# Confidential Information of ARM, Inc.
# Use subject to ARM license.
# Copyright (c) 2026 ARM, Inc.

# ACI Version r0p0

# Reifier 4.0.0

VERSION 5.7 ;

BUSBITCHARS "[]" ;

#name: High Density Single Port SRAM HVT RVT Compiler | TSMC CLN65LP Process 0.525um^2 Bit Cell 256 Rows Per Bank
#version: r0p0
#comment: 
#configuration:  -activity_factor 50 -back_biasing off -bits 32 -bmux on -bus_notation on -check_instname on -diodes on -drive 6 -ema on -frequency 1.0 -instname sp_hse_8192_m16 -left_bus_delim "[" -mux 16 -mvt "" -name_case upper -power_type otc -prefix "" -pwr_gnd_rename vddpe:VDDPE,vddce:VDDCE,vsse:VSSE -rcols 2 -redundancy off -retention on -right_bus_delim "]" -rows_p_bl 256 -rrows 0 -ser none -site_def off -top_layer m5-m9 -words 8192 -wp_size 1 -write_mask on -write_thru off -corners ff_1p32v_1p32v_125c,ff_1p32v_1p32v_m40c,ss_1p08v_1p08v_125c,ss_1p08v_1p08v_m40c,tt_1p20v_1p20v_25c
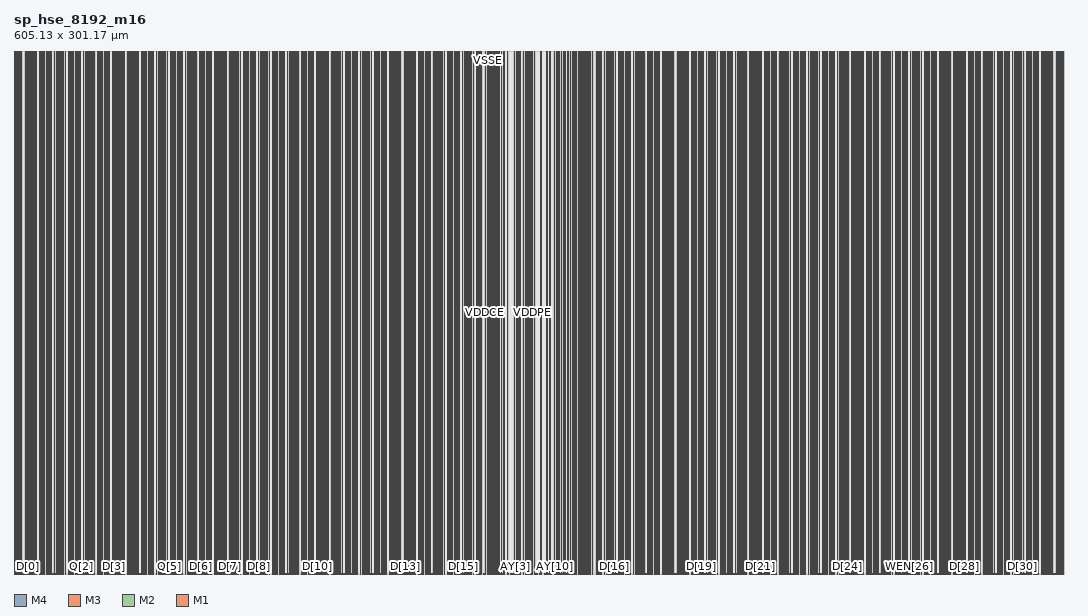
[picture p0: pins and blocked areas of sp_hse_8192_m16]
MACRO sp_hse_8192_m16
  FOREIGN sp_hse_8192_m16 0 0 ;
  SYMMETRY X Y R90 ;
  SIZE 605.13 BY 301.17 ;
  CLASS BLOCK ;
  PIN AY[0]
    DIRECTION OUTPUT ;
    USE SIGNAL ;
    SHAPE ABUTMENT ;
    PORT
      LAYER M4 ;
      RECT 305.835 0.0 306.055 0.32 ;
      LAYER M3 ;
      RECT 305.835 0.0 306.055 0.32 ;
      LAYER M2 ;
      RECT 305.835 0.0 306.055 0.32 ;
      LAYER M1 ;
      RECT 305.835 0.0 306.055 0.32 ;
      END
    ANTENNADIFFAREA 0.054 ;
    END AY[0]
  PIN TA[0]
    DIRECTION INPUT ;
    USE SIGNAL ;
    SHAPE ABUTMENT ;
    PORT
      LAYER M1 ;
      RECT 306.4 0.0 306.62 0.32 ;
      LAYER M2 ;
      RECT 306.4 0.0 306.62 0.32 ;
      LAYER M3 ;
      RECT 306.4 0.0 306.62 0.32 ;
      LAYER M4 ;
      RECT 306.4 0.0 306.62 0.32 ;
      END
    ANTENNAGATEAREA 0.0072 ;
    ANTENNADIFFAREA 0.054 ;
    END TA[0]
  PIN AY[1]
    DIRECTION OUTPUT ;
    USE SIGNAL ;
    SHAPE ABUTMENT ;
    PORT
      LAYER M4 ;
      RECT 302.61 0.0 302.83 0.32 ;
      LAYER M3 ;
      RECT 302.61 0.0 302.83 0.32 ;
      LAYER M2 ;
      RECT 302.61 0.0 302.83 0.32 ;
      LAYER M1 ;
      RECT 302.61 0.0 302.83 0.32 ;
      END
    ANTENNADIFFAREA 0.054 ;
    END AY[1]
  PIN A[0]
    DIRECTION INPUT ;
    USE SIGNAL ;
    SHAPE ABUTMENT ;
    PORT
      LAYER M1 ;
      RECT 306.85 0.0 307.07 0.32 ;
      LAYER M2 ;
      RECT 306.85 0.0 307.07 0.32 ;
      LAYER M3 ;
      RECT 306.85 0.0 307.07 0.32 ;
      END
    ANTENNAGATEAREA 0.0072 ;
    ANTENNADIFFAREA 0.054 ;
    END A[0]
  PIN A[1]
    DIRECTION INPUT ;
    USE SIGNAL ;
    SHAPE ABUTMENT ;
    PORT
      LAYER M4 ;
      RECT 301.225 0.0 301.445 0.32 ;
      LAYER M3 ;
      RECT 301.225 0.0 301.445 0.32 ;
      LAYER M2 ;
      RECT 301.225 0.0 301.445 0.32 ;
      LAYER M1 ;
      RECT 301.225 0.0 301.445 0.32 ;
      END
    ANTENNAGATEAREA 0.0072 ;
    ANTENNADIFFAREA 0.054 ;
    END A[1]
  PIN TA[11]
    DIRECTION INPUT ;
    USE SIGNAL ;
    SHAPE ABUTMENT ;
    PORT
      LAYER M1 ;
      RECT 307.295 0.0 307.515 0.32 ;
      LAYER M2 ;
      RECT 307.295 0.0 307.515 0.32 ;
      LAYER M3 ;
      RECT 307.295 0.0 307.515 0.32 ;
      END
    ANTENNAGATEAREA 0.0072 ;
    ANTENNADIFFAREA 0.054 ;
    END TA[11]
  PIN TA[1]
    DIRECTION INPUT ;
    USE SIGNAL ;
    SHAPE ABUTMENT ;
    PORT
      LAYER M4 ;
      RECT 300.785 0.0 300.995 0.32 ;
      LAYER M3 ;
      RECT 300.785 0.0 300.995 0.32 ;
      LAYER M2 ;
      RECT 300.785 0.0 300.995 0.32 ;
      LAYER M1 ;
      RECT 300.785 0.0 300.995 0.32 ;
      END
    ANTENNAGATEAREA 0.0072 ;
    ANTENNADIFFAREA 0.054 ;
    END TA[1]
  PIN A[11]
    DIRECTION INPUT ;
    USE SIGNAL ;
    SHAPE ABUTMENT ;
    PORT
      LAYER M1 ;
      RECT 307.745 0.0 307.965 0.32 ;
      LAYER M2 ;
      RECT 307.745 0.0 307.965 0.32 ;
      LAYER M3 ;
      RECT 307.745 0.0 307.965 0.32 ;
      END
    ANTENNAGATEAREA 0.0072 ;
    ANTENNADIFFAREA 0.054 ;
    END A[11]
  PIN TA[12]
    DIRECTION INPUT ;
    USE SIGNAL ;
    SHAPE ABUTMENT ;
    PORT
      LAYER M3 ;
      RECT 300.33 0.0 300.55 0.32 ;
      LAYER M2 ;
      RECT 300.33 0.0 300.55 0.32 ;
      LAYER M1 ;
      RECT 300.33 0.0 300.55 0.32 ;
      END
    ANTENNAGATEAREA 0.0072 ;
    ANTENNADIFFAREA 0.054 ;
    END TA[12]
  PIN EMA[1]
    DIRECTION INPUT ;
    USE SIGNAL ;
    SHAPE ABUTMENT ;
    PORT
      LAYER M1 ;
      RECT 308.215 0.0 308.435 0.32 ;
      LAYER M2 ;
      RECT 308.215 0.0 308.435 0.32 ;
      LAYER M3 ;
      RECT 308.215 0.0 308.435 0.32 ;
      END
    ANTENNAGATEAREA 0.0072 ;
    ANTENNADIFFAREA 0.054 ;
    END EMA[1]
  PIN A[12]
    DIRECTION INPUT ;
    USE SIGNAL ;
    SHAPE ABUTMENT ;
    PORT
      LAYER M3 ;
      RECT 299.855 0.0 300.075 0.32 ;
      LAYER M2 ;
      RECT 299.855 0.0 300.075 0.32 ;
      LAYER M1 ;
      RECT 299.855 0.0 300.075 0.32 ;
      END
    ANTENNAGATEAREA 0.0072 ;
    ANTENNADIFFAREA 0.054 ;
    END A[12]
  PIN AY[11]
    DIRECTION OUTPUT ;
    USE SIGNAL ;
    SHAPE ABUTMENT ;
    PORT
      LAYER M1 ;
      RECT 309.115 0.0 309.335 0.32 ;
      LAYER M2 ;
      RECT 309.115 0.0 309.335 0.32 ;
      END
    ANTENNADIFFAREA 0.054 ;
    END AY[11]
  PIN AY[12]
    DIRECTION OUTPUT ;
    USE SIGNAL ;
    SHAPE ABUTMENT ;
    PORT
      LAYER M3 ;
      RECT 298.46 0.0 298.68 0.32 ;
      LAYER M2 ;
      RECT 298.46 0.0 298.68 0.32 ;
      LAYER M1 ;
      RECT 298.46 0.0 298.68 0.32 ;
      END
    ANTENNADIFFAREA 0.054 ;
    END AY[12]
  PIN EMAW[0]
    DIRECTION INPUT ;
    USE SIGNAL ;
    SHAPE ABUTMENT ;
    PORT
      LAYER M1 ;
      RECT 309.57 0.0 309.79 0.32 ;
      LAYER M2 ;
      RECT 309.57 0.0 309.79 0.32 ;
      LAYER M3 ;
      RECT 309.57 0.0 309.79 0.32 ;
      LAYER M4 ;
      RECT 309.57 0.0 309.79 0.32 ;
      END
    ANTENNAGATEAREA 0.0072 ;
    ANTENNADIFFAREA 0.054 ;
    END EMAW[0]
  PIN RET1N
    DIRECTION INPUT ;
    USE SIGNAL ;
    SHAPE ABUTMENT ;
    PORT
      LAYER M4 ;
      RECT 290.225 0.0 290.445 0.32 ;
      LAYER M3 ;
      RECT 290.225 0.0 290.445 0.32 ;
      LAYER M2 ;
      RECT 290.225 0.0 290.445 0.32 ;
      LAYER M1 ;
      RECT 290.225 0.0 290.445 0.32 ;
      END
    ANTENNAGATEAREA 0.0072 ;
    ANTENNADIFFAREA 0.054 ;
    END RET1N
  PIN AY[10]
    DIRECTION OUTPUT ;
    USE SIGNAL ;
    SHAPE ABUTMENT ;
    PORT
      LAYER M1 ;
      RECT 311.945 0.0 312.155 0.32 ;
      LAYER M2 ;
      RECT 311.945 0.0 312.155 0.32 ;
      LAYER M3 ;
      RECT 311.945 0.0 312.155 0.32 ;
      LAYER M4 ;
      RECT 311.945 0.0 312.155 0.32 ;
      END
    ANTENNADIFFAREA 0.054 ;
    END AY[10]
  PIN AY[3]
    DIRECTION OUTPUT ;
    USE SIGNAL ;
    SHAPE ABUTMENT ;
    PORT
      LAYER M4 ;
      RECT 289.035 0.0 289.255 0.32 ;
      LAYER M3 ;
      RECT 289.035 0.0 289.255 0.32 ;
      LAYER M2 ;
      RECT 289.035 0.0 289.255 0.32 ;
      LAYER M1 ;
      RECT 289.035 0.0 289.255 0.32 ;
      END
    ANTENNADIFFAREA 0.054 ;
    END AY[3]
  PIN A[10]
    DIRECTION INPUT ;
    USE SIGNAL ;
    SHAPE ABUTMENT ;
    PORT
      LAYER M1 ;
      RECT 313.29 0.0 313.51 0.32 ;
      LAYER M2 ;
      RECT 313.29 0.0 313.51 0.32 ;
      LAYER M3 ;
      RECT 313.29 0.0 313.51 0.32 ;
      LAYER M4 ;
      RECT 313.29 0.0 313.51 0.32 ;
      END
    ANTENNAGATEAREA 0.0072 ;
    ANTENNADIFFAREA 0.054 ;
    END A[10]
  PIN TEN
    DIRECTION INPUT ;
    USE SIGNAL ;
    SHAPE ABUTMENT ;
    PORT
      LAYER M3 ;
      RECT 288.265 0.0 288.485 0.32 ;
      LAYER M2 ;
      RECT 288.265 0.0 288.485 0.32 ;
      LAYER M1 ;
      RECT 288.265 0.0 288.485 0.32 ;
      END
    ANTENNAGATEAREA 0.0072 ;
    ANTENNADIFFAREA 0.054 ;
    END TEN
  PIN TA[10]
    DIRECTION INPUT ;
    USE SIGNAL ;
    SHAPE ABUTMENT ;
    PORT
      LAYER M1 ;
      RECT 313.74 0.0 313.96 0.32 ;
      LAYER M2 ;
      RECT 313.74 0.0 313.96 0.32 ;
      LAYER M3 ;
      RECT 313.74 0.0 313.96 0.32 ;
      END
    ANTENNAGATEAREA 0.0072 ;
    ANTENNADIFFAREA 0.054 ;
    END TA[10]
  PIN A[3]
    DIRECTION INPUT ;
    USE SIGNAL ;
    SHAPE ABUTMENT ;
    PORT
      LAYER M2 ;
      RECT 287.815 0.0 288.035 0.32 ;
      LAYER M1 ;
      RECT 287.815 0.0 288.035 0.32 ;
      END
    ANTENNAGATEAREA 0.0072 ;
    ANTENNADIFFAREA 0.054 ;
    END A[3]
  PIN TA[9]
    DIRECTION INPUT ;
    USE SIGNAL ;
    SHAPE ABUTMENT ;
    PORT
      LAYER M1 ;
      RECT 314.19 0.0 314.41 0.32 ;
      LAYER M2 ;
      RECT 314.19 0.0 314.41 0.32 ;
      LAYER M3 ;
      RECT 314.19 0.0 314.41 0.32 ;
      END
    ANTENNAGATEAREA 0.0072 ;
    ANTENNADIFFAREA 0.054 ;
    END TA[9]
  PIN TA[3]
    DIRECTION INPUT ;
    USE SIGNAL ;
    SHAPE ABUTMENT ;
    PORT
      LAYER M2 ;
      RECT 287.365 0.0 287.585 0.32 ;
      LAYER M1 ;
      RECT 287.365 0.0 287.585 0.32 ;
      END
    ANTENNAGATEAREA 0.0072 ;
    ANTENNADIFFAREA 0.054 ;
    END TA[3]
  PIN A[9]
    DIRECTION INPUT ;
    USE SIGNAL ;
    SHAPE ABUTMENT ;
    PORT
      LAYER M1 ;
      RECT 314.63 0.0 314.85 0.32 ;
      LAYER M2 ;
      RECT 314.63 0.0 314.85 0.32 ;
      LAYER M3 ;
      RECT 314.63 0.0 314.85 0.32 ;
      LAYER M4 ;
      RECT 314.63 0.0 314.85 0.32 ;
      END
    ANTENNAGATEAREA 0.0072 ;
    ANTENNADIFFAREA 0.054 ;
    END A[9]
  PIN TCEN
    DIRECTION INPUT ;
    USE SIGNAL ;
    SHAPE ABUTMENT ;
    PORT
      LAYER M3 ;
      RECT 286.92 0.0 287.14 0.32 ;
      LAYER M2 ;
      RECT 286.92 0.0 287.14 0.32 ;
      LAYER M1 ;
      RECT 286.92 0.0 287.14 0.32 ;
      END
    ANTENNAGATEAREA 0.0072 ;
    ANTENNADIFFAREA 0.054 ;
    END TCEN
  PIN AY[9]
    DIRECTION OUTPUT ;
    USE SIGNAL ;
    SHAPE ABUTMENT ;
    PORT
      LAYER M1 ;
      RECT 315.51 0.0 315.73 0.32 ;
      LAYER M2 ;
      RECT 315.51 0.0 315.73 0.32 ;
      END
    ANTENNADIFFAREA 0.054 ;
    END AY[9]
  PIN CEN
    DIRECTION INPUT ;
    USE SIGNAL ;
    SHAPE ABUTMENT ;
    PORT
      LAYER M4 ;
      RECT 286.47 0.0 286.69 0.32 ;
      LAYER M3 ;
      RECT 286.47 0.0 286.69 0.32 ;
      LAYER M2 ;
      RECT 286.47 0.0 286.69 0.32 ;
      LAYER M1 ;
      RECT 286.47 0.0 286.69 0.32 ;
      END
    ANTENNAGATEAREA 0.0072 ;
    ANTENNADIFFAREA 0.054 ;
    END CEN
  PIN EMAW[1]
    DIRECTION INPUT ;
    USE SIGNAL ;
    SHAPE ABUTMENT ;
    PORT
      LAYER M1 ;
      RECT 316.09 0.0 316.31 0.32 ;
      LAYER M2 ;
      RECT 316.09 0.0 316.31 0.32 ;
      LAYER M3 ;
      RECT 316.09 0.0 316.31 0.32 ;
      LAYER M4 ;
      RECT 316.09 0.0 316.31 0.32 ;
      END
    ANTENNAGATEAREA 0.0072 ;
    ANTENNADIFFAREA 0.054 ;
    END EMAW[1]
  PIN DFTRAMBYP
    DIRECTION INPUT ;
    USE SIGNAL ;
    SHAPE ABUTMENT ;
    PORT
      LAYER M4 ;
      RECT 286.025 0.0 286.245 0.32 ;
      LAYER M3 ;
      RECT 286.025 0.0 286.245 0.32 ;
      END
    ANTENNAGATEAREA 0.0072 ;
    ANTENNADIFFAREA 0.054 ;
    END DFTRAMBYP
  PIN CLK
    DIRECTION INPUT ;
    USE SIGNAL ;
    SHAPE ABUTMENT ;
    PORT
      LAYER M1 ;
      RECT 317.65 0.0 317.87 0.32 ;
      LAYER M2 ;
      RECT 317.65 0.0 317.87 0.32 ;
      LAYER M3 ;
      RECT 317.65 0.0 317.87 0.32 ;
      END
    ANTENNAGATEAREA 0.0072 ;
    ANTENNADIFFAREA 0.054 ;
    END CLK
  PIN CENY
    DIRECTION OUTPUT ;
    USE SIGNAL ;
    SHAPE ABUTMENT ;
    PORT
      LAYER M4 ;
      RECT 285.035 0.0 285.255 0.32 ;
      LAYER M3 ;
      RECT 285.035 0.0 285.255 0.32 ;
      LAYER M2 ;
      RECT 285.035 0.0 285.255 0.32 ;
      LAYER M1 ;
      RECT 285.035 0.0 285.255 0.32 ;
      END
    ANTENNADIFFAREA 0.054 ;
    END CENY
  PIN EMA[0]
    DIRECTION INPUT ;
    USE SIGNAL ;
    SHAPE ABUTMENT ;
    PORT
      LAYER M1 ;
      RECT 318.11 0.0 318.33 0.32 ;
      LAYER M2 ;
      RECT 318.11 0.0 318.33 0.32 ;
      LAYER M3 ;
      RECT 318.11 0.0 318.33 0.32 ;
      LAYER M4 ;
      RECT 318.11 0.0 318.33 0.32 ;
      END
    ANTENNAGATEAREA 0.0072 ;
    ANTENNADIFFAREA 0.054 ;
    END EMA[0]
  PIN GWENY
    DIRECTION OUTPUT ;
    USE SIGNAL ;
    SHAPE ABUTMENT ;
    PORT
      LAYER M3 ;
      RECT 282.48 0.0 282.7 0.32 ;
      LAYER M2 ;
      RECT 282.48 0.0 282.7 0.32 ;
      LAYER M1 ;
      RECT 282.48 0.0 282.7 0.32 ;
      END
    ANTENNADIFFAREA 0.054 ;
    END GWENY
  PIN AY[8]
    DIRECTION OUTPUT ;
    USE SIGNAL ;
    SHAPE ABUTMENT ;
    PORT
      LAYER M1 ;
      RECT 318.56 0.0 318.78 0.32 ;
      LAYER M2 ;
      RECT 318.56 0.0 318.78 0.32 ;
      LAYER M3 ;
      RECT 318.56 0.0 318.78 0.32 ;
      LAYER M4 ;
      RECT 318.56 0.0 318.78 0.32 ;
      END
    ANTENNADIFFAREA 0.054 ;
    END AY[8]
  PIN GWEN
    DIRECTION INPUT ;
    USE SIGNAL ;
    SHAPE ABUTMENT ;
    PORT
      LAYER M3 ;
      RECT 281.11 0.0 281.33 0.32 ;
      LAYER M2 ;
      RECT 281.11 0.0 281.33 0.32 ;
      LAYER M1 ;
      RECT 281.11 0.0 281.33 0.32 ;
      END
    ANTENNAGATEAREA 0.0072 ;
    ANTENNADIFFAREA 0.054 ;
    END GWEN
  PIN EMA[2]
    DIRECTION INPUT ;
    USE SIGNAL ;
    SHAPE ABUTMENT ;
    PORT
      LAYER M1 ;
      RECT 319.52 0.0 319.74 0.32 ;
      LAYER M2 ;
      RECT 319.52 0.0 319.74 0.32 ;
      LAYER M3 ;
      RECT 319.52 0.0 319.74 0.32 ;
      END
    ANTENNAGATEAREA 0.0072 ;
    ANTENNADIFFAREA 0.054 ;
    END EMA[2]
  PIN TGWEN
    DIRECTION INPUT ;
    USE SIGNAL ;
    SHAPE ABUTMENT ;
    PORT
      LAYER M3 ;
      RECT 280.665 0.0 280.885 0.32 ;
      LAYER M2 ;
      RECT 280.665 0.0 280.885 0.32 ;
      LAYER M1 ;
      RECT 280.665 0.0 280.885 0.32 ;
      END
    ANTENNAGATEAREA 0.0072 ;
    ANTENNADIFFAREA 0.054 ;
    END TGWEN
  PIN A[8]
    DIRECTION INPUT ;
    USE SIGNAL ;
    SHAPE ABUTMENT ;
    PORT
      LAYER M1 ;
      RECT 319.995 0.0 320.215 0.32 ;
      LAYER M2 ;
      RECT 319.995 0.0 320.215 0.32 ;
      LAYER M3 ;
      RECT 319.995 0.0 320.215 0.32 ;
      LAYER M4 ;
      RECT 319.995 0.0 320.215 0.32 ;
      END
    ANTENNAGATEAREA 0.0072 ;
    ANTENNADIFFAREA 0.054 ;
    END A[8]
  PIN TA[2]
    DIRECTION INPUT ;
    USE SIGNAL ;
    SHAPE ABUTMENT ;
    PORT
      LAYER M4 ;
      RECT 280.215 0.0 280.435 0.32 ;
      LAYER M3 ;
      RECT 280.215 0.0 280.435 0.32 ;
      LAYER M2 ;
      RECT 280.215 0.0 280.435 0.32 ;
      LAYER M1 ;
      RECT 280.215 0.0 280.435 0.32 ;
      END
    ANTENNAGATEAREA 0.0072 ;
    ANTENNADIFFAREA 0.054 ;
    END TA[2]
  PIN TA[8]
    DIRECTION INPUT ;
    USE SIGNAL ;
    SHAPE ABUTMENT ;
    PORT
      LAYER M1 ;
      RECT 320.44 0.0 320.66 0.32 ;
      LAYER M2 ;
      RECT 320.44 0.0 320.66 0.32 ;
      LAYER M3 ;
      RECT 320.44 0.0 320.66 0.32 ;
      END
    ANTENNAGATEAREA 0.0072 ;
    ANTENNADIFFAREA 0.054 ;
    END TA[8]
  PIN A[2]
    DIRECTION INPUT ;
    USE SIGNAL ;
    SHAPE ABUTMENT ;
    PORT
      LAYER M3 ;
      RECT 279.77 0.0 279.99 0.32 ;
      LAYER M2 ;
      RECT 279.77 0.0 279.99 0.32 ;
      LAYER M1 ;
      RECT 279.77 0.0 279.99 0.32 ;
      END
    ANTENNAGATEAREA 0.0072 ;
    ANTENNADIFFAREA 0.054 ;
    END A[2]
  PIN TA[7]
    DIRECTION INPUT ;
    USE SIGNAL ;
    SHAPE ABUTMENT ;
    PORT
      LAYER M1 ;
      RECT 320.895 0.0 321.115 0.32 ;
      LAYER M2 ;
      RECT 320.895 0.0 321.115 0.32 ;
      LAYER M3 ;
      RECT 320.895 0.0 321.115 0.32 ;
      END
    ANTENNAGATEAREA 0.0072 ;
    ANTENNADIFFAREA 0.054 ;
    END TA[7]
  PIN AY[2]
    DIRECTION OUTPUT ;
    USE SIGNAL ;
    SHAPE ABUTMENT ;
    PORT
      LAYER M4 ;
      RECT 277.635 0.0 277.855 0.32 ;
      LAYER M3 ;
      RECT 277.635 0.0 277.855 0.32 ;
      LAYER M2 ;
      RECT 277.635 0.0 277.855 0.32 ;
      LAYER M1 ;
      RECT 277.635 0.0 277.855 0.32 ;
      END
    ANTENNADIFFAREA 0.054 ;
    END AY[2]
  PIN A[7]
    DIRECTION INPUT ;
    USE SIGNAL ;
    SHAPE ABUTMENT ;
    PORT
      LAYER M1 ;
      RECT 321.34 0.0 321.56 0.32 ;
      LAYER M2 ;
      RECT 321.34 0.0 321.56 0.32 ;
      LAYER M3 ;
      RECT 321.34 0.0 321.56 0.32 ;
      LAYER M4 ;
      RECT 321.34 0.0 321.56 0.32 ;
      END
    ANTENNAGATEAREA 0.0072 ;
    ANTENNADIFFAREA 0.054 ;
    END A[7]
  PIN AY[5]
    DIRECTION OUTPUT ;
    USE SIGNAL ;
    SHAPE ABUTMENT ;
    PORT
      LAYER M3 ;
      RECT 275.72 0.0 275.94 0.32 ;
      LAYER M2 ;
      RECT 275.72 0.0 275.94 0.32 ;
      LAYER M1 ;
      RECT 275.72 0.0 275.94 0.32 ;
      END
    ANTENNADIFFAREA 0.054 ;
    END AY[5]
  PIN AY[7]
    DIRECTION OUTPUT ;
    USE SIGNAL ;
    SHAPE ABUTMENT ;
    PORT
      LAYER M1 ;
      RECT 323.095 0.0 323.315 0.32 ;
      LAYER M2 ;
      RECT 323.095 0.0 323.315 0.32 ;
      LAYER M3 ;
      RECT 323.095 0.0 323.315 0.32 ;
      END
    ANTENNADIFFAREA 0.054 ;
    END AY[7]
  PIN A[5]
    DIRECTION INPUT ;
    USE SIGNAL ;
    SHAPE ABUTMENT ;
    PORT
      LAYER M3 ;
      RECT 274.49 0.0 274.71 0.32 ;
      LAYER M2 ;
      RECT 274.49 0.0 274.71 0.32 ;
      LAYER M1 ;
      RECT 274.49 0.0 274.71 0.32 ;
      END
    ANTENNAGATEAREA 0.0072 ;
    ANTENNADIFFAREA 0.054 ;
    END A[5]
  PIN SO[1]
    DIRECTION OUTPUT ;
    USE SIGNAL ;
    SHAPE ABUTMENT ;
    PORT
      LAYER M1 ;
      RECT 325.48 0.0 325.7 0.32 ;
      LAYER M2 ;
      RECT 325.48 0.0 325.7 0.32 ;
      LAYER M3 ;
      RECT 325.48 0.0 325.7 0.32 ;
      END
    ANTENNADIFFAREA 0.054 ;
    END SO[1]
  PIN TA[5]
    DIRECTION INPUT ;
    USE SIGNAL ;
    SHAPE ABUTMENT ;
    PORT
      LAYER M3 ;
      RECT 274.04 0.0 274.26 0.32 ;
      LAYER M2 ;
      RECT 274.04 0.0 274.26 0.32 ;
      LAYER M1 ;
      RECT 274.04 0.0 274.26 0.32 ;
      END
    ANTENNAGATEAREA 0.0072 ;
    ANTENNADIFFAREA 0.054 ;
    END TA[5]
  PIN AY[6]
    DIRECTION OUTPUT ;
    USE SIGNAL ;
    SHAPE ABUTMENT ;
    PORT
      LAYER M1 ;
      RECT 325.955 0.0 326.175 0.32 ;
      LAYER M2 ;
      RECT 325.955 0.0 326.175 0.32 ;
      LAYER M3 ;
      RECT 325.955 0.0 326.175 0.32 ;
      LAYER M4 ;
      RECT 325.955 0.0 326.175 0.32 ;
      END
    ANTENNADIFFAREA 0.054 ;
    END AY[6]
  PIN TA[4]
    DIRECTION INPUT ;
    USE SIGNAL ;
    SHAPE ABUTMENT ;
    PORT
      LAYER M4 ;
      RECT 273.6 0.0 273.82 0.32 ;
      LAYER M3 ;
      RECT 273.6 0.0 273.82 0.32 ;
      LAYER M2 ;
      RECT 273.6 0.0 273.82 0.32 ;
      LAYER M1 ;
      RECT 273.6 0.0 273.82 0.32 ;
      END
    ANTENNAGATEAREA 0.0072 ;
    ANTENNADIFFAREA 0.054 ;
    END TA[4]
  PIN A[6]
    DIRECTION INPUT ;
    USE SIGNAL ;
    SHAPE ABUTMENT ;
    PORT
      LAYER M1 ;
      RECT 326.88 0.0 327.1 0.32 ;
      LAYER M2 ;
      RECT 326.88 0.0 327.1 0.32 ;
      LAYER M3 ;
      RECT 326.88 0.0 327.1 0.32 ;
      END
    ANTENNAGATEAREA 0.0072 ;
    ANTENNADIFFAREA 0.054 ;
    END A[6]
  PIN A[4]
    DIRECTION INPUT ;
    USE SIGNAL ;
    SHAPE ABUTMENT ;
    PORT
      LAYER M3 ;
      RECT 273.145 0.0 273.375 0.32 ;
      LAYER M2 ;
      RECT 273.145 0.0 273.375 0.32 ;
      LAYER M1 ;
      RECT 273.145 0.0 273.375 0.32 ;
      END
    ANTENNAGATEAREA 0.0072 ;
    ANTENNADIFFAREA 0.054 ;
    END A[4]
  PIN TA[6]
    DIRECTION INPUT ;
    USE SIGNAL ;
    SHAPE ABUTMENT ;
    PORT
      LAYER M1 ;
      RECT 327.32 0.0 327.54 0.32 ;
      LAYER M2 ;
      RECT 327.32 0.0 327.54 0.32 ;
      LAYER M3 ;
      RECT 327.32 0.0 327.54 0.32 ;
      LAYER M4 ;
      RECT 327.32 0.0 327.54 0.32 ;
      END
    ANTENNAGATEAREA 0.0072 ;
    ANTENNADIFFAREA 0.054 ;
    END TA[6]
  PIN AY[4]
    DIRECTION OUTPUT ;
    USE SIGNAL ;
    SHAPE ABUTMENT ;
    PORT
      LAYER M4 ;
      RECT 270.83 0.0 271.05 0.32 ;
      LAYER M3 ;
      RECT 270.83 0.0 271.05 0.32 ;
      LAYER M2 ;
      RECT 270.83 0.0 271.05 0.32 ;
      LAYER M1 ;
      RECT 270.83 0.0 271.05 0.32 ;
      END
    ANTENNADIFFAREA 0.054 ;
    END AY[4]
  PIN SE
    DIRECTION INPUT ;
    USE SIGNAL ;
    SHAPE ABUTMENT ;
    PORT
      LAYER M1 ;
      RECT 327.765 0.0 327.985 0.32 ;
      LAYER M2 ;
      RECT 327.765 0.0 327.985 0.32 ;
      LAYER M3 ;
      RECT 327.765 0.0 327.985 0.32 ;
      END
    ANTENNAGATEAREA 0.0072 ;
    ANTENNADIFFAREA 0.054 ;
    END SE
  PIN SO[0]
    DIRECTION OUTPUT ;
    USE SIGNAL ;
    SHAPE ABUTMENT ;
    PORT
      LAYER M4 ;
      RECT 270.325 0.0 270.545 0.32 ;
      LAYER M3 ;
      RECT 270.325 0.0 270.545 0.32 ;
      LAYER M2 ;
      RECT 270.325 0.0 270.545 0.32 ;
      LAYER M1 ;
      RECT 270.325 0.0 270.545 0.32 ;
      END
    ANTENNADIFFAREA 0.054 ;
    END SO[0]
  PIN TD[16]
    DIRECTION INPUT ;
    USE SIGNAL ;
    SHAPE ABUTMENT ;
    PORT
      LAYER M1 ;
      RECT 343.69 0.0 343.89 0.32 ;
      LAYER M2 ;
      RECT 343.69 0.0 343.89 0.32 ;
      LAYER M3 ;
      RECT 343.69 0.0 343.89 0.32 ;
      END
    ANTENNAGATEAREA 0.0072 ;
    ANTENNADIFFAREA 0.054 ;
    END TD[16]
  PIN TD[15]
    DIRECTION INPUT ;
    USE SIGNAL ;
    SHAPE ABUTMENT ;
    PORT
      LAYER M3 ;
      RECT 261.24 0.0 261.44 0.32 ;
      LAYER M2 ;
      RECT 261.24 0.0 261.44 0.32 ;
      LAYER M1 ;
      RECT 261.24 0.0 261.44 0.32 ;
      END
    ANTENNAGATEAREA 0.0072 ;
    ANTENNADIFFAREA 0.054 ;
    END TD[15]
  PIN D[16]
    DIRECTION INPUT ;
    USE SIGNAL ;
    SHAPE ABUTMENT ;
    PORT
      LAYER M1 ;
      RECT 345.99 0.0 346.19 0.32 ;
      LAYER M2 ;
      RECT 345.99 0.0 346.19 0.32 ;
      LAYER M3 ;
      RECT 345.99 0.0 346.19 0.32 ;
      LAYER M4 ;
      RECT 345.99 0.0 346.19 0.32 ;
      END
    ANTENNAGATEAREA 0.0072 ;
    ANTENNADIFFAREA 0.054 ;
    END D[16]
  PIN D[15]
    DIRECTION INPUT ;
    USE SIGNAL ;
    SHAPE ABUTMENT ;
    PORT
      LAYER M4 ;
      RECT 258.94 0.0 259.14 0.32 ;
      LAYER M3 ;
      RECT 258.94 0.0 259.14 0.32 ;
      LAYER M2 ;
      RECT 258.94 0.0 259.14 0.32 ;
      LAYER M1 ;
      RECT 258.94 0.0 259.14 0.32 ;
      END
    ANTENNAGATEAREA 0.0072 ;
    ANTENNADIFFAREA 0.054 ;
    END D[15]
  PIN TWEN[16]
    DIRECTION INPUT ;
    USE SIGNAL ;
    SHAPE ABUTMENT ;
    PORT
      LAYER M1 ;
      RECT 347.045 0.0 347.245 0.32 ;
      LAYER M2 ;
      RECT 347.045 0.0 347.245 0.32 ;
      LAYER M3 ;
      RECT 347.045 0.0 347.245 0.32 ;
      LAYER M4 ;
      RECT 347.045 0.0 347.245 0.32 ;
      END
    ANTENNAGATEAREA 0.0072 ;
    ANTENNADIFFAREA 0.054 ;
    END TWEN[16]
  PIN TWEN[15]
    DIRECTION INPUT ;
    USE SIGNAL ;
    SHAPE ABUTMENT ;
    PORT
      LAYER M4 ;
      RECT 257.885 0.0 258.085 0.32 ;
      LAYER M3 ;
      RECT 257.885 0.0 258.085 0.32 ;
      LAYER M2 ;
      RECT 257.885 0.0 258.085 0.32 ;
      LAYER M1 ;
      RECT 257.885 0.0 258.085 0.32 ;
      END
    ANTENNAGATEAREA 0.0072 ;
    ANTENNADIFFAREA 0.054 ;
    END TWEN[15]
  PIN Q[16]
    DIRECTION OUTPUT ;
    USE SIGNAL ;
    SHAPE ABUTMENT ;
    PORT
      LAYER M1 ;
      RECT 347.625 0.0 347.825 0.32 ;
      LAYER M2 ;
      RECT 347.625 0.0 347.825 0.32 ;
      LAYER M3 ;
      RECT 347.625 0.0 347.825 0.32 ;
      END
    ANTENNADIFFAREA 0.054 ;
    END Q[16]
  PIN Q[15]
    DIRECTION OUTPUT ;
    USE SIGNAL ;
    SHAPE ABUTMENT ;
    PORT
      LAYER M3 ;
      RECT 257.305 0.0 257.505 0.32 ;
      LAYER M2 ;
      RECT 257.305 0.0 257.505 0.32 ;
      LAYER M1 ;
      RECT 257.305 0.0 257.505 0.32 ;
      END
    ANTENNADIFFAREA 0.054 ;
    END Q[15]
  PIN WEN[16]
    DIRECTION INPUT ;
    USE SIGNAL ;
    SHAPE ABUTMENT ;
    PORT
      LAYER M4 ;
      RECT 348.09 0.0 348.27 0.32 ;
      LAYER M1 ;
      RECT 348.1 0.0 348.3 0.32 ;
      LAYER M2 ;
      RECT 348.1 0.0 348.3 0.32 ;
      LAYER M3 ;
      RECT 348.1 0.0 348.3 0.32 ;
      END
    ANTENNAGATEAREA 0.0072 ;
    ANTENNADIFFAREA 0.054 ;
    END WEN[16]
  PIN WEN[15]
    DIRECTION INPUT ;
    USE SIGNAL ;
    SHAPE ABUTMENT ;
    PORT
      LAYER M4 ;
      RECT 256.86 0.0 257.04 0.32 ;
      LAYER M3 ;
      RECT 256.83 0.0 257.03 0.32 ;
      LAYER M2 ;
      RECT 256.83 0.0 257.03 0.32 ;
      LAYER M1 ;
      RECT 256.83 0.0 257.03 0.32 ;
      END
    ANTENNAGATEAREA 0.0072 ;
    ANTENNADIFFAREA 0.054 ;
    END WEN[15]
  PIN WENY[16]
    DIRECTION OUTPUT ;
    USE SIGNAL ;
    SHAPE ABUTMENT ;
    PORT
      LAYER M4 ;
      RECT 349.14 0.0 349.32 0.32 ;
      LAYER M3 ;
      RECT 349.155 0.0 349.355 0.32 ;
      END
    ANTENNADIFFAREA 0.054 ;
    END WENY[16]
  PIN WENY[15]
    DIRECTION OUTPUT ;
    USE SIGNAL ;
    SHAPE ABUTMENT ;
    PORT
      LAYER M4 ;
      RECT 255.81 0.0 255.99 0.32 ;
      LAYER M3 ;
      RECT 255.775 0.0 255.975 0.32 ;
      END
    ANTENNADIFFAREA 0.054 ;
    END WENY[15]
  PIN TD[17]
    DIRECTION INPUT ;
    USE SIGNAL ;
    SHAPE ABUTMENT ;
    PORT
      LAYER M1 ;
      RECT 360.49 0.0 360.69 0.32 ;
      LAYER M2 ;
      RECT 360.49 0.0 360.69 0.32 ;
      LAYER M3 ;
      RECT 360.49 0.0 360.69 0.32 ;
      END
    ANTENNAGATEAREA 0.0072 ;
    ANTENNADIFFAREA 0.054 ;
    END TD[17]
  PIN TD[14]
    DIRECTION INPUT ;
    USE SIGNAL ;
    SHAPE ABUTMENT ;
    PORT
      LAYER M3 ;
      RECT 244.44 0.0 244.64 0.32 ;
      LAYER M2 ;
      RECT 244.44 0.0 244.64 0.32 ;
      LAYER M1 ;
      RECT 244.44 0.0 244.64 0.32 ;
      END
    ANTENNAGATEAREA 0.0072 ;
    ANTENNADIFFAREA 0.054 ;
    END TD[14]
  PIN D[17]
    DIRECTION INPUT ;
    USE SIGNAL ;
    SHAPE ABUTMENT ;
    PORT
      LAYER M1 ;
      RECT 362.79 0.0 362.99 0.32 ;
      LAYER M2 ;
      RECT 362.79 0.0 362.99 0.32 ;
      LAYER M3 ;
      RECT 362.79 0.0 362.99 0.32 ;
      LAYER M4 ;
      RECT 362.79 0.0 362.99 0.32 ;
      END
    ANTENNAGATEAREA 0.0072 ;
    ANTENNADIFFAREA 0.054 ;
    END D[17]
  PIN D[14]
    DIRECTION INPUT ;
    USE SIGNAL ;
    SHAPE ABUTMENT ;
    PORT
      LAYER M4 ;
      RECT 242.14 0.0 242.34 0.32 ;
      LAYER M3 ;
      RECT 242.14 0.0 242.34 0.32 ;
      LAYER M2 ;
      RECT 242.14 0.0 242.34 0.32 ;
      LAYER M1 ;
      RECT 242.14 0.0 242.34 0.32 ;
      END
    ANTENNAGATEAREA 0.0072 ;
    ANTENNADIFFAREA 0.054 ;
    END D[14]
  PIN TWEN[17]
    DIRECTION INPUT ;
    USE SIGNAL ;
    SHAPE ABUTMENT ;
    PORT
      LAYER M1 ;
      RECT 363.845 0.0 364.045 0.32 ;
      LAYER M2 ;
      RECT 363.845 0.0 364.045 0.32 ;
      LAYER M3 ;
      RECT 363.845 0.0 364.045 0.32 ;
      LAYER M4 ;
      RECT 363.845 0.0 364.045 0.32 ;
      END
    ANTENNAGATEAREA 0.0072 ;
    ANTENNADIFFAREA 0.054 ;
    END TWEN[17]
  PIN TWEN[14]
    DIRECTION INPUT ;
    USE SIGNAL ;
    SHAPE ABUTMENT ;
    PORT
      LAYER M4 ;
      RECT 241.085 0.0 241.285 0.32 ;
      LAYER M3 ;
      RECT 241.085 0.0 241.285 0.32 ;
      LAYER M2 ;
      RECT 241.085 0.0 241.285 0.32 ;
      LAYER M1 ;
      RECT 241.085 0.0 241.285 0.32 ;
      END
    ANTENNAGATEAREA 0.0072 ;
    ANTENNADIFFAREA 0.054 ;
    END TWEN[14]
  PIN Q[17]
    DIRECTION OUTPUT ;
    USE SIGNAL ;
    SHAPE ABUTMENT ;
    PORT
      LAYER M1 ;
      RECT 364.425 0.0 364.625 0.32 ;
      LAYER M2 ;
      RECT 364.425 0.0 364.625 0.32 ;
      LAYER M3 ;
      RECT 364.425 0.0 364.625 0.32 ;
      END
    ANTENNADIFFAREA 0.054 ;
    END Q[17]
  PIN Q[14]
    DIRECTION OUTPUT ;
    USE SIGNAL ;
    SHAPE ABUTMENT ;
    PORT
      LAYER M3 ;
      RECT 240.505 0.0 240.705 0.32 ;
      LAYER M2 ;
      RECT 240.505 0.0 240.705 0.32 ;
      LAYER M1 ;
      RECT 240.505 0.0 240.705 0.32 ;
      END
    ANTENNADIFFAREA 0.054 ;
    END Q[14]
  PIN WEN[17]
    DIRECTION INPUT ;
    USE SIGNAL ;
    SHAPE ABUTMENT ;
    PORT
      LAYER M4 ;
      RECT 364.89 0.0 365.07 0.32 ;
      LAYER M1 ;
      RECT 364.9 0.0 365.1 0.32 ;
      LAYER M2 ;
      RECT 364.9 0.0 365.1 0.32 ;
      LAYER M3 ;
      RECT 364.9 0.0 365.1 0.32 ;
      END
    ANTENNAGATEAREA 0.0072 ;
    ANTENNADIFFAREA 0.054 ;
    END WEN[17]
  PIN WEN[14]
    DIRECTION INPUT ;
    USE SIGNAL ;
    SHAPE ABUTMENT ;
    PORT
      LAYER M4 ;
      RECT 240.06 0.0 240.24 0.32 ;
      LAYER M3 ;
      RECT 240.03 0.0 240.23 0.32 ;
      LAYER M2 ;
      RECT 240.03 0.0 240.23 0.32 ;
      LAYER M1 ;
      RECT 240.03 0.0 240.23 0.32 ;
      END
    ANTENNAGATEAREA 0.0072 ;
    ANTENNADIFFAREA 0.054 ;
    END WEN[14]
  PIN WENY[17]
    DIRECTION OUTPUT ;
    USE SIGNAL ;
    SHAPE ABUTMENT ;
    PORT
      LAYER M4 ;
      RECT 365.94 0.0 366.12 0.32 ;
      LAYER M3 ;
      RECT 365.955 0.0 366.155 0.32 ;
      END
    ANTENNADIFFAREA 0.054 ;
    END WENY[17]
  PIN WENY[14]
    DIRECTION OUTPUT ;
    USE SIGNAL ;
    SHAPE ABUTMENT ;
    PORT
      LAYER M4 ;
      RECT 239.01 0.0 239.19 0.32 ;
      LAYER M3 ;
      RECT 238.975 0.0 239.175 0.32 ;
      END
    ANTENNADIFFAREA 0.054 ;
    END WENY[14]
  PIN TD[18]
    DIRECTION INPUT ;
    USE SIGNAL ;
    SHAPE ABUTMENT ;
    PORT
      LAYER M1 ;
      RECT 377.29 0.0 377.49 0.32 ;
      LAYER M2 ;
      RECT 377.29 0.0 377.49 0.32 ;
      LAYER M3 ;
      RECT 377.29 0.0 377.49 0.32 ;
      END
    ANTENNAGATEAREA 0.0072 ;
    ANTENNADIFFAREA 0.054 ;
    END TD[18]
  PIN TD[13]
    DIRECTION INPUT ;
    USE SIGNAL ;
    SHAPE ABUTMENT ;
    PORT
      LAYER M3 ;
      RECT 227.64 0.0 227.84 0.32 ;
      LAYER M2 ;
      RECT 227.64 0.0 227.84 0.32 ;
      LAYER M1 ;
      RECT 227.64 0.0 227.84 0.32 ;
      END
    ANTENNAGATEAREA 0.0072 ;
    ANTENNADIFFAREA 0.054 ;
    END TD[13]
  PIN D[18]
    DIRECTION INPUT ;
    USE SIGNAL ;
    SHAPE ABUTMENT ;
    PORT
      LAYER M1 ;
      RECT 379.59 0.0 379.79 0.32 ;
      LAYER M2 ;
      RECT 379.59 0.0 379.79 0.32 ;
      LAYER M3 ;
      RECT 379.59 0.0 379.79 0.32 ;
      LAYER M4 ;
      RECT 379.59 0.0 379.79 0.32 ;
      END
    ANTENNAGATEAREA 0.0072 ;
    ANTENNADIFFAREA 0.054 ;
    END D[18]
  PIN D[13]
    DIRECTION INPUT ;
    USE SIGNAL ;
    SHAPE ABUTMENT ;
    PORT
      LAYER M4 ;
      RECT 225.34 0.0 225.54 0.32 ;
      LAYER M3 ;
      RECT 225.34 0.0 225.54 0.32 ;
      LAYER M2 ;
      RECT 225.34 0.0 225.54 0.32 ;
      LAYER M1 ;
      RECT 225.34 0.0 225.54 0.32 ;
      END
    ANTENNAGATEAREA 0.0072 ;
    ANTENNADIFFAREA 0.054 ;
    END D[13]
  PIN TWEN[18]
    DIRECTION INPUT ;
    USE SIGNAL ;
    SHAPE ABUTMENT ;
    PORT
      LAYER M1 ;
      RECT 380.645 0.0 380.845 0.32 ;
      LAYER M2 ;
      RECT 380.645 0.0 380.845 0.32 ;
      LAYER M3 ;
      RECT 380.645 0.0 380.845 0.32 ;
      LAYER M4 ;
      RECT 380.645 0.0 380.845 0.32 ;
      END
    ANTENNAGATEAREA 0.0072 ;
    ANTENNADIFFAREA 0.054 ;
    END TWEN[18]
  PIN TWEN[13]
    DIRECTION INPUT ;
    USE SIGNAL ;
    SHAPE ABUTMENT ;
    PORT
      LAYER M4 ;
      RECT 224.285 0.0 224.485 0.32 ;
      LAYER M3 ;
      RECT 224.285 0.0 224.485 0.32 ;
      LAYER M2 ;
      RECT 224.285 0.0 224.485 0.32 ;
      LAYER M1 ;
      RECT 224.285 0.0 224.485 0.32 ;
      END
    ANTENNAGATEAREA 0.0072 ;
    ANTENNADIFFAREA 0.054 ;
    END TWEN[13]
  PIN Q[18]
    DIRECTION OUTPUT ;
    USE SIGNAL ;
    SHAPE ABUTMENT ;
    PORT
      LAYER M1 ;
      RECT 381.225 0.0 381.425 0.32 ;
      LAYER M2 ;
      RECT 381.225 0.0 381.425 0.32 ;
      LAYER M3 ;
      RECT 381.225 0.0 381.425 0.32 ;
      END
    ANTENNADIFFAREA 0.054 ;
    END Q[18]
  PIN Q[13]
    DIRECTION OUTPUT ;
    USE SIGNAL ;
    SHAPE ABUTMENT ;
    PORT
      LAYER M3 ;
      RECT 223.705 0.0 223.905 0.32 ;
      LAYER M2 ;
      RECT 223.705 0.0 223.905 0.32 ;
      LAYER M1 ;
      RECT 223.705 0.0 223.905 0.32 ;
      END
    ANTENNADIFFAREA 0.054 ;
    END Q[13]
  PIN WEN[18]
    DIRECTION INPUT ;
    USE SIGNAL ;
    SHAPE ABUTMENT ;
    PORT
      LAYER M4 ;
      RECT 381.69 0.0 381.87 0.32 ;
      LAYER M1 ;
      RECT 381.7 0.0 381.9 0.32 ;
      LAYER M2 ;
      RECT 381.7 0.0 381.9 0.32 ;
      LAYER M3 ;
      RECT 381.7 0.0 381.9 0.32 ;
      END
    ANTENNAGATEAREA 0.0072 ;
    ANTENNADIFFAREA 0.054 ;
    END WEN[18]
  PIN WEN[13]
    DIRECTION INPUT ;
    USE SIGNAL ;
    SHAPE ABUTMENT ;
    PORT
      LAYER M4 ;
      RECT 223.26 0.0 223.44 0.32 ;
      LAYER M3 ;
      RECT 223.23 0.0 223.43 0.32 ;
      LAYER M2 ;
      RECT 223.23 0.0 223.43 0.32 ;
      LAYER M1 ;
      RECT 223.23 0.0 223.43 0.32 ;
      END
    ANTENNAGATEAREA 0.0072 ;
    ANTENNADIFFAREA 0.054 ;
    END WEN[13]
  PIN WENY[18]
    DIRECTION OUTPUT ;
    USE SIGNAL ;
    SHAPE ABUTMENT ;
    PORT
      LAYER M4 ;
      RECT 382.74 0.0 382.92 0.32 ;
      LAYER M3 ;
      RECT 382.755 0.0 382.955 0.32 ;
      END
    ANTENNADIFFAREA 0.054 ;
    END WENY[18]
  PIN WENY[13]
    DIRECTION OUTPUT ;
    USE SIGNAL ;
    SHAPE ABUTMENT ;
    PORT
      LAYER M4 ;
      RECT 222.21 0.0 222.39 0.32 ;
      LAYER M3 ;
      RECT 222.175 0.0 222.375 0.32 ;
      END
    ANTENNADIFFAREA 0.054 ;
    END WENY[13]
  PIN TD[19]
    DIRECTION INPUT ;
    USE SIGNAL ;
    SHAPE ABUTMENT ;
    PORT
      LAYER M1 ;
      RECT 394.09 0.0 394.29 0.32 ;
      LAYER M2 ;
      RECT 394.09 0.0 394.29 0.32 ;
      LAYER M3 ;
      RECT 394.09 0.0 394.29 0.32 ;
      END
    ANTENNAGATEAREA 0.0072 ;
    ANTENNADIFFAREA 0.054 ;
    END TD[19]
  PIN TD[12]
    DIRECTION INPUT ;
    USE SIGNAL ;
    SHAPE ABUTMENT ;
    PORT
      LAYER M3 ;
      RECT 210.84 0.0 211.04 0.32 ;
      LAYER M2 ;
      RECT 210.84 0.0 211.04 0.32 ;
      LAYER M1 ;
      RECT 210.84 0.0 211.04 0.32 ;
      END
    ANTENNAGATEAREA 0.0072 ;
    ANTENNADIFFAREA 0.054 ;
    END TD[12]
  PIN D[19]
    DIRECTION INPUT ;
    USE SIGNAL ;
    SHAPE ABUTMENT ;
    PORT
      LAYER M1 ;
      RECT 396.39 0.0 396.59 0.32 ;
      LAYER M2 ;
      RECT 396.39 0.0 396.59 0.32 ;
      LAYER M3 ;
      RECT 396.39 0.0 396.59 0.32 ;
      LAYER M4 ;
      RECT 396.39 0.0 396.59 0.32 ;
      END
    ANTENNAGATEAREA 0.0072 ;
    ANTENNADIFFAREA 0.054 ;
    END D[19]
  PIN D[12]
    DIRECTION INPUT ;
    USE SIGNAL ;
    SHAPE ABUTMENT ;
    PORT
      LAYER M4 ;
      RECT 208.54 0.0 208.74 0.32 ;
      LAYER M3 ;
      RECT 208.54 0.0 208.74 0.32 ;
      LAYER M2 ;
      RECT 208.54 0.0 208.74 0.32 ;
      LAYER M1 ;
      RECT 208.54 0.0 208.74 0.32 ;
      END
    ANTENNAGATEAREA 0.0072 ;
    ANTENNADIFFAREA 0.054 ;
    END D[12]
  PIN TWEN[19]
    DIRECTION INPUT ;
    USE SIGNAL ;
    SHAPE ABUTMENT ;
    PORT
      LAYER M1 ;
      RECT 397.445 0.0 397.645 0.32 ;
      LAYER M2 ;
      RECT 397.445 0.0 397.645 0.32 ;
      LAYER M3 ;
      RECT 397.445 0.0 397.645 0.32 ;
      LAYER M4 ;
      RECT 397.445 0.0 397.645 0.32 ;
      END
    ANTENNAGATEAREA 0.0072 ;
    ANTENNADIFFAREA 0.054 ;
    END TWEN[19]
  PIN TWEN[12]
    DIRECTION INPUT ;
    USE SIGNAL ;
    SHAPE ABUTMENT ;
    PORT
      LAYER M4 ;
      RECT 207.485 0.0 207.685 0.32 ;
      LAYER M3 ;
      RECT 207.485 0.0 207.685 0.32 ;
      LAYER M2 ;
      RECT 207.485 0.0 207.685 0.32 ;
      LAYER M1 ;
      RECT 207.485 0.0 207.685 0.32 ;
      END
    ANTENNAGATEAREA 0.0072 ;
    ANTENNADIFFAREA 0.054 ;
    END TWEN[12]
  PIN Q[19]
    DIRECTION OUTPUT ;
    USE SIGNAL ;
    SHAPE ABUTMENT ;
    PORT
      LAYER M1 ;
      RECT 398.025 0.0 398.225 0.32 ;
      LAYER M2 ;
      RECT 398.025 0.0 398.225 0.32 ;
      LAYER M3 ;
      RECT 398.025 0.0 398.225 0.32 ;
      END
    ANTENNADIFFAREA 0.054 ;
    END Q[19]
  PIN Q[12]
    DIRECTION OUTPUT ;
    USE SIGNAL ;
    SHAPE ABUTMENT ;
    PORT
      LAYER M3 ;
      RECT 206.905 0.0 207.105 0.32 ;
      LAYER M2 ;
      RECT 206.905 0.0 207.105 0.32 ;
      LAYER M1 ;
      RECT 206.905 0.0 207.105 0.32 ;
      END
    ANTENNADIFFAREA 0.054 ;
    END Q[12]
  PIN WEN[19]
    DIRECTION INPUT ;
    USE SIGNAL ;
    SHAPE ABUTMENT ;
    PORT
      LAYER M4 ;
      RECT 398.49 0.0 398.67 0.32 ;
      LAYER M1 ;
      RECT 398.5 0.0 398.7 0.32 ;
      LAYER M2 ;
      RECT 398.5 0.0 398.7 0.32 ;
      LAYER M3 ;
      RECT 398.5 0.0 398.7 0.32 ;
      END
    ANTENNAGATEAREA 0.0072 ;
    ANTENNADIFFAREA 0.054 ;
    END WEN[19]
  PIN WEN[12]
    DIRECTION INPUT ;
    USE SIGNAL ;
    SHAPE ABUTMENT ;
    PORT
      LAYER M4 ;
      RECT 206.46 0.0 206.64 0.32 ;
      LAYER M3 ;
      RECT 206.43 0.0 206.63 0.32 ;
      LAYER M2 ;
      RECT 206.43 0.0 206.63 0.32 ;
      LAYER M1 ;
      RECT 206.43 0.0 206.63 0.32 ;
      END
    ANTENNAGATEAREA 0.0072 ;
    ANTENNADIFFAREA 0.054 ;
    END WEN[12]
  PIN WENY[19]
    DIRECTION OUTPUT ;
    USE SIGNAL ;
    SHAPE ABUTMENT ;
    PORT
      LAYER M4 ;
      RECT 399.54 0.0 399.72 0.32 ;
      LAYER M3 ;
      RECT 399.555 0.0 399.755 0.32 ;
      END
    ANTENNADIFFAREA 0.054 ;
    END WENY[19]
  PIN WENY[12]
    DIRECTION OUTPUT ;
    USE SIGNAL ;
    SHAPE ABUTMENT ;
    PORT
      LAYER M4 ;
      RECT 205.41 0.0 205.59 0.32 ;
      LAYER M3 ;
      RECT 205.375 0.0 205.575 0.32 ;
      END
    ANTENNADIFFAREA 0.054 ;
    END WENY[12]
  PIN TD[20]
    DIRECTION INPUT ;
    USE SIGNAL ;
    SHAPE ABUTMENT ;
    PORT
      LAYER M1 ;
      RECT 410.89 0.0 411.09 0.32 ;
      LAYER M2 ;
      RECT 410.89 0.0 411.09 0.32 ;
      LAYER M3 ;
      RECT 410.89 0.0 411.09 0.32 ;
      END
    ANTENNAGATEAREA 0.0072 ;
    ANTENNADIFFAREA 0.054 ;
    END TD[20]
  PIN TD[11]
    DIRECTION INPUT ;
    USE SIGNAL ;
    SHAPE ABUTMENT ;
    PORT
      LAYER M3 ;
      RECT 194.04 0.0 194.24 0.32 ;
      LAYER M2 ;
      RECT 194.04 0.0 194.24 0.32 ;
      LAYER M1 ;
      RECT 194.04 0.0 194.24 0.32 ;
      END
    ANTENNAGATEAREA 0.0072 ;
    ANTENNADIFFAREA 0.054 ;
    END TD[11]
  PIN D[20]
    DIRECTION INPUT ;
    USE SIGNAL ;
    SHAPE ABUTMENT ;
    PORT
      LAYER M1 ;
      RECT 413.19 0.0 413.39 0.32 ;
      LAYER M2 ;
      RECT 413.19 0.0 413.39 0.32 ;
      LAYER M3 ;
      RECT 413.19 0.0 413.39 0.32 ;
      LAYER M4 ;
      RECT 413.19 0.0 413.39 0.32 ;
      END
    ANTENNAGATEAREA 0.0072 ;
    ANTENNADIFFAREA 0.054 ;
    END D[20]
  PIN D[11]
    DIRECTION INPUT ;
    USE SIGNAL ;
    SHAPE ABUTMENT ;
    PORT
      LAYER M4 ;
      RECT 191.74 0.0 191.94 0.32 ;
      LAYER M3 ;
      RECT 191.74 0.0 191.94 0.32 ;
      LAYER M2 ;
      RECT 191.74 0.0 191.94 0.32 ;
      LAYER M1 ;
      RECT 191.74 0.0 191.94 0.32 ;
      END
    ANTENNAGATEAREA 0.0072 ;
    ANTENNADIFFAREA 0.054 ;
    END D[11]
  PIN TWEN[20]
    DIRECTION INPUT ;
    USE SIGNAL ;
    SHAPE ABUTMENT ;
    PORT
      LAYER M1 ;
      RECT 414.245 0.0 414.445 0.32 ;
      LAYER M2 ;
      RECT 414.245 0.0 414.445 0.32 ;
      LAYER M3 ;
      RECT 414.245 0.0 414.445 0.32 ;
      LAYER M4 ;
      RECT 414.245 0.0 414.445 0.32 ;
      END
    ANTENNAGATEAREA 0.0072 ;
    ANTENNADIFFAREA 0.054 ;
    END TWEN[20]
  PIN TWEN[11]
    DIRECTION INPUT ;
    USE SIGNAL ;
    SHAPE ABUTMENT ;
    PORT
      LAYER M4 ;
      RECT 190.685 0.0 190.885 0.32 ;
      LAYER M3 ;
      RECT 190.685 0.0 190.885 0.32 ;
      LAYER M2 ;
      RECT 190.685 0.0 190.885 0.32 ;
      LAYER M1 ;
      RECT 190.685 0.0 190.885 0.32 ;
      END
    ANTENNAGATEAREA 0.0072 ;
    ANTENNADIFFAREA 0.054 ;
    END TWEN[11]
  PIN Q[20]
    DIRECTION OUTPUT ;
    USE SIGNAL ;
    SHAPE ABUTMENT ;
    PORT
      LAYER M1 ;
      RECT 414.825 0.0 415.025 0.32 ;
      LAYER M2 ;
      RECT 414.825 0.0 415.025 0.32 ;
      LAYER M3 ;
      RECT 414.825 0.0 415.025 0.32 ;
      END
    ANTENNADIFFAREA 0.054 ;
    END Q[20]
  PIN Q[11]
    DIRECTION OUTPUT ;
    USE SIGNAL ;
    SHAPE ABUTMENT ;
    PORT
      LAYER M3 ;
      RECT 190.105 0.0 190.305 0.32 ;
      LAYER M2 ;
      RECT 190.105 0.0 190.305 0.32 ;
      LAYER M1 ;
      RECT 190.105 0.0 190.305 0.32 ;
      END
    ANTENNADIFFAREA 0.054 ;
    END Q[11]
  PIN WEN[20]
    DIRECTION INPUT ;
    USE SIGNAL ;
    SHAPE ABUTMENT ;
    PORT
      LAYER M4 ;
      RECT 415.29 0.0 415.47 0.32 ;
      LAYER M1 ;
      RECT 415.3 0.0 415.5 0.32 ;
      LAYER M2 ;
      RECT 415.3 0.0 415.5 0.32 ;
      LAYER M3 ;
      RECT 415.3 0.0 415.5 0.32 ;
      END
    ANTENNAGATEAREA 0.0072 ;
    ANTENNADIFFAREA 0.054 ;
    END WEN[20]
  PIN WEN[11]
    DIRECTION INPUT ;
    USE SIGNAL ;
    SHAPE ABUTMENT ;
    PORT
      LAYER M4 ;
      RECT 189.66 0.0 189.84 0.32 ;
      LAYER M3 ;
      RECT 189.63 0.0 189.83 0.32 ;
      LAYER M2 ;
      RECT 189.63 0.0 189.83 0.32 ;
      LAYER M1 ;
      RECT 189.63 0.0 189.83 0.32 ;
      END
    ANTENNAGATEAREA 0.0072 ;
    ANTENNADIFFAREA 0.054 ;
    END WEN[11]
  PIN WENY[20]
    DIRECTION OUTPUT ;
    USE SIGNAL ;
    SHAPE ABUTMENT ;
    PORT
      LAYER M4 ;
      RECT 416.34 0.0 416.52 0.32 ;
      LAYER M3 ;
      RECT 416.355 0.0 416.555 0.32 ;
      END
    ANTENNADIFFAREA 0.054 ;
    END WENY[20]
  PIN WENY[11]
    DIRECTION OUTPUT ;
    USE SIGNAL ;
    SHAPE ABUTMENT ;
    PORT
      LAYER M4 ;
      RECT 188.61 0.0 188.79 0.32 ;
      LAYER M3 ;
      RECT 188.575 0.0 188.775 0.32 ;
      END
    ANTENNADIFFAREA 0.054 ;
    END WENY[11]
  PIN TD[21]
    DIRECTION INPUT ;
    USE SIGNAL ;
    SHAPE ABUTMENT ;
    PORT
      LAYER M1 ;
      RECT 427.69 0.0 427.89 0.32 ;
      LAYER M2 ;
      RECT 427.69 0.0 427.89 0.32 ;
      LAYER M3 ;
      RECT 427.69 0.0 427.89 0.32 ;
      END
    ANTENNAGATEAREA 0.0072 ;
    ANTENNADIFFAREA 0.054 ;
    END TD[21]
  PIN TD[10]
    DIRECTION INPUT ;
    USE SIGNAL ;
    SHAPE ABUTMENT ;
    PORT
      LAYER M3 ;
      RECT 177.24 0.0 177.44 0.32 ;
      LAYER M2 ;
      RECT 177.24 0.0 177.44 0.32 ;
      LAYER M1 ;
      RECT 177.24 0.0 177.44 0.32 ;
      END
    ANTENNAGATEAREA 0.0072 ;
    ANTENNADIFFAREA 0.054 ;
    END TD[10]
  PIN D[21]
    DIRECTION INPUT ;
    USE SIGNAL ;
    SHAPE ABUTMENT ;
    PORT
      LAYER M1 ;
      RECT 429.99 0.0 430.19 0.32 ;
      LAYER M2 ;
      RECT 429.99 0.0 430.19 0.32 ;
      LAYER M3 ;
      RECT 429.99 0.0 430.19 0.32 ;
      LAYER M4 ;
      RECT 429.99 0.0 430.19 0.32 ;
      END
    ANTENNAGATEAREA 0.0072 ;
    ANTENNADIFFAREA 0.054 ;
    END D[21]
  PIN D[10]
    DIRECTION INPUT ;
    USE SIGNAL ;
    SHAPE ABUTMENT ;
    PORT
      LAYER M4 ;
      RECT 174.94 0.0 175.14 0.32 ;
      LAYER M3 ;
      RECT 174.94 0.0 175.14 0.32 ;
      LAYER M2 ;
      RECT 174.94 0.0 175.14 0.32 ;
      LAYER M1 ;
      RECT 174.94 0.0 175.14 0.32 ;
      END
    ANTENNAGATEAREA 0.0072 ;
    ANTENNADIFFAREA 0.054 ;
    END D[10]
  PIN TWEN[21]
    DIRECTION INPUT ;
    USE SIGNAL ;
    SHAPE ABUTMENT ;
    PORT
      LAYER M1 ;
      RECT 431.045 0.0 431.245 0.32 ;
      LAYER M2 ;
      RECT 431.045 0.0 431.245 0.32 ;
      LAYER M3 ;
      RECT 431.045 0.0 431.245 0.32 ;
      LAYER M4 ;
      RECT 431.045 0.0 431.245 0.32 ;
      END
    ANTENNAGATEAREA 0.0072 ;
    ANTENNADIFFAREA 0.054 ;
    END TWEN[21]
  PIN TWEN[10]
    DIRECTION INPUT ;
    USE SIGNAL ;
    SHAPE ABUTMENT ;
    PORT
      LAYER M4 ;
      RECT 173.885 0.0 174.085 0.32 ;
      LAYER M3 ;
      RECT 173.885 0.0 174.085 0.32 ;
      LAYER M2 ;
      RECT 173.885 0.0 174.085 0.32 ;
      LAYER M1 ;
      RECT 173.885 0.0 174.085 0.32 ;
      END
    ANTENNAGATEAREA 0.0072 ;
    ANTENNADIFFAREA 0.054 ;
    END TWEN[10]
  PIN Q[21]
    DIRECTION OUTPUT ;
    USE SIGNAL ;
    SHAPE ABUTMENT ;
    PORT
      LAYER M1 ;
      RECT 431.625 0.0 431.825 0.32 ;
      LAYER M2 ;
      RECT 431.625 0.0 431.825 0.32 ;
      LAYER M3 ;
      RECT 431.625 0.0 431.825 0.32 ;
      END
    ANTENNADIFFAREA 0.054 ;
    END Q[21]
  PIN Q[10]
    DIRECTION OUTPUT ;
    USE SIGNAL ;
    SHAPE ABUTMENT ;
    PORT
      LAYER M3 ;
      RECT 173.305 0.0 173.505 0.32 ;
      LAYER M2 ;
      RECT 173.305 0.0 173.505 0.32 ;
      LAYER M1 ;
      RECT 173.305 0.0 173.505 0.32 ;
      END
    ANTENNADIFFAREA 0.054 ;
    END Q[10]
  PIN WEN[21]
    DIRECTION INPUT ;
    USE SIGNAL ;
    SHAPE ABUTMENT ;
    PORT
      LAYER M4 ;
      RECT 432.09 0.0 432.27 0.32 ;
      LAYER M1 ;
      RECT 432.1 0.0 432.3 0.32 ;
      LAYER M2 ;
      RECT 432.1 0.0 432.3 0.32 ;
      LAYER M3 ;
      RECT 432.1 0.0 432.3 0.32 ;
      END
    ANTENNAGATEAREA 0.0072 ;
    ANTENNADIFFAREA 0.054 ;
    END WEN[21]
  PIN WEN[10]
    DIRECTION INPUT ;
    USE SIGNAL ;
    SHAPE ABUTMENT ;
    PORT
      LAYER M4 ;
      RECT 172.86 0.0 173.04 0.32 ;
      LAYER M3 ;
      RECT 172.83 0.0 173.03 0.32 ;
      LAYER M2 ;
      RECT 172.83 0.0 173.03 0.32 ;
      LAYER M1 ;
      RECT 172.83 0.0 173.03 0.32 ;
      END
    ANTENNAGATEAREA 0.0072 ;
    ANTENNADIFFAREA 0.054 ;
    END WEN[10]
  PIN WENY[21]
    DIRECTION OUTPUT ;
    USE SIGNAL ;
    SHAPE ABUTMENT ;
    PORT
      LAYER M4 ;
      RECT 433.14 0.0 433.32 0.32 ;
      LAYER M3 ;
      RECT 433.155 0.0 433.355 0.32 ;
      END
    ANTENNADIFFAREA 0.054 ;
    END WENY[21]
  PIN WENY[10]
    DIRECTION OUTPUT ;
    USE SIGNAL ;
    SHAPE ABUTMENT ;
    PORT
      LAYER M4 ;
      RECT 171.81 0.0 171.99 0.32 ;
      LAYER M3 ;
      RECT 171.775 0.0 171.975 0.32 ;
      END
    ANTENNADIFFAREA 0.054 ;
    END WENY[10]
  PIN TD[22]
    DIRECTION INPUT ;
    USE SIGNAL ;
    SHAPE ABUTMENT ;
    PORT
      LAYER M1 ;
      RECT 444.49 0.0 444.69 0.32 ;
      LAYER M2 ;
      RECT 444.49 0.0 444.69 0.32 ;
      LAYER M3 ;
      RECT 444.49 0.0 444.69 0.32 ;
      END
    ANTENNAGATEAREA 0.0072 ;
    ANTENNADIFFAREA 0.054 ;
    END TD[22]
  PIN TD[9]
    DIRECTION INPUT ;
    USE SIGNAL ;
    SHAPE ABUTMENT ;
    PORT
      LAYER M3 ;
      RECT 160.44 0.0 160.64 0.32 ;
      LAYER M2 ;
      RECT 160.44 0.0 160.64 0.32 ;
      LAYER M1 ;
      RECT 160.44 0.0 160.64 0.32 ;
      END
    ANTENNAGATEAREA 0.0072 ;
    ANTENNADIFFAREA 0.054 ;
    END TD[9]
  PIN D[22]
    DIRECTION INPUT ;
    USE SIGNAL ;
    SHAPE ABUTMENT ;
    PORT
      LAYER M1 ;
      RECT 446.79 0.0 446.99 0.32 ;
      LAYER M2 ;
      RECT 446.79 0.0 446.99 0.32 ;
      LAYER M3 ;
      RECT 446.79 0.0 446.99 0.32 ;
      LAYER M4 ;
      RECT 446.79 0.0 446.99 0.32 ;
      END
    ANTENNAGATEAREA 0.0072 ;
    ANTENNADIFFAREA 0.054 ;
    END D[22]
  PIN D[9]
    DIRECTION INPUT ;
    USE SIGNAL ;
    SHAPE ABUTMENT ;
    PORT
      LAYER M4 ;
      RECT 158.14 0.0 158.34 0.32 ;
      LAYER M3 ;
      RECT 158.14 0.0 158.34 0.32 ;
      LAYER M2 ;
      RECT 158.14 0.0 158.34 0.32 ;
      LAYER M1 ;
      RECT 158.14 0.0 158.34 0.32 ;
      END
    ANTENNAGATEAREA 0.0072 ;
    ANTENNADIFFAREA 0.054 ;
    END D[9]
  PIN TWEN[22]
    DIRECTION INPUT ;
    USE SIGNAL ;
    SHAPE ABUTMENT ;
    PORT
      LAYER M1 ;
      RECT 447.845 0.0 448.045 0.32 ;
      LAYER M2 ;
      RECT 447.845 0.0 448.045 0.32 ;
      LAYER M3 ;
      RECT 447.845 0.0 448.045 0.32 ;
      LAYER M4 ;
      RECT 447.845 0.0 448.045 0.32 ;
      END
    ANTENNAGATEAREA 0.0072 ;
    ANTENNADIFFAREA 0.054 ;
    END TWEN[22]
  PIN TWEN[9]
    DIRECTION INPUT ;
    USE SIGNAL ;
    SHAPE ABUTMENT ;
    PORT
      LAYER M4 ;
      RECT 157.085 0.0 157.285 0.32 ;
      LAYER M3 ;
      RECT 157.085 0.0 157.285 0.32 ;
      LAYER M2 ;
      RECT 157.085 0.0 157.285 0.32 ;
      LAYER M1 ;
      RECT 157.085 0.0 157.285 0.32 ;
      END
    ANTENNAGATEAREA 0.0072 ;
    ANTENNADIFFAREA 0.054 ;
    END TWEN[9]
  PIN Q[22]
    DIRECTION OUTPUT ;
    USE SIGNAL ;
    SHAPE ABUTMENT ;
    PORT
      LAYER M1 ;
      RECT 448.425 0.0 448.625 0.32 ;
      LAYER M2 ;
      RECT 448.425 0.0 448.625 0.32 ;
      LAYER M3 ;
      RECT 448.425 0.0 448.625 0.32 ;
      END
    ANTENNADIFFAREA 0.054 ;
    END Q[22]
  PIN Q[9]
    DIRECTION OUTPUT ;
    USE SIGNAL ;
    SHAPE ABUTMENT ;
    PORT
      LAYER M3 ;
      RECT 156.505 0.0 156.705 0.32 ;
      LAYER M2 ;
      RECT 156.505 0.0 156.705 0.32 ;
      LAYER M1 ;
      RECT 156.505 0.0 156.705 0.32 ;
      END
    ANTENNADIFFAREA 0.054 ;
    END Q[9]
  PIN WEN[22]
    DIRECTION INPUT ;
    USE SIGNAL ;
    SHAPE ABUTMENT ;
    PORT
      LAYER M4 ;
      RECT 448.89 0.0 449.07 0.32 ;
      LAYER M1 ;
      RECT 448.9 0.0 449.1 0.32 ;
      LAYER M2 ;
      RECT 448.9 0.0 449.1 0.32 ;
      LAYER M3 ;
      RECT 448.9 0.0 449.1 0.32 ;
      END
    ANTENNAGATEAREA 0.0072 ;
    ANTENNADIFFAREA 0.054 ;
    END WEN[22]
  PIN WEN[9]
    DIRECTION INPUT ;
    USE SIGNAL ;
    SHAPE ABUTMENT ;
    PORT
      LAYER M4 ;
      RECT 156.06 0.0 156.24 0.32 ;
      LAYER M3 ;
      RECT 156.03 0.0 156.23 0.32 ;
      LAYER M2 ;
      RECT 156.03 0.0 156.23 0.32 ;
      LAYER M1 ;
      RECT 156.03 0.0 156.23 0.32 ;
      END
    ANTENNAGATEAREA 0.0072 ;
    ANTENNADIFFAREA 0.054 ;
    END WEN[9]
  PIN WENY[22]
    DIRECTION OUTPUT ;
    USE SIGNAL ;
    SHAPE ABUTMENT ;
    PORT
      LAYER M4 ;
      RECT 449.94 0.0 450.12 0.32 ;
      LAYER M3 ;
      RECT 449.955 0.0 450.155 0.32 ;
      END
    ANTENNADIFFAREA 0.054 ;
    END WENY[22]
  PIN WENY[9]
    DIRECTION OUTPUT ;
    USE SIGNAL ;
    SHAPE ABUTMENT ;
    PORT
      LAYER M4 ;
      RECT 155.01 0.0 155.19 0.32 ;
      LAYER M3 ;
      RECT 154.975 0.0 155.175 0.32 ;
      END
    ANTENNADIFFAREA 0.054 ;
    END WENY[9]
  PIN TD[23]
    DIRECTION INPUT ;
    USE SIGNAL ;
    SHAPE ABUTMENT ;
    PORT
      LAYER M1 ;
      RECT 461.29 0.0 461.49 0.32 ;
      LAYER M2 ;
      RECT 461.29 0.0 461.49 0.32 ;
      LAYER M3 ;
      RECT 461.29 0.0 461.49 0.32 ;
      END
    ANTENNAGATEAREA 0.0072 ;
    ANTENNADIFFAREA 0.054 ;
    END TD[23]
  PIN TD[8]
    DIRECTION INPUT ;
    USE SIGNAL ;
    SHAPE ABUTMENT ;
    PORT
      LAYER M3 ;
      RECT 143.64 0.0 143.84 0.32 ;
      LAYER M2 ;
      RECT 143.64 0.0 143.84 0.32 ;
      LAYER M1 ;
      RECT 143.64 0.0 143.84 0.32 ;
      END
    ANTENNAGATEAREA 0.0072 ;
    ANTENNADIFFAREA 0.054 ;
    END TD[8]
  PIN D[23]
    DIRECTION INPUT ;
    USE SIGNAL ;
    SHAPE ABUTMENT ;
    PORT
      LAYER M1 ;
      RECT 463.59 0.0 463.79 0.32 ;
      LAYER M2 ;
      RECT 463.59 0.0 463.79 0.32 ;
      LAYER M3 ;
      RECT 463.59 0.0 463.79 0.32 ;
      LAYER M4 ;
      RECT 463.59 0.0 463.79 0.32 ;
      END
    ANTENNAGATEAREA 0.0072 ;
    ANTENNADIFFAREA 0.054 ;
    END D[23]
  PIN D[8]
    DIRECTION INPUT ;
    USE SIGNAL ;
    SHAPE ABUTMENT ;
    PORT
      LAYER M4 ;
      RECT 141.34 0.0 141.54 0.32 ;
      LAYER M3 ;
      RECT 141.34 0.0 141.54 0.32 ;
      LAYER M2 ;
      RECT 141.34 0.0 141.54 0.32 ;
      LAYER M1 ;
      RECT 141.34 0.0 141.54 0.32 ;
      END
    ANTENNAGATEAREA 0.0072 ;
    ANTENNADIFFAREA 0.054 ;
    END D[8]
  PIN TWEN[23]
    DIRECTION INPUT ;
    USE SIGNAL ;
    SHAPE ABUTMENT ;
    PORT
      LAYER M1 ;
      RECT 464.645 0.0 464.845 0.32 ;
      LAYER M2 ;
      RECT 464.645 0.0 464.845 0.32 ;
      LAYER M3 ;
      RECT 464.645 0.0 464.845 0.32 ;
      LAYER M4 ;
      RECT 464.645 0.0 464.845 0.32 ;
      END
    ANTENNAGATEAREA 0.0072 ;
    ANTENNADIFFAREA 0.054 ;
    END TWEN[23]
  PIN TWEN[8]
    DIRECTION INPUT ;
    USE SIGNAL ;
    SHAPE ABUTMENT ;
    PORT
      LAYER M4 ;
      RECT 140.285 0.0 140.485 0.32 ;
      LAYER M3 ;
      RECT 140.285 0.0 140.485 0.32 ;
      LAYER M2 ;
      RECT 140.285 0.0 140.485 0.32 ;
      LAYER M1 ;
      RECT 140.285 0.0 140.485 0.32 ;
      END
    ANTENNAGATEAREA 0.0072 ;
    ANTENNADIFFAREA 0.054 ;
    END TWEN[8]
  PIN Q[23]
    DIRECTION OUTPUT ;
    USE SIGNAL ;
    SHAPE ABUTMENT ;
    PORT
      LAYER M1 ;
      RECT 465.225 0.0 465.425 0.32 ;
      LAYER M2 ;
      RECT 465.225 0.0 465.425 0.32 ;
      LAYER M3 ;
      RECT 465.225 0.0 465.425 0.32 ;
      END
    ANTENNADIFFAREA 0.054 ;
    END Q[23]
  PIN Q[8]
    DIRECTION OUTPUT ;
    USE SIGNAL ;
    SHAPE ABUTMENT ;
    PORT
      LAYER M3 ;
      RECT 139.705 0.0 139.905 0.32 ;
      LAYER M2 ;
      RECT 139.705 0.0 139.905 0.32 ;
      LAYER M1 ;
      RECT 139.705 0.0 139.905 0.32 ;
      END
    ANTENNADIFFAREA 0.054 ;
    END Q[8]
  PIN WEN[23]
    DIRECTION INPUT ;
    USE SIGNAL ;
    SHAPE ABUTMENT ;
    PORT
      LAYER M4 ;
      RECT 465.69 0.0 465.87 0.32 ;
      LAYER M1 ;
      RECT 465.7 0.0 465.9 0.32 ;
      LAYER M2 ;
      RECT 465.7 0.0 465.9 0.32 ;
      LAYER M3 ;
      RECT 465.7 0.0 465.9 0.32 ;
      END
    ANTENNAGATEAREA 0.0072 ;
    ANTENNADIFFAREA 0.054 ;
    END WEN[23]
  PIN WEN[8]
    DIRECTION INPUT ;
    USE SIGNAL ;
    SHAPE ABUTMENT ;
    PORT
      LAYER M4 ;
      RECT 139.26 0.0 139.44 0.32 ;
      LAYER M3 ;
      RECT 139.23 0.0 139.43 0.32 ;
      LAYER M2 ;
      RECT 139.23 0.0 139.43 0.32 ;
      LAYER M1 ;
      RECT 139.23 0.0 139.43 0.32 ;
      END
    ANTENNAGATEAREA 0.0072 ;
    ANTENNADIFFAREA 0.054 ;
    END WEN[8]
  PIN WENY[23]
    DIRECTION OUTPUT ;
    USE SIGNAL ;
    SHAPE ABUTMENT ;
    PORT
      LAYER M4 ;
      RECT 466.74 0.0 466.92 0.32 ;
      LAYER M3 ;
      RECT 466.755 0.0 466.955 0.32 ;
      END
    ANTENNADIFFAREA 0.054 ;
    END WENY[23]
  PIN WENY[8]
    DIRECTION OUTPUT ;
    USE SIGNAL ;
    SHAPE ABUTMENT ;
    PORT
      LAYER M4 ;
      RECT 138.21 0.0 138.39 0.32 ;
      LAYER M3 ;
      RECT 138.175 0.0 138.375 0.32 ;
      END
    ANTENNADIFFAREA 0.054 ;
    END WENY[8]
  PIN TD[24]
    DIRECTION INPUT ;
    USE SIGNAL ;
    SHAPE ABUTMENT ;
    PORT
      LAYER M1 ;
      RECT 478.09 0.0 478.29 0.32 ;
      LAYER M2 ;
      RECT 478.09 0.0 478.29 0.32 ;
      LAYER M3 ;
      RECT 478.09 0.0 478.29 0.32 ;
      END
    ANTENNAGATEAREA 0.0072 ;
    ANTENNADIFFAREA 0.054 ;
    END TD[24]
  PIN TD[7]
    DIRECTION INPUT ;
    USE SIGNAL ;
    SHAPE ABUTMENT ;
    PORT
      LAYER M3 ;
      RECT 126.84 0.0 127.04 0.32 ;
      LAYER M2 ;
      RECT 126.84 0.0 127.04 0.32 ;
      LAYER M1 ;
      RECT 126.84 0.0 127.04 0.32 ;
      END
    ANTENNAGATEAREA 0.0072 ;
    ANTENNADIFFAREA 0.054 ;
    END TD[7]
  PIN D[24]
    DIRECTION INPUT ;
    USE SIGNAL ;
    SHAPE ABUTMENT ;
    PORT
      LAYER M1 ;
      RECT 480.39 0.0 480.59 0.32 ;
      LAYER M2 ;
      RECT 480.39 0.0 480.59 0.32 ;
      LAYER M3 ;
      RECT 480.39 0.0 480.59 0.32 ;
      LAYER M4 ;
      RECT 480.39 0.0 480.59 0.32 ;
      END
    ANTENNAGATEAREA 0.0072 ;
    ANTENNADIFFAREA 0.054 ;
    END D[24]
  PIN D[7]
    DIRECTION INPUT ;
    USE SIGNAL ;
    SHAPE ABUTMENT ;
    PORT
      LAYER M4 ;
      RECT 124.54 0.0 124.74 0.32 ;
      LAYER M3 ;
      RECT 124.54 0.0 124.74 0.32 ;
      LAYER M2 ;
      RECT 124.54 0.0 124.74 0.32 ;
      LAYER M1 ;
      RECT 124.54 0.0 124.74 0.32 ;
      END
    ANTENNAGATEAREA 0.0072 ;
    ANTENNADIFFAREA 0.054 ;
    END D[7]
  PIN TWEN[24]
    DIRECTION INPUT ;
    USE SIGNAL ;
    SHAPE ABUTMENT ;
    PORT
      LAYER M1 ;
      RECT 481.445 0.0 481.645 0.32 ;
      LAYER M2 ;
      RECT 481.445 0.0 481.645 0.32 ;
      LAYER M3 ;
      RECT 481.445 0.0 481.645 0.32 ;
      LAYER M4 ;
      RECT 481.445 0.0 481.645 0.32 ;
      END
    ANTENNAGATEAREA 0.0072 ;
    ANTENNADIFFAREA 0.054 ;
    END TWEN[24]
  PIN TWEN[7]
    DIRECTION INPUT ;
    USE SIGNAL ;
    SHAPE ABUTMENT ;
    PORT
      LAYER M4 ;
      RECT 123.485 0.0 123.685 0.32 ;
      LAYER M3 ;
      RECT 123.485 0.0 123.685 0.32 ;
      LAYER M2 ;
      RECT 123.485 0.0 123.685 0.32 ;
      LAYER M1 ;
      RECT 123.485 0.0 123.685 0.32 ;
      END
    ANTENNAGATEAREA 0.0072 ;
    ANTENNADIFFAREA 0.054 ;
    END TWEN[7]
  PIN Q[24]
    DIRECTION OUTPUT ;
    USE SIGNAL ;
    SHAPE ABUTMENT ;
    PORT
      LAYER M1 ;
      RECT 482.025 0.0 482.225 0.32 ;
      LAYER M2 ;
      RECT 482.025 0.0 482.225 0.32 ;
      LAYER M3 ;
      RECT 482.025 0.0 482.225 0.32 ;
      END
    ANTENNADIFFAREA 0.054 ;
    END Q[24]
  PIN Q[7]
    DIRECTION OUTPUT ;
    USE SIGNAL ;
    SHAPE ABUTMENT ;
    PORT
      LAYER M3 ;
      RECT 122.905 0.0 123.105 0.32 ;
      LAYER M2 ;
      RECT 122.905 0.0 123.105 0.32 ;
      LAYER M1 ;
      RECT 122.905 0.0 123.105 0.32 ;
      END
    ANTENNADIFFAREA 0.054 ;
    END Q[7]
  PIN WEN[24]
    DIRECTION INPUT ;
    USE SIGNAL ;
    SHAPE ABUTMENT ;
    PORT
      LAYER M4 ;
      RECT 482.49 0.0 482.67 0.32 ;
      LAYER M1 ;
      RECT 482.5 0.0 482.7 0.32 ;
      LAYER M2 ;
      RECT 482.5 0.0 482.7 0.32 ;
      LAYER M3 ;
      RECT 482.5 0.0 482.7 0.32 ;
      END
    ANTENNAGATEAREA 0.0072 ;
    ANTENNADIFFAREA 0.054 ;
    END WEN[24]
  PIN WEN[7]
    DIRECTION INPUT ;
    USE SIGNAL ;
    SHAPE ABUTMENT ;
    PORT
      LAYER M4 ;
      RECT 122.46 0.0 122.64 0.32 ;
      LAYER M3 ;
      RECT 122.43 0.0 122.63 0.32 ;
      LAYER M2 ;
      RECT 122.43 0.0 122.63 0.32 ;
      LAYER M1 ;
      RECT 122.43 0.0 122.63 0.32 ;
      END
    ANTENNAGATEAREA 0.0072 ;
    ANTENNADIFFAREA 0.054 ;
    END WEN[7]
  PIN WENY[24]
    DIRECTION OUTPUT ;
    USE SIGNAL ;
    SHAPE ABUTMENT ;
    PORT
      LAYER M4 ;
      RECT 483.54 0.0 483.72 0.32 ;
      LAYER M3 ;
      RECT 483.555 0.0 483.755 0.32 ;
      END
    ANTENNADIFFAREA 0.054 ;
    END WENY[24]
  PIN WENY[7]
    DIRECTION OUTPUT ;
    USE SIGNAL ;
    SHAPE ABUTMENT ;
    PORT
      LAYER M4 ;
      RECT 121.41 0.0 121.59 0.32 ;
      LAYER M3 ;
      RECT 121.375 0.0 121.575 0.32 ;
      END
    ANTENNADIFFAREA 0.054 ;
    END WENY[7]
  PIN TD[25]
    DIRECTION INPUT ;
    USE SIGNAL ;
    SHAPE ABUTMENT ;
    PORT
      LAYER M1 ;
      RECT 494.89 0.0 495.09 0.32 ;
      LAYER M2 ;
      RECT 494.89 0.0 495.09 0.32 ;
      LAYER M3 ;
      RECT 494.89 0.0 495.09 0.32 ;
      END
    ANTENNAGATEAREA 0.0072 ;
    ANTENNADIFFAREA 0.054 ;
    END TD[25]
  PIN TD[6]
    DIRECTION INPUT ;
    USE SIGNAL ;
    SHAPE ABUTMENT ;
    PORT
      LAYER M3 ;
      RECT 110.04 0.0 110.24 0.32 ;
      LAYER M2 ;
      RECT 110.04 0.0 110.24 0.32 ;
      LAYER M1 ;
      RECT 110.04 0.0 110.24 0.32 ;
      END
    ANTENNAGATEAREA 0.0072 ;
    ANTENNADIFFAREA 0.054 ;
    END TD[6]
  PIN D[25]
    DIRECTION INPUT ;
    USE SIGNAL ;
    SHAPE ABUTMENT ;
    PORT
      LAYER M1 ;
      RECT 497.19 0.0 497.39 0.32 ;
      LAYER M2 ;
      RECT 497.19 0.0 497.39 0.32 ;
      LAYER M3 ;
      RECT 497.19 0.0 497.39 0.32 ;
      LAYER M4 ;
      RECT 497.19 0.0 497.39 0.32 ;
      END
    ANTENNAGATEAREA 0.0072 ;
    ANTENNADIFFAREA 0.054 ;
    END D[25]
  PIN D[6]
    DIRECTION INPUT ;
    USE SIGNAL ;
    SHAPE ABUTMENT ;
    PORT
      LAYER M4 ;
      RECT 107.74 0.0 107.94 0.32 ;
      LAYER M3 ;
      RECT 107.74 0.0 107.94 0.32 ;
      LAYER M2 ;
      RECT 107.74 0.0 107.94 0.32 ;
      LAYER M1 ;
      RECT 107.74 0.0 107.94 0.32 ;
      END
    ANTENNAGATEAREA 0.0072 ;
    ANTENNADIFFAREA 0.054 ;
    END D[6]
  PIN TWEN[25]
    DIRECTION INPUT ;
    USE SIGNAL ;
    SHAPE ABUTMENT ;
    PORT
      LAYER M1 ;
      RECT 498.245 0.0 498.445 0.32 ;
      LAYER M2 ;
      RECT 498.245 0.0 498.445 0.32 ;
      LAYER M3 ;
      RECT 498.245 0.0 498.445 0.32 ;
      LAYER M4 ;
      RECT 498.245 0.0 498.445 0.32 ;
      END
    ANTENNAGATEAREA 0.0072 ;
    ANTENNADIFFAREA 0.054 ;
    END TWEN[25]
  PIN TWEN[6]
    DIRECTION INPUT ;
    USE SIGNAL ;
    SHAPE ABUTMENT ;
    PORT
      LAYER M4 ;
      RECT 106.685 0.0 106.885 0.32 ;
      LAYER M3 ;
      RECT 106.685 0.0 106.885 0.32 ;
      LAYER M2 ;
      RECT 106.685 0.0 106.885 0.32 ;
      LAYER M1 ;
      RECT 106.685 0.0 106.885 0.32 ;
      END
    ANTENNAGATEAREA 0.0072 ;
    ANTENNADIFFAREA 0.054 ;
    END TWEN[6]
  PIN Q[25]
    DIRECTION OUTPUT ;
    USE SIGNAL ;
    SHAPE ABUTMENT ;
    PORT
      LAYER M1 ;
      RECT 498.825 0.0 499.025 0.32 ;
      LAYER M2 ;
      RECT 498.825 0.0 499.025 0.32 ;
      LAYER M3 ;
      RECT 498.825 0.0 499.025 0.32 ;
      END
    ANTENNADIFFAREA 0.054 ;
    END Q[25]
  PIN Q[6]
    DIRECTION OUTPUT ;
    USE SIGNAL ;
    SHAPE ABUTMENT ;
    PORT
      LAYER M3 ;
      RECT 106.105 0.0 106.305 0.32 ;
      LAYER M2 ;
      RECT 106.105 0.0 106.305 0.32 ;
      LAYER M1 ;
      RECT 106.105 0.0 106.305 0.32 ;
      END
    ANTENNADIFFAREA 0.054 ;
    END Q[6]
  PIN WEN[25]
    DIRECTION INPUT ;
    USE SIGNAL ;
    SHAPE ABUTMENT ;
    PORT
      LAYER M4 ;
      RECT 499.29 0.0 499.47 0.32 ;
      LAYER M1 ;
      RECT 499.3 0.0 499.5 0.32 ;
      LAYER M2 ;
      RECT 499.3 0.0 499.5 0.32 ;
      LAYER M3 ;
      RECT 499.3 0.0 499.5 0.32 ;
      END
    ANTENNAGATEAREA 0.0072 ;
    ANTENNADIFFAREA 0.054 ;
    END WEN[25]
  PIN WEN[6]
    DIRECTION INPUT ;
    USE SIGNAL ;
    SHAPE ABUTMENT ;
    PORT
      LAYER M4 ;
      RECT 105.66 0.0 105.84 0.32 ;
      LAYER M3 ;
      RECT 105.63 0.0 105.83 0.32 ;
      LAYER M2 ;
      RECT 105.63 0.0 105.83 0.32 ;
      LAYER M1 ;
      RECT 105.63 0.0 105.83 0.32 ;
      END
    ANTENNAGATEAREA 0.0072 ;
    ANTENNADIFFAREA 0.054 ;
    END WEN[6]
  PIN WENY[25]
    DIRECTION OUTPUT ;
    USE SIGNAL ;
    SHAPE ABUTMENT ;
    PORT
      LAYER M4 ;
      RECT 500.34 0.0 500.52 0.32 ;
      LAYER M3 ;
      RECT 500.355 0.0 500.555 0.32 ;
      END
    ANTENNADIFFAREA 0.054 ;
    END WENY[25]
  PIN WENY[6]
    DIRECTION OUTPUT ;
    USE SIGNAL ;
    SHAPE ABUTMENT ;
    PORT
      LAYER M4 ;
      RECT 104.61 0.0 104.79 0.32 ;
      LAYER M3 ;
      RECT 104.575 0.0 104.775 0.32 ;
      END
    ANTENNADIFFAREA 0.054 ;
    END WENY[6]
  PIN TD[26]
    DIRECTION INPUT ;
    USE SIGNAL ;
    SHAPE ABUTMENT ;
    PORT
      LAYER M1 ;
      RECT 511.69 0.0 511.89 0.32 ;
      LAYER M2 ;
      RECT 511.69 0.0 511.89 0.32 ;
      LAYER M3 ;
      RECT 511.69 0.0 511.89 0.32 ;
      END
    ANTENNAGATEAREA 0.0072 ;
    ANTENNADIFFAREA 0.054 ;
    END TD[26]
  PIN TD[5]
    DIRECTION INPUT ;
    USE SIGNAL ;
    SHAPE ABUTMENT ;
    PORT
      LAYER M3 ;
      RECT 93.24 0.0 93.44 0.32 ;
      LAYER M2 ;
      RECT 93.24 0.0 93.44 0.32 ;
      LAYER M1 ;
      RECT 93.24 0.0 93.44 0.32 ;
      END
    ANTENNAGATEAREA 0.0072 ;
    ANTENNADIFFAREA 0.054 ;
    END TD[5]
  PIN D[26]
    DIRECTION INPUT ;
    USE SIGNAL ;
    SHAPE ABUTMENT ;
    PORT
      LAYER M1 ;
      RECT 513.99 0.0 514.19 0.32 ;
      LAYER M2 ;
      RECT 513.99 0.0 514.19 0.32 ;
      LAYER M3 ;
      RECT 513.99 0.0 514.19 0.32 ;
      LAYER M4 ;
      RECT 513.99 0.0 514.19 0.32 ;
      END
    ANTENNAGATEAREA 0.0072 ;
    ANTENNADIFFAREA 0.054 ;
    END D[26]
  PIN D[5]
    DIRECTION INPUT ;
    USE SIGNAL ;
    SHAPE ABUTMENT ;
    PORT
      LAYER M4 ;
      RECT 90.94 0.0 91.14 0.32 ;
      LAYER M3 ;
      RECT 90.94 0.0 91.14 0.32 ;
      LAYER M2 ;
      RECT 90.94 0.0 91.14 0.32 ;
      LAYER M1 ;
      RECT 90.94 0.0 91.14 0.32 ;
      END
    ANTENNAGATEAREA 0.0072 ;
    ANTENNADIFFAREA 0.054 ;
    END D[5]
  PIN TWEN[26]
    DIRECTION INPUT ;
    USE SIGNAL ;
    SHAPE ABUTMENT ;
    PORT
      LAYER M1 ;
      RECT 515.045 0.0 515.245 0.32 ;
      LAYER M2 ;
      RECT 515.045 0.0 515.245 0.32 ;
      LAYER M3 ;
      RECT 515.045 0.0 515.245 0.32 ;
      LAYER M4 ;
      RECT 515.045 0.0 515.245 0.32 ;
      END
    ANTENNAGATEAREA 0.0072 ;
    ANTENNADIFFAREA 0.054 ;
    END TWEN[26]
  PIN TWEN[5]
    DIRECTION INPUT ;
    USE SIGNAL ;
    SHAPE ABUTMENT ;
    PORT
      LAYER M4 ;
      RECT 89.885 0.0 90.085 0.32 ;
      LAYER M3 ;
      RECT 89.885 0.0 90.085 0.32 ;
      LAYER M2 ;
      RECT 89.885 0.0 90.085 0.32 ;
      LAYER M1 ;
      RECT 89.885 0.0 90.085 0.32 ;
      END
    ANTENNAGATEAREA 0.0072 ;
    ANTENNADIFFAREA 0.054 ;
    END TWEN[5]
  PIN Q[26]
    DIRECTION OUTPUT ;
    USE SIGNAL ;
    SHAPE ABUTMENT ;
    PORT
      LAYER M1 ;
      RECT 515.625 0.0 515.825 0.32 ;
      LAYER M2 ;
      RECT 515.625 0.0 515.825 0.32 ;
      LAYER M3 ;
      RECT 515.625 0.0 515.825 0.32 ;
      END
    ANTENNADIFFAREA 0.054 ;
    END Q[26]
  PIN Q[5]
    DIRECTION OUTPUT ;
    USE SIGNAL ;
    SHAPE ABUTMENT ;
    PORT
      LAYER M3 ;
      RECT 89.305 0.0 89.505 0.32 ;
      LAYER M2 ;
      RECT 89.305 0.0 89.505 0.32 ;
      LAYER M1 ;
      RECT 89.305 0.0 89.505 0.32 ;
      END
    ANTENNADIFFAREA 0.054 ;
    END Q[5]
  PIN WEN[26]
    DIRECTION INPUT ;
    USE SIGNAL ;
    SHAPE ABUTMENT ;
    PORT
      LAYER M4 ;
      RECT 516.09 0.0 516.27 0.32 ;
      LAYER M1 ;
      RECT 516.1 0.0 516.3 0.32 ;
      LAYER M2 ;
      RECT 516.1 0.0 516.3 0.32 ;
      LAYER M3 ;
      RECT 516.1 0.0 516.3 0.32 ;
      END
    ANTENNAGATEAREA 0.0072 ;
    ANTENNADIFFAREA 0.054 ;
    END WEN[26]
  PIN WEN[5]
    DIRECTION INPUT ;
    USE SIGNAL ;
    SHAPE ABUTMENT ;
    PORT
      LAYER M4 ;
      RECT 88.86 0.0 89.04 0.32 ;
      LAYER M3 ;
      RECT 88.83 0.0 89.03 0.32 ;
      LAYER M2 ;
      RECT 88.83 0.0 89.03 0.32 ;
      LAYER M1 ;
      RECT 88.83 0.0 89.03 0.32 ;
      END
    ANTENNAGATEAREA 0.0072 ;
    ANTENNADIFFAREA 0.054 ;
    END WEN[5]
  PIN WENY[26]
    DIRECTION OUTPUT ;
    USE SIGNAL ;
    SHAPE ABUTMENT ;
    PORT
      LAYER M4 ;
      RECT 517.14 0.0 517.32 0.32 ;
      LAYER M3 ;
      RECT 517.155 0.0 517.355 0.32 ;
      END
    ANTENNADIFFAREA 0.054 ;
    END WENY[26]
  PIN WENY[5]
    DIRECTION OUTPUT ;
    USE SIGNAL ;
    SHAPE ABUTMENT ;
    PORT
      LAYER M4 ;
      RECT 87.81 0.0 87.99 0.32 ;
      LAYER M3 ;
      RECT 87.775 0.0 87.975 0.32 ;
      END
    ANTENNADIFFAREA 0.054 ;
    END WENY[5]
  PIN TD[27]
    DIRECTION INPUT ;
    USE SIGNAL ;
    SHAPE ABUTMENT ;
    PORT
      LAYER M1 ;
      RECT 528.49 0.0 528.69 0.32 ;
      LAYER M2 ;
      RECT 528.49 0.0 528.69 0.32 ;
      LAYER M3 ;
      RECT 528.49 0.0 528.69 0.32 ;
      END
    ANTENNAGATEAREA 0.0072 ;
    ANTENNADIFFAREA 0.054 ;
    END TD[27]
  PIN TD[4]
    DIRECTION INPUT ;
    USE SIGNAL ;
    SHAPE ABUTMENT ;
    PORT
      LAYER M3 ;
      RECT 76.44 0.0 76.64 0.32 ;
      LAYER M2 ;
      RECT 76.44 0.0 76.64 0.32 ;
      LAYER M1 ;
      RECT 76.44 0.0 76.64 0.32 ;
      END
    ANTENNAGATEAREA 0.0072 ;
    ANTENNADIFFAREA 0.054 ;
    END TD[4]
  PIN D[27]
    DIRECTION INPUT ;
    USE SIGNAL ;
    SHAPE ABUTMENT ;
    PORT
      LAYER M1 ;
      RECT 530.79 0.0 530.99 0.32 ;
      LAYER M2 ;
      RECT 530.79 0.0 530.99 0.32 ;
      LAYER M3 ;
      RECT 530.79 0.0 530.99 0.32 ;
      LAYER M4 ;
      RECT 530.79 0.0 530.99 0.32 ;
      END
    ANTENNAGATEAREA 0.0072 ;
    ANTENNADIFFAREA 0.054 ;
    END D[27]
  PIN D[4]
    DIRECTION INPUT ;
    USE SIGNAL ;
    SHAPE ABUTMENT ;
    PORT
      LAYER M4 ;
      RECT 74.14 0.0 74.34 0.32 ;
      LAYER M3 ;
      RECT 74.14 0.0 74.34 0.32 ;
      LAYER M2 ;
      RECT 74.14 0.0 74.34 0.32 ;
      LAYER M1 ;
      RECT 74.14 0.0 74.34 0.32 ;
      END
    ANTENNAGATEAREA 0.0072 ;
    ANTENNADIFFAREA 0.054 ;
    END D[4]
  PIN TWEN[27]
    DIRECTION INPUT ;
    USE SIGNAL ;
    SHAPE ABUTMENT ;
    PORT
      LAYER M1 ;
      RECT 531.845 0.0 532.045 0.32 ;
      LAYER M2 ;
      RECT 531.845 0.0 532.045 0.32 ;
      LAYER M3 ;
      RECT 531.845 0.0 532.045 0.32 ;
      LAYER M4 ;
      RECT 531.845 0.0 532.045 0.32 ;
      END
    ANTENNAGATEAREA 0.0072 ;
    ANTENNADIFFAREA 0.054 ;
    END TWEN[27]
  PIN TWEN[4]
    DIRECTION INPUT ;
    USE SIGNAL ;
    SHAPE ABUTMENT ;
    PORT
      LAYER M4 ;
      RECT 73.085 0.0 73.285 0.32 ;
      LAYER M3 ;
      RECT 73.085 0.0 73.285 0.32 ;
      LAYER M2 ;
      RECT 73.085 0.0 73.285 0.32 ;
      LAYER M1 ;
      RECT 73.085 0.0 73.285 0.32 ;
      END
    ANTENNAGATEAREA 0.0072 ;
    ANTENNADIFFAREA 0.054 ;
    END TWEN[4]
  PIN Q[27]
    DIRECTION OUTPUT ;
    USE SIGNAL ;
    SHAPE ABUTMENT ;
    PORT
      LAYER M1 ;
      RECT 532.425 0.0 532.625 0.32 ;
      LAYER M2 ;
      RECT 532.425 0.0 532.625 0.32 ;
      LAYER M3 ;
      RECT 532.425 0.0 532.625 0.32 ;
      END
    ANTENNADIFFAREA 0.054 ;
    END Q[27]
  PIN Q[4]
    DIRECTION OUTPUT ;
    USE SIGNAL ;
    SHAPE ABUTMENT ;
    PORT
      LAYER M3 ;
      RECT 72.505 0.0 72.705 0.32 ;
      LAYER M2 ;
      RECT 72.505 0.0 72.705 0.32 ;
      LAYER M1 ;
      RECT 72.505 0.0 72.705 0.32 ;
      END
    ANTENNADIFFAREA 0.054 ;
    END Q[4]
  PIN WEN[27]
    DIRECTION INPUT ;
    USE SIGNAL ;
    SHAPE ABUTMENT ;
    PORT
      LAYER M4 ;
      RECT 532.89 0.0 533.07 0.32 ;
      LAYER M1 ;
      RECT 532.9 0.0 533.1 0.32 ;
      LAYER M2 ;
      RECT 532.9 0.0 533.1 0.32 ;
      LAYER M3 ;
      RECT 532.9 0.0 533.1 0.32 ;
      END
    ANTENNAGATEAREA 0.0072 ;
    ANTENNADIFFAREA 0.054 ;
    END WEN[27]
  PIN WEN[4]
    DIRECTION INPUT ;
    USE SIGNAL ;
    SHAPE ABUTMENT ;
    PORT
      LAYER M4 ;
      RECT 72.06 0.0 72.24 0.32 ;
      LAYER M3 ;
      RECT 72.03 0.0 72.23 0.32 ;
      LAYER M2 ;
      RECT 72.03 0.0 72.23 0.32 ;
      LAYER M1 ;
      RECT 72.03 0.0 72.23 0.32 ;
      END
    ANTENNAGATEAREA 0.0072 ;
    ANTENNADIFFAREA 0.054 ;
    END WEN[4]
  PIN WENY[27]
    DIRECTION OUTPUT ;
    USE SIGNAL ;
    SHAPE ABUTMENT ;
    PORT
      LAYER M4 ;
      RECT 533.94 0.0 534.12 0.32 ;
      LAYER M3 ;
      RECT 533.955 0.0 534.155 0.32 ;
      END
    ANTENNADIFFAREA 0.054 ;
    END WENY[27]
  PIN WENY[4]
    DIRECTION OUTPUT ;
    USE SIGNAL ;
    SHAPE ABUTMENT ;
    PORT
      LAYER M4 ;
      RECT 71.01 0.0 71.19 0.32 ;
      LAYER M3 ;
      RECT 70.975 0.0 71.175 0.32 ;
      END
    ANTENNADIFFAREA 0.054 ;
    END WENY[4]
  PIN TD[28]
    DIRECTION INPUT ;
    USE SIGNAL ;
    SHAPE ABUTMENT ;
    PORT
      LAYER M1 ;
      RECT 545.29 0.0 545.49 0.32 ;
      LAYER M2 ;
      RECT 545.29 0.0 545.49 0.32 ;
      LAYER M3 ;
      RECT 545.29 0.0 545.49 0.32 ;
      END
    ANTENNAGATEAREA 0.0072 ;
    ANTENNADIFFAREA 0.054 ;
    END TD[28]
  PIN TD[3]
    DIRECTION INPUT ;
    USE SIGNAL ;
    SHAPE ABUTMENT ;
    PORT
      LAYER M3 ;
      RECT 59.64 0.0 59.84 0.32 ;
      LAYER M2 ;
      RECT 59.64 0.0 59.84 0.32 ;
      LAYER M1 ;
      RECT 59.64 0.0 59.84 0.32 ;
      END
    ANTENNAGATEAREA 0.0072 ;
    ANTENNADIFFAREA 0.054 ;
    END TD[3]
  PIN D[28]
    DIRECTION INPUT ;
    USE SIGNAL ;
    SHAPE ABUTMENT ;
    PORT
      LAYER M1 ;
      RECT 547.59 0.0 547.79 0.32 ;
      LAYER M2 ;
      RECT 547.59 0.0 547.79 0.32 ;
      LAYER M3 ;
      RECT 547.59 0.0 547.79 0.32 ;
      LAYER M4 ;
      RECT 547.59 0.0 547.79 0.32 ;
      END
    ANTENNAGATEAREA 0.0072 ;
    ANTENNADIFFAREA 0.054 ;
    END D[28]
  PIN D[3]
    DIRECTION INPUT ;
    USE SIGNAL ;
    SHAPE ABUTMENT ;
    PORT
      LAYER M4 ;
      RECT 57.34 0.0 57.54 0.32 ;
      LAYER M3 ;
      RECT 57.34 0.0 57.54 0.32 ;
      LAYER M2 ;
      RECT 57.34 0.0 57.54 0.32 ;
      LAYER M1 ;
      RECT 57.34 0.0 57.54 0.32 ;
      END
    ANTENNAGATEAREA 0.0072 ;
    ANTENNADIFFAREA 0.054 ;
    END D[3]
  PIN TWEN[28]
    DIRECTION INPUT ;
    USE SIGNAL ;
    SHAPE ABUTMENT ;
    PORT
      LAYER M1 ;
      RECT 548.645 0.0 548.845 0.32 ;
      LAYER M2 ;
      RECT 548.645 0.0 548.845 0.32 ;
      LAYER M3 ;
      RECT 548.645 0.0 548.845 0.32 ;
      LAYER M4 ;
      RECT 548.645 0.0 548.845 0.32 ;
      END
    ANTENNAGATEAREA 0.0072 ;
    ANTENNADIFFAREA 0.054 ;
    END TWEN[28]
  PIN TWEN[3]
    DIRECTION INPUT ;
    USE SIGNAL ;
    SHAPE ABUTMENT ;
    PORT
      LAYER M4 ;
      RECT 56.285 0.0 56.485 0.32 ;
      LAYER M3 ;
      RECT 56.285 0.0 56.485 0.32 ;
      LAYER M2 ;
      RECT 56.285 0.0 56.485 0.32 ;
      LAYER M1 ;
      RECT 56.285 0.0 56.485 0.32 ;
      END
    ANTENNAGATEAREA 0.0072 ;
    ANTENNADIFFAREA 0.054 ;
    END TWEN[3]
  PIN Q[28]
    DIRECTION OUTPUT ;
    USE SIGNAL ;
    SHAPE ABUTMENT ;
    PORT
      LAYER M1 ;
      RECT 549.225 0.0 549.425 0.32 ;
      LAYER M2 ;
      RECT 549.225 0.0 549.425 0.32 ;
      LAYER M3 ;
      RECT 549.225 0.0 549.425 0.32 ;
      END
    ANTENNADIFFAREA 0.054 ;
    END Q[28]
  PIN Q[3]
    DIRECTION OUTPUT ;
    USE SIGNAL ;
    SHAPE ABUTMENT ;
    PORT
      LAYER M3 ;
      RECT 55.705 0.0 55.905 0.32 ;
      LAYER M2 ;
      RECT 55.705 0.0 55.905 0.32 ;
      LAYER M1 ;
      RECT 55.705 0.0 55.905 0.32 ;
      END
    ANTENNADIFFAREA 0.054 ;
    END Q[3]
  PIN WEN[28]
    DIRECTION INPUT ;
    USE SIGNAL ;
    SHAPE ABUTMENT ;
    PORT
      LAYER M4 ;
      RECT 549.69 0.0 549.87 0.32 ;
      LAYER M1 ;
      RECT 549.7 0.0 549.9 0.32 ;
      LAYER M2 ;
      RECT 549.7 0.0 549.9 0.32 ;
      LAYER M3 ;
      RECT 549.7 0.0 549.9 0.32 ;
      END
    ANTENNAGATEAREA 0.0072 ;
    ANTENNADIFFAREA 0.054 ;
    END WEN[28]
  PIN WEN[3]
    DIRECTION INPUT ;
    USE SIGNAL ;
    SHAPE ABUTMENT ;
    PORT
      LAYER M4 ;
      RECT 55.26 0.0 55.44 0.32 ;
      LAYER M3 ;
      RECT 55.23 0.0 55.43 0.32 ;
      LAYER M2 ;
      RECT 55.23 0.0 55.43 0.32 ;
      LAYER M1 ;
      RECT 55.23 0.0 55.43 0.32 ;
      END
    ANTENNAGATEAREA 0.0072 ;
    ANTENNADIFFAREA 0.054 ;
    END WEN[3]
  PIN WENY[28]
    DIRECTION OUTPUT ;
    USE SIGNAL ;
    SHAPE ABUTMENT ;
    PORT
      LAYER M4 ;
      RECT 550.74 0.0 550.92 0.32 ;
      LAYER M3 ;
      RECT 550.755 0.0 550.955 0.32 ;
      END
    ANTENNADIFFAREA 0.054 ;
    END WENY[28]
  PIN WENY[3]
    DIRECTION OUTPUT ;
    USE SIGNAL ;
    SHAPE ABUTMENT ;
    PORT
      LAYER M4 ;
      RECT 54.21 0.0 54.39 0.32 ;
      LAYER M3 ;
      RECT 54.175 0.0 54.375 0.32 ;
      END
    ANTENNADIFFAREA 0.054 ;
    END WENY[3]
  PIN TD[29]
    DIRECTION INPUT ;
    USE SIGNAL ;
    SHAPE ABUTMENT ;
    PORT
      LAYER M1 ;
      RECT 562.09 0.0 562.29 0.32 ;
      LAYER M2 ;
      RECT 562.09 0.0 562.29 0.32 ;
      LAYER M3 ;
      RECT 562.09 0.0 562.29 0.32 ;
      END
    ANTENNAGATEAREA 0.0072 ;
    ANTENNADIFFAREA 0.054 ;
    END TD[29]
  PIN TD[2]
    DIRECTION INPUT ;
    USE SIGNAL ;
    SHAPE ABUTMENT ;
    PORT
      LAYER M3 ;
      RECT 42.84 0.0 43.04 0.32 ;
      LAYER M2 ;
      RECT 42.84 0.0 43.04 0.32 ;
      LAYER M1 ;
      RECT 42.84 0.0 43.04 0.32 ;
      END
    ANTENNAGATEAREA 0.0072 ;
    ANTENNADIFFAREA 0.054 ;
    END TD[2]
  PIN D[29]
    DIRECTION INPUT ;
    USE SIGNAL ;
    SHAPE ABUTMENT ;
    PORT
      LAYER M1 ;
      RECT 564.39 0.0 564.59 0.32 ;
      LAYER M2 ;
      RECT 564.39 0.0 564.59 0.32 ;
      LAYER M3 ;
      RECT 564.39 0.0 564.59 0.32 ;
      LAYER M4 ;
      RECT 564.39 0.0 564.59 0.32 ;
      END
    ANTENNAGATEAREA 0.0072 ;
    ANTENNADIFFAREA 0.054 ;
    END D[29]
  PIN D[2]
    DIRECTION INPUT ;
    USE SIGNAL ;
    SHAPE ABUTMENT ;
    PORT
      LAYER M4 ;
      RECT 40.54 0.0 40.74 0.32 ;
      LAYER M3 ;
      RECT 40.54 0.0 40.74 0.32 ;
      LAYER M2 ;
      RECT 40.54 0.0 40.74 0.32 ;
      LAYER M1 ;
      RECT 40.54 0.0 40.74 0.32 ;
      END
    ANTENNAGATEAREA 0.0072 ;
    ANTENNADIFFAREA 0.054 ;
    END D[2]
  PIN TWEN[29]
    DIRECTION INPUT ;
    USE SIGNAL ;
    SHAPE ABUTMENT ;
    PORT
      LAYER M1 ;
      RECT 565.445 0.0 565.645 0.32 ;
      LAYER M2 ;
      RECT 565.445 0.0 565.645 0.32 ;
      LAYER M3 ;
      RECT 565.445 0.0 565.645 0.32 ;
      LAYER M4 ;
      RECT 565.445 0.0 565.645 0.32 ;
      END
    ANTENNAGATEAREA 0.0072 ;
    ANTENNADIFFAREA 0.054 ;
    END TWEN[29]
  PIN TWEN[2]
    DIRECTION INPUT ;
    USE SIGNAL ;
    SHAPE ABUTMENT ;
    PORT
      LAYER M4 ;
      RECT 39.485 0.0 39.685 0.32 ;
      LAYER M3 ;
      RECT 39.485 0.0 39.685 0.32 ;
      LAYER M2 ;
      RECT 39.485 0.0 39.685 0.32 ;
      LAYER M1 ;
      RECT 39.485 0.0 39.685 0.32 ;
      END
    ANTENNAGATEAREA 0.0072 ;
    ANTENNADIFFAREA 0.054 ;
    END TWEN[2]
  PIN Q[29]
    DIRECTION OUTPUT ;
    USE SIGNAL ;
    SHAPE ABUTMENT ;
    PORT
      LAYER M1 ;
      RECT 566.025 0.0 566.225 0.32 ;
      LAYER M2 ;
      RECT 566.025 0.0 566.225 0.32 ;
      LAYER M3 ;
      RECT 566.025 0.0 566.225 0.32 ;
      END
    ANTENNADIFFAREA 0.054 ;
    END Q[29]
  PIN Q[2]
    DIRECTION OUTPUT ;
    USE SIGNAL ;
    SHAPE ABUTMENT ;
    PORT
      LAYER M3 ;
      RECT 38.905 0.0 39.105 0.32 ;
      LAYER M2 ;
      RECT 38.905 0.0 39.105 0.32 ;
      LAYER M1 ;
      RECT 38.905 0.0 39.105 0.32 ;
      END
    ANTENNADIFFAREA 0.054 ;
    END Q[2]
  PIN WEN[29]
    DIRECTION INPUT ;
    USE SIGNAL ;
    SHAPE ABUTMENT ;
    PORT
      LAYER M4 ;
      RECT 566.49 0.0 566.67 0.32 ;
      LAYER M1 ;
      RECT 566.5 0.0 566.7 0.32 ;
      LAYER M2 ;
      RECT 566.5 0.0 566.7 0.32 ;
      LAYER M3 ;
      RECT 566.5 0.0 566.7 0.32 ;
      END
    ANTENNAGATEAREA 0.0072 ;
    ANTENNADIFFAREA 0.054 ;
    END WEN[29]
  PIN WEN[2]
    DIRECTION INPUT ;
    USE SIGNAL ;
    SHAPE ABUTMENT ;
    PORT
      LAYER M4 ;
      RECT 38.46 0.0 38.64 0.32 ;
      LAYER M3 ;
      RECT 38.43 0.0 38.63 0.32 ;
      LAYER M2 ;
      RECT 38.43 0.0 38.63 0.32 ;
      LAYER M1 ;
      RECT 38.43 0.0 38.63 0.32 ;
      END
    ANTENNAGATEAREA 0.0072 ;
    ANTENNADIFFAREA 0.054 ;
    END WEN[2]
  PIN WENY[29]
    DIRECTION OUTPUT ;
    USE SIGNAL ;
    SHAPE ABUTMENT ;
    PORT
      LAYER M4 ;
      RECT 567.54 0.0 567.72 0.32 ;
      LAYER M3 ;
      RECT 567.555 0.0 567.755 0.32 ;
      END
    ANTENNADIFFAREA 0.054 ;
    END WENY[29]
  PIN WENY[2]
    DIRECTION OUTPUT ;
    USE SIGNAL ;
    SHAPE ABUTMENT ;
    PORT
      LAYER M4 ;
      RECT 37.41 0.0 37.59 0.32 ;
      LAYER M3 ;
      RECT 37.375 0.0 37.575 0.32 ;
      END
    ANTENNADIFFAREA 0.054 ;
    END WENY[2]
  PIN TD[30]
    DIRECTION INPUT ;
    USE SIGNAL ;
    SHAPE ABUTMENT ;
    PORT
      LAYER M1 ;
      RECT 578.89 0.0 579.09 0.32 ;
      LAYER M2 ;
      RECT 578.89 0.0 579.09 0.32 ;
      LAYER M3 ;
      RECT 578.89 0.0 579.09 0.32 ;
      END
    ANTENNAGATEAREA 0.0072 ;
    ANTENNADIFFAREA 0.054 ;
    END TD[30]
  PIN TD[1]
    DIRECTION INPUT ;
    USE SIGNAL ;
    SHAPE ABUTMENT ;
    PORT
      LAYER M3 ;
      RECT 26.04 0.0 26.24 0.32 ;
      LAYER M2 ;
      RECT 26.04 0.0 26.24 0.32 ;
      LAYER M1 ;
      RECT 26.04 0.0 26.24 0.32 ;
      END
    ANTENNAGATEAREA 0.0072 ;
    ANTENNADIFFAREA 0.054 ;
    END TD[1]
  PIN D[30]
    DIRECTION INPUT ;
    USE SIGNAL ;
    SHAPE ABUTMENT ;
    PORT
      LAYER M1 ;
      RECT 581.19 0.0 581.39 0.32 ;
      LAYER M2 ;
      RECT 581.19 0.0 581.39 0.32 ;
      LAYER M3 ;
      RECT 581.19 0.0 581.39 0.32 ;
      LAYER M4 ;
      RECT 581.19 0.0 581.39 0.32 ;
      END
    ANTENNAGATEAREA 0.0072 ;
    ANTENNADIFFAREA 0.054 ;
    END D[30]
  PIN D[1]
    DIRECTION INPUT ;
    USE SIGNAL ;
    SHAPE ABUTMENT ;
    PORT
      LAYER M4 ;
      RECT 23.74 0.0 23.94 0.32 ;
      LAYER M3 ;
      RECT 23.74 0.0 23.94 0.32 ;
      LAYER M2 ;
      RECT 23.74 0.0 23.94 0.32 ;
      LAYER M1 ;
      RECT 23.74 0.0 23.94 0.32 ;
      END
    ANTENNAGATEAREA 0.0072 ;
    ANTENNADIFFAREA 0.054 ;
    END D[1]
  PIN TWEN[30]
    DIRECTION INPUT ;
    USE SIGNAL ;
    SHAPE ABUTMENT ;
    PORT
      LAYER M1 ;
      RECT 582.245 0.0 582.445 0.32 ;
      LAYER M2 ;
      RECT 582.245 0.0 582.445 0.32 ;
      LAYER M3 ;
      RECT 582.245 0.0 582.445 0.32 ;
      LAYER M4 ;
      RECT 582.245 0.0 582.445 0.32 ;
      END
    ANTENNAGATEAREA 0.0072 ;
    ANTENNADIFFAREA 0.054 ;
    END TWEN[30]
  PIN TWEN[1]
    DIRECTION INPUT ;
    USE SIGNAL ;
    SHAPE ABUTMENT ;
    PORT
      LAYER M4 ;
      RECT 22.685 0.0 22.885 0.32 ;
      LAYER M3 ;
      RECT 22.685 0.0 22.885 0.32 ;
      LAYER M2 ;
      RECT 22.685 0.0 22.885 0.32 ;
      LAYER M1 ;
      RECT 22.685 0.0 22.885 0.32 ;
      END
    ANTENNAGATEAREA 0.0072 ;
    ANTENNADIFFAREA 0.054 ;
    END TWEN[1]
  PIN Q[30]
    DIRECTION OUTPUT ;
    USE SIGNAL ;
    SHAPE ABUTMENT ;
    PORT
      LAYER M1 ;
      RECT 582.825 0.0 583.025 0.32 ;
      LAYER M2 ;
      RECT 582.825 0.0 583.025 0.32 ;
      LAYER M3 ;
      RECT 582.825 0.0 583.025 0.32 ;
      END
    ANTENNADIFFAREA 0.054 ;
    END Q[30]
  PIN Q[1]
    DIRECTION OUTPUT ;
    USE SIGNAL ;
    SHAPE ABUTMENT ;
    PORT
      LAYER M3 ;
      RECT 22.105 0.0 22.305 0.32 ;
      LAYER M2 ;
      RECT 22.105 0.0 22.305 0.32 ;
      LAYER M1 ;
      RECT 22.105 0.0 22.305 0.32 ;
      END
    ANTENNADIFFAREA 0.054 ;
    END Q[1]
  PIN WEN[30]
    DIRECTION INPUT ;
    USE SIGNAL ;
    SHAPE ABUTMENT ;
    PORT
      LAYER M4 ;
      RECT 583.29 0.0 583.47 0.32 ;
      LAYER M1 ;
      RECT 583.3 0.0 583.5 0.32 ;
      LAYER M2 ;
      RECT 583.3 0.0 583.5 0.32 ;
      LAYER M3 ;
      RECT 583.3 0.0 583.5 0.32 ;
      END
    ANTENNAGATEAREA 0.0072 ;
    ANTENNADIFFAREA 0.054 ;
    END WEN[30]
  PIN WEN[1]
    DIRECTION INPUT ;
    USE SIGNAL ;
    SHAPE ABUTMENT ;
    PORT
      LAYER M4 ;
      RECT 21.66 0.0 21.84 0.32 ;
      LAYER M3 ;
      RECT 21.63 0.0 21.83 0.32 ;
      LAYER M2 ;
      RECT 21.63 0.0 21.83 0.32 ;
      LAYER M1 ;
      RECT 21.63 0.0 21.83 0.32 ;
      END
    ANTENNAGATEAREA 0.0072 ;
    ANTENNADIFFAREA 0.054 ;
    END WEN[1]
  PIN WENY[30]
    DIRECTION OUTPUT ;
    USE SIGNAL ;
    SHAPE ABUTMENT ;
    PORT
      LAYER M4 ;
      RECT 584.34 0.0 584.52 0.32 ;
      LAYER M3 ;
      RECT 584.355 0.0 584.555 0.32 ;
      END
    ANTENNADIFFAREA 0.054 ;
    END WENY[30]
  PIN WENY[1]
    DIRECTION OUTPUT ;
    USE SIGNAL ;
    SHAPE ABUTMENT ;
    PORT
      LAYER M4 ;
      RECT 20.61 0.0 20.79 0.32 ;
      LAYER M3 ;
      RECT 20.575 0.0 20.775 0.32 ;
      END
    ANTENNADIFFAREA 0.054 ;
    END WENY[1]
  PIN TD[31]
    DIRECTION INPUT ;
    USE SIGNAL ;
    SHAPE ABUTMENT ;
    PORT
      LAYER M1 ;
      RECT 595.69 0.0 595.89 0.32 ;
      LAYER M2 ;
      RECT 595.69 0.0 595.89 0.32 ;
      LAYER M3 ;
      RECT 595.69 0.0 595.89 0.32 ;
      END
    ANTENNAGATEAREA 0.0072 ;
    ANTENNADIFFAREA 0.054 ;
    END TD[31]
  PIN TD[0]
    DIRECTION INPUT ;
    USE SIGNAL ;
    SHAPE ABUTMENT ;
    PORT
      LAYER M3 ;
      RECT 9.24 0.0 9.44 0.32 ;
      LAYER M2 ;
      RECT 9.24 0.0 9.44 0.32 ;
      LAYER M1 ;
      RECT 9.24 0.0 9.44 0.32 ;
      END
    ANTENNAGATEAREA 0.0072 ;
    ANTENNADIFFAREA 0.054 ;
    END TD[0]
  PIN D[31]
    DIRECTION INPUT ;
    USE SIGNAL ;
    SHAPE ABUTMENT ;
    PORT
      LAYER M1 ;
      RECT 597.99 0.0 598.19 0.32 ;
      LAYER M2 ;
      RECT 597.99 0.0 598.19 0.32 ;
      LAYER M3 ;
      RECT 597.99 0.0 598.19 0.32 ;
      LAYER M4 ;
      RECT 597.99 0.0 598.19 0.32 ;
      END
    ANTENNAGATEAREA 0.0072 ;
    ANTENNADIFFAREA 0.054 ;
    END D[31]
  PIN D[0]
    DIRECTION INPUT ;
    USE SIGNAL ;
    SHAPE ABUTMENT ;
    PORT
      LAYER M4 ;
      RECT 6.94 0.0 7.14 0.32 ;
      LAYER M3 ;
      RECT 6.94 0.0 7.14 0.32 ;
      LAYER M2 ;
      RECT 6.94 0.0 7.14 0.32 ;
      LAYER M1 ;
      RECT 6.94 0.0 7.14 0.32 ;
      END
    ANTENNAGATEAREA 0.0072 ;
    ANTENNADIFFAREA 0.054 ;
    END D[0]
  PIN TWEN[31]
    DIRECTION INPUT ;
    USE SIGNAL ;
    SHAPE ABUTMENT ;
    PORT
      LAYER M1 ;
      RECT 599.045 0.0 599.245 0.32 ;
      LAYER M2 ;
      RECT 599.045 0.0 599.245 0.32 ;
      LAYER M3 ;
      RECT 599.045 0.0 599.245 0.32 ;
      LAYER M4 ;
      RECT 599.045 0.0 599.245 0.32 ;
      END
    ANTENNAGATEAREA 0.0072 ;
    ANTENNADIFFAREA 0.054 ;
    END TWEN[31]
  PIN TWEN[0]
    DIRECTION INPUT ;
    USE SIGNAL ;
    SHAPE ABUTMENT ;
    PORT
      LAYER M4 ;
      RECT 5.885 0.0 6.085 0.32 ;
      LAYER M3 ;
      RECT 5.885 0.0 6.085 0.32 ;
      LAYER M2 ;
      RECT 5.885 0.0 6.085 0.32 ;
      LAYER M1 ;
      RECT 5.885 0.0 6.085 0.32 ;
      END
    ANTENNAGATEAREA 0.0072 ;
    ANTENNADIFFAREA 0.054 ;
    END TWEN[0]
  PIN Q[31]
    DIRECTION OUTPUT ;
    USE SIGNAL ;
    SHAPE ABUTMENT ;
    PORT
      LAYER M1 ;
      RECT 599.625 0.0 599.825 0.32 ;
      LAYER M2 ;
      RECT 599.625 0.0 599.825 0.32 ;
      LAYER M3 ;
      RECT 599.625 0.0 599.825 0.32 ;
      END
    ANTENNADIFFAREA 0.054 ;
    END Q[31]
  PIN Q[0]
    DIRECTION OUTPUT ;
    USE SIGNAL ;
    SHAPE ABUTMENT ;
    PORT
      LAYER M3 ;
      RECT 5.305 0.0 5.505 0.32 ;
      LAYER M2 ;
      RECT 5.305 0.0 5.505 0.32 ;
      LAYER M1 ;
      RECT 5.305 0.0 5.505 0.32 ;
      END
    ANTENNADIFFAREA 0.054 ;
    END Q[0]
  PIN WEN[31]
    DIRECTION INPUT ;
    USE SIGNAL ;
    SHAPE ABUTMENT ;
    PORT
      LAYER M4 ;
      RECT 600.09 0.0 600.27 0.32 ;
      LAYER M1 ;
      RECT 600.1 0.0 600.3 0.32 ;
      LAYER M2 ;
      RECT 600.1 0.0 600.3 0.32 ;
      LAYER M3 ;
      RECT 600.1 0.0 600.3 0.32 ;
      END
    ANTENNAGATEAREA 0.0072 ;
    ANTENNADIFFAREA 0.054 ;
    END WEN[31]
  PIN WEN[0]
    DIRECTION INPUT ;
    USE SIGNAL ;
    SHAPE ABUTMENT ;
    PORT
      LAYER M4 ;
      RECT 4.86 0.0 5.04 0.32 ;
      LAYER M3 ;
      RECT 4.83 0.0 5.03 0.32 ;
      LAYER M2 ;
      RECT 4.83 0.0 5.03 0.32 ;
      LAYER M1 ;
      RECT 4.83 0.0 5.03 0.32 ;
      END
    ANTENNAGATEAREA 0.0072 ;
    ANTENNADIFFAREA 0.054 ;
    END WEN[0]
  PIN WENY[31]
    DIRECTION OUTPUT ;
    USE SIGNAL ;
    SHAPE ABUTMENT ;
    PORT
      LAYER M4 ;
      RECT 601.14 0.0 601.32 0.32 ;
      LAYER M3 ;
      RECT 601.155 0.0 601.355 0.32 ;
      END
    ANTENNADIFFAREA 0.054 ;
    END WENY[31]
  PIN WENY[0]
    DIRECTION OUTPUT ;
    USE SIGNAL ;
    SHAPE ABUTMENT ;
    PORT
      LAYER M4 ;
      RECT 3.81 0.0 3.99 0.32 ;
      LAYER M3 ;
      RECT 3.775 0.0 3.975 0.32 ;
      END
    ANTENNADIFFAREA 0.054 ;
    END WENY[0]
  PIN SI[1]
    DIRECTION INPUT ;
    USE SIGNAL ;
    SHAPE ABUTMENT ;
    PORT
      LAYER M1 ;
      RECT 604.15 0.0 604.35 0.32 ;
      LAYER M2 ;
      RECT 604.15 0.0 604.35 0.32 ;
      LAYER M3 ;
      RECT 604.15 0.0 604.35 0.32 ;
      END
    ANTENNAGATEAREA 0.0072 ;
    ANTENNADIFFAREA 0.054 ;
    END SI[1]
  PIN SI[0]
    DIRECTION INPUT ;
    USE SIGNAL ;
    SHAPE ABUTMENT ;
    PORT
      LAYER M3 ;
      RECT 0.78 0.0 0.98 0.32 ;
      LAYER M2 ;
      RECT 0.78 0.0 0.98 0.32 ;
      LAYER M1 ;
      RECT 0.78 0.0 0.98 0.32 ;
      END
    ANTENNAGATEAREA 0.0072 ;
    ANTENNADIFFAREA 0.054 ;
    END SI[0]
  PIN VDDCE
    DIRECTION INOUT ;
    USE POWER ;
    PORT
      LAYER M4 ;
      RECT 0.695 0.0 0.845 301.17 ;
      END
    PORT
      LAYER M4 ;
      RECT 4.255 0.0 4.595 301.17 ;
      END
    PORT
      LAYER M4 ;
      RECT 6.365 0.0 6.705 301.17 ;
      END
    PORT
      LAYER M4 ;
      RECT 12.655 0.0 12.995 301.17 ;
      END
    PORT
      LAYER M4 ;
      RECT 14.765 0.0 15.105 301.17 ;
      END
    PORT
      LAYER M4 ;
      RECT 21.055 0.0 21.395 301.17 ;
      END
    PORT
      LAYER M4 ;
      RECT 23.165 0.0 23.505 301.17 ;
      END
    PORT
      LAYER M4 ;
      RECT 29.455 0.0 29.795 301.17 ;
      END
    PORT
      LAYER M4 ;
      RECT 31.565 0.0 31.905 301.17 ;
      END
    PORT
      LAYER M4 ;
      RECT 37.855 0.0 38.195 301.17 ;
      END
    PORT
      LAYER M4 ;
      RECT 39.965 0.0 40.305 301.17 ;
      END
    PORT
      LAYER M4 ;
      RECT 46.255 0.0 46.595 301.17 ;
      END
    PORT
      LAYER M4 ;
      RECT 48.365 0.0 48.705 301.17 ;
      END
    PORT
      LAYER M4 ;
      RECT 54.655 0.0 54.995 301.17 ;
      END
    PORT
      LAYER M4 ;
      RECT 56.765 0.0 57.105 301.17 ;
      END
    PORT
      LAYER M4 ;
      RECT 63.055 0.0 63.395 301.17 ;
      END
    PORT
      LAYER M4 ;
      RECT 65.165 0.0 65.505 301.17 ;
      END
    PORT
      LAYER M4 ;
      RECT 71.455 0.0 71.795 301.17 ;
      END
    PORT
      LAYER M4 ;
      RECT 73.565 0.0 73.905 301.17 ;
      END
    PORT
      LAYER M4 ;
      RECT 79.855 0.0 80.195 301.17 ;
      END
    PORT
      LAYER M4 ;
      RECT 81.965 0.0 82.305 301.17 ;
      END
    PORT
      LAYER M4 ;
      RECT 88.255 0.0 88.595 301.17 ;
      END
    PORT
      LAYER M4 ;
      RECT 90.365 0.0 90.705 301.17 ;
      END
    PORT
      LAYER M4 ;
      RECT 96.655 0.0 96.995 301.17 ;
      END
    PORT
      LAYER M4 ;
      RECT 98.765 0.0 99.105 301.17 ;
      END
    PORT
      LAYER M4 ;
      RECT 105.055 0.0 105.395 301.17 ;
      END
    PORT
      LAYER M4 ;
      RECT 107.165 0.0 107.505 301.17 ;
      END
    PORT
      LAYER M4 ;
      RECT 113.455 0.0 113.795 301.17 ;
      END
    PORT
      LAYER M4 ;
      RECT 115.565 0.0 115.905 301.17 ;
      END
    PORT
      LAYER M4 ;
      RECT 121.855 0.0 122.195 301.17 ;
      END
    PORT
      LAYER M4 ;
      RECT 123.965 0.0 124.305 301.17 ;
      END
    PORT
      LAYER M4 ;
      RECT 130.255 0.0 130.595 301.17 ;
      END
    PORT
      LAYER M4 ;
      RECT 132.365 0.0 132.705 301.17 ;
      END
    PORT
      LAYER M4 ;
      RECT 138.655 0.0 138.995 301.17 ;
      END
    PORT
      LAYER M4 ;
      RECT 140.765 0.0 141.105 301.17 ;
      END
    PORT
      LAYER M4 ;
      RECT 147.055 0.0 147.395 301.17 ;
      END
    PORT
      LAYER M4 ;
      RECT 149.165 0.0 149.505 301.17 ;
      END
    PORT
      LAYER M4 ;
      RECT 155.455 0.0 155.795 301.17 ;
      END
    PORT
      LAYER M4 ;
      RECT 157.565 0.0 157.905 301.17 ;
      END
    PORT
      LAYER M4 ;
      RECT 163.855 0.0 164.195 301.17 ;
      END
    PORT
      LAYER M4 ;
      RECT 165.965 0.0 166.305 301.17 ;
      END
    PORT
      LAYER M4 ;
      RECT 172.255 0.0 172.595 301.17 ;
      END
    PORT
      LAYER M4 ;
      RECT 174.365 0.0 174.705 301.17 ;
      END
    PORT
      LAYER M4 ;
      RECT 180.655 0.0 180.995 301.17 ;
      END
    PORT
      LAYER M4 ;
      RECT 182.765 0.0 183.105 301.17 ;
      END
    PORT
      LAYER M4 ;
      RECT 189.055 0.0 189.395 301.17 ;
      END
    PORT
      LAYER M4 ;
      RECT 191.165 0.0 191.505 301.17 ;
      END
    PORT
      LAYER M4 ;
      RECT 197.455 0.0 197.795 301.17 ;
      END
    PORT
      LAYER M4 ;
      RECT 199.565 0.0 199.905 301.17 ;
      END
    PORT
      LAYER M4 ;
      RECT 205.855 0.0 206.195 301.17 ;
      END
    PORT
      LAYER M4 ;
      RECT 207.965 0.0 208.305 301.17 ;
      END
    PORT
      LAYER M4 ;
      RECT 214.255 0.0 214.595 301.17 ;
      END
    PORT
      LAYER M4 ;
      RECT 216.365 0.0 216.705 301.17 ;
      END
    PORT
      LAYER M4 ;
      RECT 222.655 0.0 222.995 301.17 ;
      END
    PORT
      LAYER M4 ;
      RECT 224.765 0.0 225.105 301.17 ;
      END
    PORT
      LAYER M4 ;
      RECT 231.055 0.0 231.395 301.17 ;
      END
    PORT
      LAYER M4 ;
      RECT 233.165 0.0 233.505 301.17 ;
      END
    PORT
      LAYER M4 ;
      RECT 239.455 0.0 239.795 301.17 ;
      END
    PORT
      LAYER M4 ;
      RECT 241.565 0.0 241.905 301.17 ;
      END
    PORT
      LAYER M4 ;
      RECT 247.855 0.0 248.195 301.17 ;
      END
    PORT
      LAYER M4 ;
      RECT 249.965 0.0 250.305 301.17 ;
      END
    PORT
      LAYER M4 ;
      RECT 256.255 0.0 256.595 301.17 ;
      END
    PORT
      LAYER M4 ;
      RECT 258.365 0.0 258.705 301.17 ;
      END
    PORT
      LAYER M4 ;
      RECT 264.655 0.0 264.995 301.17 ;
      END
    PORT
      LAYER M4 ;
      RECT 266.765 0.0 267.105 301.17 ;
      END
    PORT
      LAYER M4 ;
      RECT 271.495 0.0 271.925 301.17 ;
      END
    PORT
      LAYER M4 ;
      RECT 276.165 0.0 276.495 301.17 ;
      END
    PORT
      LAYER M4 ;
      RECT 279.44 0.0 279.86 301.17 ;
      END
    PORT
      LAYER M4 ;
      RECT 282.09 0.0 282.51 301.17 ;
      END
    PORT
      LAYER M4 ;
      RECT 289.48 0.0 289.9 301.17 ;
      END
    PORT
      LAYER M4 ;
      RECT 294.69 0.0 295.11 301.17 ;
      END
    PORT
      LAYER M4 ;
      RECT 307.125 0.0 307.545 301.17 ;
      END
    PORT
      LAYER M4 ;
      RECT 320.55 0.0 320.97 301.17 ;
      END
    PORT
      LAYER M4 ;
      RECT 325.26 0.0 325.68 301.17 ;
      END
    PORT
      LAYER M4 ;
      RECT 328.64 0.0 328.97 301.17 ;
      END
    PORT
      LAYER M4 ;
      RECT 333.21 0.0 333.63 301.17 ;
      END
    PORT
      LAYER M4 ;
      RECT 338.025 0.0 338.365 301.17 ;
      END
    PORT
      LAYER M4 ;
      RECT 340.135 0.0 340.475 301.17 ;
      END
    PORT
      LAYER M4 ;
      RECT 346.425 0.0 346.765 301.17 ;
      END
    PORT
      LAYER M4 ;
      RECT 348.535 0.0 348.875 301.17 ;
      END
    PORT
      LAYER M4 ;
      RECT 354.825 0.0 355.165 301.17 ;
      END
    PORT
      LAYER M4 ;
      RECT 356.935 0.0 357.275 301.17 ;
      END
    PORT
      LAYER M4 ;
      RECT 363.225 0.0 363.565 301.17 ;
      END
    PORT
      LAYER M4 ;
      RECT 365.335 0.0 365.675 301.17 ;
      END
    PORT
      LAYER M4 ;
      RECT 371.625 0.0 371.965 301.17 ;
      END
    PORT
      LAYER M4 ;
      RECT 373.735 0.0 374.075 301.17 ;
      END
    PORT
      LAYER M4 ;
      RECT 380.025 0.0 380.365 301.17 ;
      END
    PORT
      LAYER M4 ;
      RECT 382.135 0.0 382.475 301.17 ;
      END
    PORT
      LAYER M4 ;
      RECT 388.425 0.0 388.765 301.17 ;
      END
    PORT
      LAYER M4 ;
      RECT 390.535 0.0 390.875 301.17 ;
      END
    PORT
      LAYER M4 ;
      RECT 396.825 0.0 397.165 301.17 ;
      END
    PORT
      LAYER M4 ;
      RECT 398.935 0.0 399.275 301.17 ;
      END
    PORT
      LAYER M4 ;
      RECT 405.225 0.0 405.565 301.17 ;
      END
    PORT
      LAYER M4 ;
      RECT 407.335 0.0 407.675 301.17 ;
      END
    PORT
      LAYER M4 ;
      RECT 413.625 0.0 413.965 301.17 ;
      END
    PORT
      LAYER M4 ;
      RECT 415.735 0.0 416.075 301.17 ;
      END
    PORT
      LAYER M4 ;
      RECT 422.025 0.0 422.365 301.17 ;
      END
    PORT
      LAYER M4 ;
      RECT 424.135 0.0 424.475 301.17 ;
      END
    PORT
      LAYER M4 ;
      RECT 430.425 0.0 430.765 301.17 ;
      END
    PORT
      LAYER M4 ;
      RECT 432.535 0.0 432.875 301.17 ;
      END
    PORT
      LAYER M4 ;
      RECT 438.825 0.0 439.165 301.17 ;
      END
    PORT
      LAYER M4 ;
      RECT 440.935 0.0 441.275 301.17 ;
      END
    PORT
      LAYER M4 ;
      RECT 447.225 0.0 447.565 301.17 ;
      END
    PORT
      LAYER M4 ;
      RECT 449.335 0.0 449.675 301.17 ;
      END
    PORT
      LAYER M4 ;
      RECT 455.625 0.0 455.965 301.17 ;
      END
    PORT
      LAYER M4 ;
      RECT 457.735 0.0 458.075 301.17 ;
      END
    PORT
      LAYER M4 ;
      RECT 464.025 0.0 464.365 301.17 ;
      END
    PORT
      LAYER M4 ;
      RECT 466.135 0.0 466.475 301.17 ;
      END
    PORT
      LAYER M4 ;
      RECT 472.425 0.0 472.765 301.17 ;
      END
    PORT
      LAYER M4 ;
      RECT 474.535 0.0 474.875 301.17 ;
      END
    PORT
      LAYER M4 ;
      RECT 480.825 0.0 481.165 301.17 ;
      END
    PORT
      LAYER M4 ;
      RECT 482.935 0.0 483.275 301.17 ;
      END
    PORT
      LAYER M4 ;
      RECT 489.225 0.0 489.565 301.17 ;
      END
    PORT
      LAYER M4 ;
      RECT 491.335 0.0 491.675 301.17 ;
      END
    PORT
      LAYER M4 ;
      RECT 497.625 0.0 497.965 301.17 ;
      END
    PORT
      LAYER M4 ;
      RECT 499.735 0.0 500.075 301.17 ;
      END
    PORT
      LAYER M4 ;
      RECT 506.025 0.0 506.365 301.17 ;
      END
    PORT
      LAYER M4 ;
      RECT 508.135 0.0 508.475 301.17 ;
      END
    PORT
      LAYER M4 ;
      RECT 514.425 0.0 514.765 301.17 ;
      END
    PORT
      LAYER M4 ;
      RECT 516.535 0.0 516.875 301.17 ;
      END
    PORT
      LAYER M4 ;
      RECT 522.825 0.0 523.165 301.17 ;
      END
    PORT
      LAYER M4 ;
      RECT 524.935 0.0 525.275 301.17 ;
      END
    PORT
      LAYER M4 ;
      RECT 531.225 0.0 531.565 301.17 ;
      END
    PORT
      LAYER M4 ;
      RECT 533.335 0.0 533.675 301.17 ;
      END
    PORT
      LAYER M4 ;
      RECT 539.625 0.0 539.965 301.17 ;
      END
    PORT
      LAYER M4 ;
      RECT 541.735 0.0 542.075 301.17 ;
      END
    PORT
      LAYER M4 ;
      RECT 548.025 0.0 548.365 301.17 ;
      END
    PORT
      LAYER M4 ;
      RECT 550.135 0.0 550.475 301.17 ;
      END
    PORT
      LAYER M4 ;
      RECT 556.425 0.0 556.765 301.17 ;
      END
    PORT
      LAYER M4 ;
      RECT 558.535 0.0 558.875 301.17 ;
      END
    PORT
      LAYER M4 ;
      RECT 564.825 0.0 565.165 301.17 ;
      END
    PORT
      LAYER M4 ;
      RECT 566.935 0.0 567.275 301.17 ;
      END
    PORT
      LAYER M4 ;
      RECT 573.225 0.0 573.565 301.17 ;
      END
    PORT
      LAYER M4 ;
      RECT 575.335 0.0 575.675 301.17 ;
      END
    PORT
      LAYER M4 ;
      RECT 581.625 0.0 581.965 301.17 ;
      END
    PORT
      LAYER M4 ;
      RECT 583.735 0.0 584.075 301.17 ;
      END
    PORT
      LAYER M4 ;
      RECT 590.025 0.0 590.365 301.17 ;
      END
    PORT
      LAYER M4 ;
      RECT 592.135 0.0 592.475 301.17 ;
      END
    PORT
      LAYER M4 ;
      RECT 598.425 0.0 598.765 301.17 ;
      END
    PORT
      LAYER M4 ;
      RECT 600.535 0.0 600.875 301.17 ;
      END
    PORT
      LAYER M4 ;
      RECT 604.285 0.0 604.435 301.17 ;
      END
    END VDDCE
  PIN VDDPE
    DIRECTION INOUT ;
    USE POWER ;
    PORT
      LAYER M4 ;
      RECT 0.09 0.0 0.24 301.17 ;
      END
    PORT
      LAYER M4 ;
      RECT 2.45 0.0 2.79 301.17 ;
      END
    PORT
      LAYER M4 ;
      RECT 8.17 0.0 8.51 301.17 ;
      END
    PORT
      LAYER M4 ;
      RECT 10.85 0.0 11.19 301.17 ;
      END
    PORT
      LAYER M4 ;
      RECT 16.57 0.0 16.91 301.17 ;
      END
    PORT
      LAYER M4 ;
      RECT 19.25 0.0 19.59 301.17 ;
      END
    PORT
      LAYER M4 ;
      RECT 24.97 0.0 25.31 301.17 ;
      END
    PORT
      LAYER M4 ;
      RECT 27.65 0.0 27.99 301.17 ;
      END
    PORT
      LAYER M4 ;
      RECT 33.37 0.0 33.71 301.17 ;
      END
    PORT
      LAYER M4 ;
      RECT 36.05 0.0 36.39 301.17 ;
      END
    PORT
      LAYER M4 ;
      RECT 41.77 0.0 42.11 301.17 ;
      END
    PORT
      LAYER M4 ;
      RECT 44.45 0.0 44.79 301.17 ;
      END
    PORT
      LAYER M4 ;
      RECT 50.17 0.0 50.51 301.17 ;
      END
    PORT
      LAYER M4 ;
      RECT 52.85 0.0 53.19 301.17 ;
      END
    PORT
      LAYER M4 ;
      RECT 58.57 0.0 58.91 301.17 ;
      END
    PORT
      LAYER M4 ;
      RECT 61.25 0.0 61.59 301.17 ;
      END
    PORT
      LAYER M4 ;
      RECT 66.97 0.0 67.31 301.17 ;
      END
    PORT
      LAYER M4 ;
      RECT 69.65 0.0 69.99 301.17 ;
      END
    PORT
      LAYER M4 ;
      RECT 75.37 0.0 75.71 301.17 ;
      END
    PORT
      LAYER M4 ;
      RECT 78.05 0.0 78.39 301.17 ;
      END
    PORT
      LAYER M4 ;
      RECT 83.77 0.0 84.11 301.17 ;
      END
    PORT
      LAYER M4 ;
      RECT 86.45 0.0 86.79 301.17 ;
      END
    PORT
      LAYER M4 ;
      RECT 92.17 0.0 92.51 301.17 ;
      END
    PORT
      LAYER M4 ;
      RECT 94.85 0.0 95.19 301.17 ;
      END
    PORT
      LAYER M4 ;
      RECT 100.57 0.0 100.91 301.17 ;
      END
    PORT
      LAYER M4 ;
      RECT 103.25 0.0 103.59 301.17 ;
      END
    PORT
      LAYER M4 ;
      RECT 108.97 0.0 109.31 301.17 ;
      END
    PORT
      LAYER M4 ;
      RECT 111.65 0.0 111.99 301.17 ;
      END
    PORT
      LAYER M4 ;
      RECT 117.37 0.0 117.71 301.17 ;
      END
    PORT
      LAYER M4 ;
      RECT 120.05 0.0 120.39 301.17 ;
      END
    PORT
      LAYER M4 ;
      RECT 125.77 0.0 126.11 301.17 ;
      END
    PORT
      LAYER M4 ;
      RECT 128.45 0.0 128.79 301.17 ;
      END
    PORT
      LAYER M4 ;
      RECT 134.17 0.0 134.51 301.17 ;
      END
    PORT
      LAYER M4 ;
      RECT 136.85 0.0 137.19 301.17 ;
      END
    PORT
      LAYER M4 ;
      RECT 142.57 0.0 142.91 301.17 ;
      END
    PORT
      LAYER M4 ;
      RECT 145.25 0.0 145.59 301.17 ;
      END
    PORT
      LAYER M4 ;
      RECT 150.97 0.0 151.31 301.17 ;
      END
    PORT
      LAYER M4 ;
      RECT 153.65 0.0 153.99 301.17 ;
      END
    PORT
      LAYER M4 ;
      RECT 159.37 0.0 159.71 301.17 ;
      END
    PORT
      LAYER M4 ;
      RECT 162.05 0.0 162.39 301.17 ;
      END
    PORT
      LAYER M4 ;
      RECT 167.77 0.0 168.11 301.17 ;
      END
    PORT
      LAYER M4 ;
      RECT 170.45 0.0 170.79 301.17 ;
      END
    PORT
      LAYER M4 ;
      RECT 176.17 0.0 176.51 301.17 ;
      END
    PORT
      LAYER M4 ;
      RECT 178.85 0.0 179.19 301.17 ;
      END
    PORT
      LAYER M4 ;
      RECT 184.57 0.0 184.91 301.17 ;
      END
    PORT
      LAYER M4 ;
      RECT 187.25 0.0 187.59 301.17 ;
      END
    PORT
      LAYER M4 ;
      RECT 192.97 0.0 193.31 301.17 ;
      END
    PORT
      LAYER M4 ;
      RECT 195.65 0.0 195.99 301.17 ;
      END
    PORT
      LAYER M4 ;
      RECT 201.37 0.0 201.71 301.17 ;
      END
    PORT
      LAYER M4 ;
      RECT 204.05 0.0 204.39 301.17 ;
      END
    PORT
      LAYER M4 ;
      RECT 209.77 0.0 210.11 301.17 ;
      END
    PORT
      LAYER M4 ;
      RECT 212.45 0.0 212.79 301.17 ;
      END
    PORT
      LAYER M4 ;
      RECT 218.17 0.0 218.51 301.17 ;
      END
    PORT
      LAYER M4 ;
      RECT 220.85 0.0 221.19 301.17 ;
      END
    PORT
      LAYER M4 ;
      RECT 226.57 0.0 226.91 301.17 ;
      END
    PORT
      LAYER M4 ;
      RECT 229.25 0.0 229.59 301.17 ;
      END
    PORT
      LAYER M4 ;
      RECT 234.97 0.0 235.31 301.17 ;
      END
    PORT
      LAYER M4 ;
      RECT 237.65 0.0 237.99 301.17 ;
      END
    PORT
      LAYER M4 ;
      RECT 243.37 0.0 243.71 301.17 ;
      END
    PORT
      LAYER M4 ;
      RECT 246.05 0.0 246.39 301.17 ;
      END
    PORT
      LAYER M4 ;
      RECT 251.77 0.0 252.11 301.17 ;
      END
    PORT
      LAYER M4 ;
      RECT 254.45 0.0 254.79 301.17 ;
      END
    PORT
      LAYER M4 ;
      RECT 260.17 0.0 260.51 301.17 ;
      END
    PORT
      LAYER M4 ;
      RECT 262.85 0.0 263.19 301.17 ;
      END
    PORT
      LAYER M4 ;
      RECT 268.57 0.0 268.91 301.17 ;
      END
    PORT
      LAYER M4 ;
      RECT 274.15 0.0 274.57 301.17 ;
      END
    PORT
      LAYER M4 ;
      RECT 276.795 0.0 277.215 301.17 ;
      END
    PORT
      LAYER M4 ;
      RECT 284.36 0.0 284.69 301.17 ;
      END
    PORT
      LAYER M4 ;
      RECT 297.29 0.0 297.71 301.17 ;
      END
    PORT
      LAYER M4 ;
      RECT 298.665 0.0 299.095 301.17 ;
      END
    PORT
      LAYER M4 ;
      RECT 299.78 0.0 300.2 301.17 ;
      END
    PORT
      LAYER M4 ;
      RECT 312.6 0.0 313.02 301.17 ;
      END
    PORT
      LAYER M4 ;
      RECT 313.92 0.0 314.34 301.17 ;
      END
    PORT
      LAYER M4 ;
      RECT 315.245 0.0 315.665 301.17 ;
      END
    PORT
      LAYER M4 ;
      RECT 322.9 0.0 323.32 301.17 ;
      END
    PORT
      LAYER M4 ;
      RECT 323.945 0.0 324.365 301.17 ;
      END
    PORT
      LAYER M4 ;
      RECT 327.91 0.0 328.33 301.17 ;
      END
    PORT
      LAYER M4 ;
      RECT 330.565 0.0 330.985 301.17 ;
      END
    PORT
      LAYER M4 ;
      RECT 336.22 0.0 336.56 301.17 ;
      END
    PORT
      LAYER M4 ;
      RECT 341.94 0.0 342.28 301.17 ;
      END
    PORT
      LAYER M4 ;
      RECT 344.62 0.0 344.96 301.17 ;
      END
    PORT
      LAYER M4 ;
      RECT 350.34 0.0 350.68 301.17 ;
      END
    PORT
      LAYER M4 ;
      RECT 353.02 0.0 353.36 301.17 ;
      END
    PORT
      LAYER M4 ;
      RECT 358.74 0.0 359.08 301.17 ;
      END
    PORT
      LAYER M4 ;
      RECT 361.42 0.0 361.76 301.17 ;
      END
    PORT
      LAYER M4 ;
      RECT 367.14 0.0 367.48 301.17 ;
      END
    PORT
      LAYER M4 ;
      RECT 369.82 0.0 370.16 301.17 ;
      END
    PORT
      LAYER M4 ;
      RECT 375.54 0.0 375.88 301.17 ;
      END
    PORT
      LAYER M4 ;
      RECT 378.22 0.0 378.56 301.17 ;
      END
    PORT
      LAYER M4 ;
      RECT 383.94 0.0 384.28 301.17 ;
      END
    PORT
      LAYER M4 ;
      RECT 386.62 0.0 386.96 301.17 ;
      END
    PORT
      LAYER M4 ;
      RECT 392.34 0.0 392.68 301.17 ;
      END
    PORT
      LAYER M4 ;
      RECT 395.02 0.0 395.36 301.17 ;
      END
    PORT
      LAYER M4 ;
      RECT 400.74 0.0 401.08 301.17 ;
      END
    PORT
      LAYER M4 ;
      RECT 403.42 0.0 403.76 301.17 ;
      END
    PORT
      LAYER M4 ;
      RECT 409.14 0.0 409.48 301.17 ;
      END
    PORT
      LAYER M4 ;
      RECT 411.82 0.0 412.16 301.17 ;
      END
    PORT
      LAYER M4 ;
      RECT 417.54 0.0 417.88 301.17 ;
      END
    PORT
      LAYER M4 ;
      RECT 420.22 0.0 420.56 301.17 ;
      END
    PORT
      LAYER M4 ;
      RECT 425.94 0.0 426.28 301.17 ;
      END
    PORT
      LAYER M4 ;
      RECT 428.62 0.0 428.96 301.17 ;
      END
    PORT
      LAYER M4 ;
      RECT 434.34 0.0 434.68 301.17 ;
      END
    PORT
      LAYER M4 ;
      RECT 437.02 0.0 437.36 301.17 ;
      END
    PORT
      LAYER M4 ;
      RECT 442.74 0.0 443.08 301.17 ;
      END
    PORT
      LAYER M4 ;
      RECT 445.42 0.0 445.76 301.17 ;
      END
    PORT
      LAYER M4 ;
      RECT 451.14 0.0 451.48 301.17 ;
      END
    PORT
      LAYER M4 ;
      RECT 453.82 0.0 454.16 301.17 ;
      END
    PORT
      LAYER M4 ;
      RECT 459.54 0.0 459.88 301.17 ;
      END
    PORT
      LAYER M4 ;
      RECT 462.22 0.0 462.56 301.17 ;
      END
    PORT
      LAYER M4 ;
      RECT 467.94 0.0 468.28 301.17 ;
      END
    PORT
      LAYER M4 ;
      RECT 470.62 0.0 470.96 301.17 ;
      END
    PORT
      LAYER M4 ;
      RECT 476.34 0.0 476.68 301.17 ;
      END
    PORT
      LAYER M4 ;
      RECT 479.02 0.0 479.36 301.17 ;
      END
    PORT
      LAYER M4 ;
      RECT 484.74 0.0 485.08 301.17 ;
      END
    PORT
      LAYER M4 ;
      RECT 487.42 0.0 487.76 301.17 ;
      END
    PORT
      LAYER M4 ;
      RECT 493.14 0.0 493.48 301.17 ;
      END
    PORT
      LAYER M4 ;
      RECT 495.82 0.0 496.16 301.17 ;
      END
    PORT
      LAYER M4 ;
      RECT 501.54 0.0 501.88 301.17 ;
      END
    PORT
      LAYER M4 ;
      RECT 504.22 0.0 504.56 301.17 ;
      END
    PORT
      LAYER M4 ;
      RECT 509.94 0.0 510.28 301.17 ;
      END
    PORT
      LAYER M4 ;
      RECT 512.62 0.0 512.96 301.17 ;
      END
    PORT
      LAYER M4 ;
      RECT 518.34 0.0 518.68 301.17 ;
      END
    PORT
      LAYER M4 ;
      RECT 521.02 0.0 521.36 301.17 ;
      END
    PORT
      LAYER M4 ;
      RECT 526.74 0.0 527.08 301.17 ;
      END
    PORT
      LAYER M4 ;
      RECT 529.42 0.0 529.76 301.17 ;
      END
    PORT
      LAYER M4 ;
      RECT 535.14 0.0 535.48 301.17 ;
      END
    PORT
      LAYER M4 ;
      RECT 537.82 0.0 538.16 301.17 ;
      END
    PORT
      LAYER M4 ;
      RECT 543.54 0.0 543.88 301.17 ;
      END
    PORT
      LAYER M4 ;
      RECT 546.22 0.0 546.56 301.17 ;
      END
    PORT
      LAYER M4 ;
      RECT 551.94 0.0 552.28 301.17 ;
      END
    PORT
      LAYER M4 ;
      RECT 554.62 0.0 554.96 301.17 ;
      END
    PORT
      LAYER M4 ;
      RECT 560.34 0.0 560.68 301.17 ;
      END
    PORT
      LAYER M4 ;
      RECT 563.02 0.0 563.36 301.17 ;
      END
    PORT
      LAYER M4 ;
      RECT 568.74 0.0 569.08 301.17 ;
      END
    PORT
      LAYER M4 ;
      RECT 571.42 0.0 571.76 301.17 ;
      END
    PORT
      LAYER M4 ;
      RECT 577.14 0.0 577.48 301.17 ;
      END
    PORT
      LAYER M4 ;
      RECT 579.82 0.0 580.16 301.17 ;
      END
    PORT
      LAYER M4 ;
      RECT 585.54 0.0 585.88 301.17 ;
      END
    PORT
      LAYER M4 ;
      RECT 588.22 0.0 588.56 301.17 ;
      END
    PORT
      LAYER M4 ;
      RECT 593.94 0.0 594.28 301.17 ;
      END
    PORT
      LAYER M4 ;
      RECT 596.62 0.0 596.96 301.17 ;
      END
    PORT
      LAYER M4 ;
      RECT 602.34 0.0 602.68 301.17 ;
      END
    PORT
      LAYER M4 ;
      RECT 604.89 0.0 605.04 301.17 ;
      END
    END VDDPE
  PIN VSSE
    DIRECTION INOUT ;
    USE GROUND ;
    PORT
      LAYER M4 ;
      RECT 0.38 0.0 0.53 301.17 ;
      END
    PORT
      LAYER M4 ;
      RECT 1.0 0.0 1.15 301.17 ;
      END
    PORT
      LAYER M4 ;
      RECT 1.675 0.0 2.015 301.17 ;
      END
    PORT
      LAYER M4 ;
      RECT 3.2 0.0 3.54 301.17 ;
      END
    PORT
      LAYER M4 ;
      RECT 7.415 0.0 7.755 301.17 ;
      END
    PORT
      LAYER M4 ;
      RECT 8.92 0.0 9.26 301.17 ;
      END
    PORT
      LAYER M4 ;
      RECT 10.075 0.0 10.415 301.17 ;
      END
    PORT
      LAYER M4 ;
      RECT 11.6 0.0 11.94 301.17 ;
      END
    PORT
      LAYER M4 ;
      RECT 15.815 0.0 16.155 301.17 ;
      END
    PORT
      LAYER M4 ;
      RECT 17.32 0.0 17.66 301.17 ;
      END
    PORT
      LAYER M4 ;
      RECT 18.475 0.0 18.815 301.17 ;
      END
    PORT
      LAYER M4 ;
      RECT 20.0 0.0 20.34 301.17 ;
      END
    PORT
      LAYER M4 ;
      RECT 24.215 0.0 24.555 301.17 ;
      END
    PORT
      LAYER M4 ;
      RECT 25.72 0.0 26.06 301.17 ;
      END
    PORT
      LAYER M4 ;
      RECT 26.875 0.0 27.215 301.17 ;
      END
    PORT
      LAYER M4 ;
      RECT 28.4 0.0 28.74 301.17 ;
      END
    PORT
      LAYER M4 ;
      RECT 32.615 0.0 32.955 301.17 ;
      END
    PORT
      LAYER M4 ;
      RECT 34.12 0.0 34.46 301.17 ;
      END
    PORT
      LAYER M4 ;
      RECT 35.275 0.0 35.615 301.17 ;
      END
    PORT
      LAYER M4 ;
      RECT 36.8 0.0 37.14 301.17 ;
      END
    PORT
      LAYER M4 ;
      RECT 41.015 0.0 41.355 301.17 ;
      END
    PORT
      LAYER M4 ;
      RECT 42.52 0.0 42.86 301.17 ;
      END
    PORT
      LAYER M4 ;
      RECT 43.675 0.0 44.015 301.17 ;
      END
    PORT
      LAYER M4 ;
      RECT 45.2 0.0 45.54 301.17 ;
      END
    PORT
      LAYER M4 ;
      RECT 49.415 0.0 49.755 301.17 ;
      END
    PORT
      LAYER M4 ;
      RECT 50.92 0.0 51.26 301.17 ;
      END
    PORT
      LAYER M4 ;
      RECT 52.075 0.0 52.415 301.17 ;
      END
    PORT
      LAYER M4 ;
      RECT 53.6 0.0 53.94 301.17 ;
      END
    PORT
      LAYER M4 ;
      RECT 57.815 0.0 58.155 301.17 ;
      END
    PORT
      LAYER M4 ;
      RECT 59.32 0.0 59.66 301.17 ;
      END
    PORT
      LAYER M4 ;
      RECT 60.475 0.0 60.815 301.17 ;
      END
    PORT
      LAYER M4 ;
      RECT 62.0 0.0 62.34 301.17 ;
      END
    PORT
      LAYER M4 ;
      RECT 66.215 0.0 66.555 301.17 ;
      END
    PORT
      LAYER M4 ;
      RECT 67.72 0.0 68.06 301.17 ;
      END
    PORT
      LAYER M4 ;
      RECT 68.875 0.0 69.215 301.17 ;
      END
    PORT
      LAYER M4 ;
      RECT 70.4 0.0 70.74 301.17 ;
      END
    PORT
      LAYER M4 ;
      RECT 74.615 0.0 74.955 301.17 ;
      END
    PORT
      LAYER M4 ;
      RECT 76.12 0.0 76.46 301.17 ;
      END
    PORT
      LAYER M4 ;
      RECT 77.275 0.0 77.615 301.17 ;
      END
    PORT
      LAYER M4 ;
      RECT 78.8 0.0 79.14 301.17 ;
      END
    PORT
      LAYER M4 ;
      RECT 83.015 0.0 83.355 301.17 ;
      END
    PORT
      LAYER M4 ;
      RECT 84.52 0.0 84.86 301.17 ;
      END
    PORT
      LAYER M4 ;
      RECT 85.675 0.0 86.015 301.17 ;
      END
    PORT
      LAYER M4 ;
      RECT 87.2 0.0 87.54 301.17 ;
      END
    PORT
      LAYER M4 ;
      RECT 91.415 0.0 91.755 301.17 ;
      END
    PORT
      LAYER M4 ;
      RECT 92.92 0.0 93.26 301.17 ;
      END
    PORT
      LAYER M4 ;
      RECT 94.075 0.0 94.415 301.17 ;
      END
    PORT
      LAYER M4 ;
      RECT 95.6 0.0 95.94 301.17 ;
      END
    PORT
      LAYER M4 ;
      RECT 99.815 0.0 100.155 301.17 ;
      END
    PORT
      LAYER M4 ;
      RECT 101.32 0.0 101.66 301.17 ;
      END
    PORT
      LAYER M4 ;
      RECT 102.475 0.0 102.815 301.17 ;
      END
    PORT
      LAYER M4 ;
      RECT 104.0 0.0 104.34 301.17 ;
      END
    PORT
      LAYER M4 ;
      RECT 108.215 0.0 108.555 301.17 ;
      END
    PORT
      LAYER M4 ;
      RECT 109.72 0.0 110.06 301.17 ;
      END
    PORT
      LAYER M4 ;
      RECT 110.875 0.0 111.215 301.17 ;
      END
    PORT
      LAYER M4 ;
      RECT 112.4 0.0 112.74 301.17 ;
      END
    PORT
      LAYER M4 ;
      RECT 116.615 0.0 116.955 301.17 ;
      END
    PORT
      LAYER M4 ;
      RECT 118.12 0.0 118.46 301.17 ;
      END
    PORT
      LAYER M4 ;
      RECT 119.275 0.0 119.615 301.17 ;
      END
    PORT
      LAYER M4 ;
      RECT 120.8 0.0 121.14 301.17 ;
      END
    PORT
      LAYER M4 ;
      RECT 125.015 0.0 125.355 301.17 ;
      END
    PORT
      LAYER M4 ;
      RECT 126.52 0.0 126.86 301.17 ;
      END
    PORT
      LAYER M4 ;
      RECT 127.675 0.0 128.015 301.17 ;
      END
    PORT
      LAYER M4 ;
      RECT 129.2 0.0 129.54 301.17 ;
      END
    PORT
      LAYER M4 ;
      RECT 133.415 0.0 133.755 301.17 ;
      END
    PORT
      LAYER M4 ;
      RECT 134.92 0.0 135.26 301.17 ;
      END
    PORT
      LAYER M4 ;
      RECT 136.075 0.0 136.415 301.17 ;
      END
    PORT
      LAYER M4 ;
      RECT 137.6 0.0 137.94 301.17 ;
      END
    PORT
      LAYER M4 ;
      RECT 141.815 0.0 142.155 301.17 ;
      END
    PORT
      LAYER M4 ;
      RECT 143.32 0.0 143.66 301.17 ;
      END
    PORT
      LAYER M4 ;
      RECT 144.475 0.0 144.815 301.17 ;
      END
    PORT
      LAYER M4 ;
      RECT 146.0 0.0 146.34 301.17 ;
      END
    PORT
      LAYER M4 ;
      RECT 150.215 0.0 150.555 301.17 ;
      END
    PORT
      LAYER M4 ;
      RECT 151.72 0.0 152.06 301.17 ;
      END
    PORT
      LAYER M4 ;
      RECT 152.875 0.0 153.215 301.17 ;
      END
    PORT
      LAYER M4 ;
      RECT 154.4 0.0 154.74 301.17 ;
      END
    PORT
      LAYER M4 ;
      RECT 158.615 0.0 158.955 301.17 ;
      END
    PORT
      LAYER M4 ;
      RECT 160.12 0.0 160.46 301.17 ;
      END
    PORT
      LAYER M4 ;
      RECT 161.275 0.0 161.615 301.17 ;
      END
    PORT
      LAYER M4 ;
      RECT 162.8 0.0 163.14 301.17 ;
      END
    PORT
      LAYER M4 ;
      RECT 167.015 0.0 167.355 301.17 ;
      END
    PORT
      LAYER M4 ;
      RECT 168.52 0.0 168.86 301.17 ;
      END
    PORT
      LAYER M4 ;
      RECT 169.675 0.0 170.015 301.17 ;
      END
    PORT
      LAYER M4 ;
      RECT 171.2 0.0 171.54 301.17 ;
      END
    PORT
      LAYER M4 ;
      RECT 175.415 0.0 175.755 301.17 ;
      END
    PORT
      LAYER M4 ;
      RECT 176.92 0.0 177.26 301.17 ;
      END
    PORT
      LAYER M4 ;
      RECT 178.075 0.0 178.415 301.17 ;
      END
    PORT
      LAYER M4 ;
      RECT 179.6 0.0 179.94 301.17 ;
      END
    PORT
      LAYER M4 ;
      RECT 183.815 0.0 184.155 301.17 ;
      END
    PORT
      LAYER M4 ;
      RECT 185.32 0.0 185.66 301.17 ;
      END
    PORT
      LAYER M4 ;
      RECT 186.475 0.0 186.815 301.17 ;
      END
    PORT
      LAYER M4 ;
      RECT 188.0 0.0 188.34 301.17 ;
      END
    PORT
      LAYER M4 ;
      RECT 192.215 0.0 192.555 301.17 ;
      END
    PORT
      LAYER M4 ;
      RECT 193.72 0.0 194.06 301.17 ;
      END
    PORT
      LAYER M4 ;
      RECT 194.875 0.0 195.215 301.17 ;
      END
    PORT
      LAYER M4 ;
      RECT 196.4 0.0 196.74 301.17 ;
      END
    PORT
      LAYER M4 ;
      RECT 200.615 0.0 200.955 301.17 ;
      END
    PORT
      LAYER M4 ;
      RECT 202.12 0.0 202.46 301.17 ;
      END
    PORT
      LAYER M4 ;
      RECT 203.275 0.0 203.615 301.17 ;
      END
    PORT
      LAYER M4 ;
      RECT 204.8 0.0 205.14 301.17 ;
      END
    PORT
      LAYER M4 ;
      RECT 209.015 0.0 209.355 301.17 ;
      END
    PORT
      LAYER M4 ;
      RECT 210.52 0.0 210.86 301.17 ;
      END
    PORT
      LAYER M4 ;
      RECT 211.675 0.0 212.015 301.17 ;
      END
    PORT
      LAYER M4 ;
      RECT 213.2 0.0 213.54 301.17 ;
      END
    PORT
      LAYER M4 ;
      RECT 217.415 0.0 217.755 301.17 ;
      END
    PORT
      LAYER M4 ;
      RECT 218.92 0.0 219.26 301.17 ;
      END
    PORT
      LAYER M4 ;
      RECT 220.075 0.0 220.415 301.17 ;
      END
    PORT
      LAYER M4 ;
      RECT 221.6 0.0 221.94 301.17 ;
      END
    PORT
      LAYER M4 ;
      RECT 225.815 0.0 226.155 301.17 ;
      END
    PORT
      LAYER M4 ;
      RECT 227.32 0.0 227.66 301.17 ;
      END
    PORT
      LAYER M4 ;
      RECT 228.475 0.0 228.815 301.17 ;
      END
    PORT
      LAYER M4 ;
      RECT 230.0 0.0 230.34 301.17 ;
      END
    PORT
      LAYER M4 ;
      RECT 234.215 0.0 234.555 301.17 ;
      END
    PORT
      LAYER M4 ;
      RECT 235.72 0.0 236.06 301.17 ;
      END
    PORT
      LAYER M4 ;
      RECT 236.875 0.0 237.215 301.17 ;
      END
    PORT
      LAYER M4 ;
      RECT 238.4 0.0 238.74 301.17 ;
      END
    PORT
      LAYER M4 ;
      RECT 242.615 0.0 242.955 301.17 ;
      END
    PORT
      LAYER M4 ;
      RECT 244.12 0.0 244.46 301.17 ;
      END
    PORT
      LAYER M4 ;
      RECT 245.275 0.0 245.615 301.17 ;
      END
    PORT
      LAYER M4 ;
      RECT 246.8 0.0 247.14 301.17 ;
      END
    PORT
      LAYER M4 ;
      RECT 251.015 0.0 251.355 301.17 ;
      END
    PORT
      LAYER M4 ;
      RECT 252.52 0.0 252.86 301.17 ;
      END
    PORT
      LAYER M4 ;
      RECT 253.675 0.0 254.015 301.17 ;
      END
    PORT
      LAYER M4 ;
      RECT 255.2 0.0 255.54 301.17 ;
      END
    PORT
      LAYER M4 ;
      RECT 259.415 0.0 259.755 301.17 ;
      END
    PORT
      LAYER M4 ;
      RECT 260.92 0.0 261.26 301.17 ;
      END
    PORT
      LAYER M4 ;
      RECT 262.075 0.0 262.415 301.17 ;
      END
    PORT
      LAYER M4 ;
      RECT 263.6 0.0 263.94 301.17 ;
      END
    PORT
      LAYER M4 ;
      RECT 267.815 0.0 268.155 301.17 ;
      END
    PORT
      LAYER M4 ;
      RECT 269.32 0.0 269.66 301.17 ;
      END
    PORT
      LAYER M4 ;
      RECT 272.825 0.0 273.255 301.17 ;
      END
    PORT
      LAYER M4 ;
      RECT 275.47 0.0 275.89 301.17 ;
      END
    PORT
      LAYER M4 ;
      RECT 278.115 0.0 278.535 301.17 ;
      END
    PORT
      LAYER M4 ;
      RECT 280.83 0.0 281.16 301.17 ;
      END
    PORT
      LAYER M4 ;
      RECT 288.185 0.0 288.605 301.17 ;
      END
    PORT
      LAYER M4 ;
      RECT 290.785 0.0 291.205 301.17 ;
      END
    PORT
      LAYER M4 ;
      RECT 291.46 0.0 291.79 301.17 ;
      END
    PORT
      LAYER M4 ;
      RECT 293.385 0.0 293.805 301.17 ;
      END
    PORT
      LAYER M4 ;
      RECT 295.995 0.0 296.415 301.17 ;
      END
    PORT
      LAYER M4 ;
      RECT 297.985 0.0 298.405 301.17 ;
      END
    PORT
      LAYER M4 ;
      RECT 303.525 0.0 303.855 301.17 ;
      END
    PORT
      LAYER M4 ;
      RECT 308.63 0.0 309.05 301.17 ;
      END
    PORT
      LAYER M4 ;
      RECT 311.275 0.0 311.695 301.17 ;
      END
    PORT
      LAYER M4 ;
      RECT 316.57 0.0 316.99 301.17 ;
      END
    PORT
      LAYER M4 ;
      RECT 317.29 0.0 317.62 301.17 ;
      END
    PORT
      LAYER M4 ;
      RECT 319.215 0.0 319.635 301.17 ;
      END
    PORT
      LAYER M4 ;
      RECT 321.87 0.0 322.29 301.17 ;
      END
    PORT
      LAYER M4 ;
      RECT 326.585 0.0 327.005 301.17 ;
      END
    PORT
      LAYER M4 ;
      RECT 329.24 0.0 329.66 301.17 ;
      END
    PORT
      LAYER M4 ;
      RECT 331.885 0.0 332.305 301.17 ;
      END
    PORT
      LAYER M4 ;
      RECT 335.47 0.0 335.81 301.17 ;
      END
    PORT
      LAYER M4 ;
      RECT 336.975 0.0 337.315 301.17 ;
      END
    PORT
      LAYER M4 ;
      RECT 341.19 0.0 341.53 301.17 ;
      END
    PORT
      LAYER M4 ;
      RECT 342.715 0.0 343.055 301.17 ;
      END
    PORT
      LAYER M4 ;
      RECT 343.87 0.0 344.21 301.17 ;
      END
    PORT
      LAYER M4 ;
      RECT 345.375 0.0 345.715 301.17 ;
      END
    PORT
      LAYER M4 ;
      RECT 349.59 0.0 349.93 301.17 ;
      END
    PORT
      LAYER M4 ;
      RECT 351.115 0.0 351.455 301.17 ;
      END
    PORT
      LAYER M4 ;
      RECT 352.27 0.0 352.61 301.17 ;
      END
    PORT
      LAYER M4 ;
      RECT 353.775 0.0 354.115 301.17 ;
      END
    PORT
      LAYER M4 ;
      RECT 357.99 0.0 358.33 301.17 ;
      END
    PORT
      LAYER M4 ;
      RECT 359.515 0.0 359.855 301.17 ;
      END
    PORT
      LAYER M4 ;
      RECT 360.67 0.0 361.01 301.17 ;
      END
    PORT
      LAYER M4 ;
      RECT 362.175 0.0 362.515 301.17 ;
      END
    PORT
      LAYER M4 ;
      RECT 366.39 0.0 366.73 301.17 ;
      END
    PORT
      LAYER M4 ;
      RECT 367.915 0.0 368.255 301.17 ;
      END
    PORT
      LAYER M4 ;
      RECT 369.07 0.0 369.41 301.17 ;
      END
    PORT
      LAYER M4 ;
      RECT 370.575 0.0 370.915 301.17 ;
      END
    PORT
      LAYER M4 ;
      RECT 374.79 0.0 375.13 301.17 ;
      END
    PORT
      LAYER M4 ;
      RECT 376.315 0.0 376.655 301.17 ;
      END
    PORT
      LAYER M4 ;
      RECT 377.47 0.0 377.81 301.17 ;
      END
    PORT
      LAYER M4 ;
      RECT 378.975 0.0 379.315 301.17 ;
      END
    PORT
      LAYER M4 ;
      RECT 383.19 0.0 383.53 301.17 ;
      END
    PORT
      LAYER M4 ;
      RECT 384.715 0.0 385.055 301.17 ;
      END
    PORT
      LAYER M4 ;
      RECT 385.87 0.0 386.21 301.17 ;
      END
    PORT
      LAYER M4 ;
      RECT 387.375 0.0 387.715 301.17 ;
      END
    PORT
      LAYER M4 ;
      RECT 391.59 0.0 391.93 301.17 ;
      END
    PORT
      LAYER M4 ;
      RECT 393.115 0.0 393.455 301.17 ;
      END
    PORT
      LAYER M4 ;
      RECT 394.27 0.0 394.61 301.17 ;
      END
    PORT
      LAYER M4 ;
      RECT 395.775 0.0 396.115 301.17 ;
      END
    PORT
      LAYER M4 ;
      RECT 399.99 0.0 400.33 301.17 ;
      END
    PORT
      LAYER M4 ;
      RECT 401.515 0.0 401.855 301.17 ;
      END
    PORT
      LAYER M4 ;
      RECT 402.67 0.0 403.01 301.17 ;
      END
    PORT
      LAYER M4 ;
      RECT 404.175 0.0 404.515 301.17 ;
      END
    PORT
      LAYER M4 ;
      RECT 408.39 0.0 408.73 301.17 ;
      END
    PORT
      LAYER M4 ;
      RECT 409.915 0.0 410.255 301.17 ;
      END
    PORT
      LAYER M4 ;
      RECT 411.07 0.0 411.41 301.17 ;
      END
    PORT
      LAYER M4 ;
      RECT 412.575 0.0 412.915 301.17 ;
      END
    PORT
      LAYER M4 ;
      RECT 416.79 0.0 417.13 301.17 ;
      END
    PORT
      LAYER M4 ;
      RECT 418.315 0.0 418.655 301.17 ;
      END
    PORT
      LAYER M4 ;
      RECT 419.47 0.0 419.81 301.17 ;
      END
    PORT
      LAYER M4 ;
      RECT 420.975 0.0 421.315 301.17 ;
      END
    PORT
      LAYER M4 ;
      RECT 425.19 0.0 425.53 301.17 ;
      END
    PORT
      LAYER M4 ;
      RECT 426.715 0.0 427.055 301.17 ;
      END
    PORT
      LAYER M4 ;
      RECT 427.87 0.0 428.21 301.17 ;
      END
    PORT
      LAYER M4 ;
      RECT 429.375 0.0 429.715 301.17 ;
      END
    PORT
      LAYER M4 ;
      RECT 433.59 0.0 433.93 301.17 ;
      END
    PORT
      LAYER M4 ;
      RECT 435.115 0.0 435.455 301.17 ;
      END
    PORT
      LAYER M4 ;
      RECT 436.27 0.0 436.61 301.17 ;
      END
    PORT
      LAYER M4 ;
      RECT 437.775 0.0 438.115 301.17 ;
      END
    PORT
      LAYER M4 ;
      RECT 441.99 0.0 442.33 301.17 ;
      END
    PORT
      LAYER M4 ;
      RECT 443.515 0.0 443.855 301.17 ;
      END
    PORT
      LAYER M4 ;
      RECT 444.67 0.0 445.01 301.17 ;
      END
    PORT
      LAYER M4 ;
      RECT 446.175 0.0 446.515 301.17 ;
      END
    PORT
      LAYER M4 ;
      RECT 450.39 0.0 450.73 301.17 ;
      END
    PORT
      LAYER M4 ;
      RECT 451.915 0.0 452.255 301.17 ;
      END
    PORT
      LAYER M4 ;
      RECT 453.07 0.0 453.41 301.17 ;
      END
    PORT
      LAYER M4 ;
      RECT 454.575 0.0 454.915 301.17 ;
      END
    PORT
      LAYER M4 ;
      RECT 458.79 0.0 459.13 301.17 ;
      END
    PORT
      LAYER M4 ;
      RECT 460.315 0.0 460.655 301.17 ;
      END
    PORT
      LAYER M4 ;
      RECT 461.47 0.0 461.81 301.17 ;
      END
    PORT
      LAYER M4 ;
      RECT 462.975 0.0 463.315 301.17 ;
      END
    PORT
      LAYER M4 ;
      RECT 467.19 0.0 467.53 301.17 ;
      END
    PORT
      LAYER M4 ;
      RECT 468.715 0.0 469.055 301.17 ;
      END
    PORT
      LAYER M4 ;
      RECT 469.87 0.0 470.21 301.17 ;
      END
    PORT
      LAYER M4 ;
      RECT 471.375 0.0 471.715 301.17 ;
      END
    PORT
      LAYER M4 ;
      RECT 475.59 0.0 475.93 301.17 ;
      END
    PORT
      LAYER M4 ;
      RECT 477.115 0.0 477.455 301.17 ;
      END
    PORT
      LAYER M4 ;
      RECT 478.27 0.0 478.61 301.17 ;
      END
    PORT
      LAYER M4 ;
      RECT 479.775 0.0 480.115 301.17 ;
      END
    PORT
      LAYER M4 ;
      RECT 483.99 0.0 484.33 301.17 ;
      END
    PORT
      LAYER M4 ;
      RECT 485.515 0.0 485.855 301.17 ;
      END
    PORT
      LAYER M4 ;
      RECT 486.67 0.0 487.01 301.17 ;
      END
    PORT
      LAYER M4 ;
      RECT 488.175 0.0 488.515 301.17 ;
      END
    PORT
      LAYER M4 ;
      RECT 492.39 0.0 492.73 301.17 ;
      END
    PORT
      LAYER M4 ;
      RECT 493.915 0.0 494.255 301.17 ;
      END
    PORT
      LAYER M4 ;
      RECT 495.07 0.0 495.41 301.17 ;
      END
    PORT
      LAYER M4 ;
      RECT 496.575 0.0 496.915 301.17 ;
      END
    PORT
      LAYER M4 ;
      RECT 500.79 0.0 501.13 301.17 ;
      END
    PORT
      LAYER M4 ;
      RECT 502.315 0.0 502.655 301.17 ;
      END
    PORT
      LAYER M4 ;
      RECT 503.47 0.0 503.81 301.17 ;
      END
    PORT
      LAYER M4 ;
      RECT 504.975 0.0 505.315 301.17 ;
      END
    PORT
      LAYER M4 ;
      RECT 509.19 0.0 509.53 301.17 ;
      END
    PORT
      LAYER M4 ;
      RECT 510.715 0.0 511.055 301.17 ;
      END
    PORT
      LAYER M4 ;
      RECT 511.87 0.0 512.21 301.17 ;
      END
    PORT
      LAYER M4 ;
      RECT 513.375 0.0 513.715 301.17 ;
      END
    PORT
      LAYER M4 ;
      RECT 517.59 0.0 517.93 301.17 ;
      END
    PORT
      LAYER M4 ;
      RECT 519.115 0.0 519.455 301.17 ;
      END
    PORT
      LAYER M4 ;
      RECT 520.27 0.0 520.61 301.17 ;
      END
    PORT
      LAYER M4 ;
      RECT 521.775 0.0 522.115 301.17 ;
      END
    PORT
      LAYER M4 ;
      RECT 525.99 0.0 526.33 301.17 ;
      END
    PORT
      LAYER M4 ;
      RECT 527.515 0.0 527.855 301.17 ;
      END
    PORT
      LAYER M4 ;
      RECT 528.67 0.0 529.01 301.17 ;
      END
    PORT
      LAYER M4 ;
      RECT 530.175 0.0 530.515 301.17 ;
      END
    PORT
      LAYER M4 ;
      RECT 534.39 0.0 534.73 301.17 ;
      END
    PORT
      LAYER M4 ;
      RECT 535.915 0.0 536.255 301.17 ;
      END
    PORT
      LAYER M4 ;
      RECT 537.07 0.0 537.41 301.17 ;
      END
    PORT
      LAYER M4 ;
      RECT 538.575 0.0 538.915 301.17 ;
      END
    PORT
      LAYER M4 ;
      RECT 542.79 0.0 543.13 301.17 ;
      END
    PORT
      LAYER M4 ;
      RECT 544.315 0.0 544.655 301.17 ;
      END
    PORT
      LAYER M4 ;
      RECT 545.47 0.0 545.81 301.17 ;
      END
    PORT
      LAYER M4 ;
      RECT 546.975 0.0 547.315 301.17 ;
      END
    PORT
      LAYER M4 ;
      RECT 551.19 0.0 551.53 301.17 ;
      END
    PORT
      LAYER M4 ;
      RECT 552.715 0.0 553.055 301.17 ;
      END
    PORT
      LAYER M4 ;
      RECT 553.87 0.0 554.21 301.17 ;
      END
    PORT
      LAYER M4 ;
      RECT 555.375 0.0 555.715 301.17 ;
      END
    PORT
      LAYER M4 ;
      RECT 559.59 0.0 559.93 301.17 ;
      END
    PORT
      LAYER M4 ;
      RECT 561.115 0.0 561.455 301.17 ;
      END
    PORT
      LAYER M4 ;
      RECT 562.27 0.0 562.61 301.17 ;
      END
    PORT
      LAYER M4 ;
      RECT 563.775 0.0 564.115 301.17 ;
      END
    PORT
      LAYER M4 ;
      RECT 567.99 0.0 568.33 301.17 ;
      END
    PORT
      LAYER M4 ;
      RECT 569.515 0.0 569.855 301.17 ;
      END
    PORT
      LAYER M4 ;
      RECT 570.67 0.0 571.01 301.17 ;
      END
    PORT
      LAYER M4 ;
      RECT 572.175 0.0 572.515 301.17 ;
      END
    PORT
      LAYER M4 ;
      RECT 576.39 0.0 576.73 301.17 ;
      END
    PORT
      LAYER M4 ;
      RECT 577.915 0.0 578.255 301.17 ;
      END
    PORT
      LAYER M4 ;
      RECT 579.07 0.0 579.41 301.17 ;
      END
    PORT
      LAYER M4 ;
      RECT 580.575 0.0 580.915 301.17 ;
      END
    PORT
      LAYER M4 ;
      RECT 584.79 0.0 585.13 301.17 ;
      END
    PORT
      LAYER M4 ;
      RECT 586.315 0.0 586.655 301.17 ;
      END
    PORT
      LAYER M4 ;
      RECT 587.47 0.0 587.81 301.17 ;
      END
    PORT
      LAYER M4 ;
      RECT 588.975 0.0 589.315 301.17 ;
      END
    PORT
      LAYER M4 ;
      RECT 593.19 0.0 593.53 301.17 ;
      END
    PORT
      LAYER M4 ;
      RECT 594.715 0.0 595.055 301.17 ;
      END
    PORT
      LAYER M4 ;
      RECT 595.87 0.0 596.21 301.17 ;
      END
    PORT
      LAYER M4 ;
      RECT 597.375 0.0 597.715 301.17 ;
      END
    PORT
      LAYER M4 ;
      RECT 601.59 0.0 601.93 301.17 ;
      END
    PORT
      LAYER M4 ;
      RECT 603.115 0.0 603.455 301.17 ;
      END
    PORT
      LAYER M4 ;
      RECT 603.98 0.0 604.13 301.17 ;
      END
    PORT
      LAYER M4 ;
      RECT 604.6 0.0 604.75 301.17 ;
      END
    END VSSE
  OBS
    #otc obstructions
    LAYER M1 DESIGNRULEWIDTH 0.1 ;
    RECT 604.46 0.0 605.13 0.42 ;
    RECT 600.41 0.0 604.04 0.42 ;
    RECT 599.355 0.0 599.515 0.42 ;
    RECT 598.3 0.0 598.935 0.42 ;
    RECT 596.0 0.0 597.88 0.42 ;
    RECT 583.61 0.0 595.58 0.42 ;
    RECT 582.555 0.0 582.715 0.42 ;
    RECT 581.5 0.0 582.135 0.42 ;
    RECT 579.2 0.0 581.08 0.42 ;
    RECT 566.81 0.0 578.78 0.42 ;
    RECT 565.755 0.0 565.915 0.42 ;
    RECT 564.7 0.0 565.335 0.42 ;
    RECT 562.4 0.0 564.28 0.42 ;
    RECT 550.01 0.0 561.98 0.42 ;
    RECT 548.955 0.0 549.115 0.42 ;
    RECT 547.9 0.0 548.535 0.42 ;
    RECT 545.6 0.0 547.48 0.42 ;
    RECT 533.21 0.0 545.18 0.42 ;
    RECT 532.155 0.0 532.315 0.42 ;
    RECT 531.1 0.0 531.735 0.42 ;
    RECT 528.8 0.0 530.68 0.42 ;
    RECT 516.41 0.0 528.38 0.42 ;
    RECT 515.355 0.0 515.515 0.42 ;
    RECT 514.3 0.0 514.935 0.42 ;
    RECT 512.0 0.0 513.88 0.42 ;
    RECT 499.61 0.0 511.58 0.42 ;
    RECT 498.555 0.0 498.715 0.42 ;
    RECT 497.5 0.0 498.135 0.42 ;
    RECT 495.2 0.0 497.08 0.42 ;
    RECT 482.81 0.0 494.78 0.42 ;
    RECT 481.755 0.0 481.915 0.42 ;
    RECT 480.7 0.0 481.335 0.42 ;
    RECT 478.4 0.0 480.28 0.42 ;
    RECT 466.01 0.0 477.98 0.42 ;
    RECT 464.955 0.0 465.115 0.42 ;
    RECT 463.9 0.0 464.535 0.42 ;
    RECT 461.6 0.0 463.48 0.42 ;
    RECT 449.21 0.0 461.18 0.42 ;
    RECT 448.155 0.0 448.315 0.42 ;
    RECT 447.1 0.0 447.735 0.42 ;
    RECT 444.8 0.0 446.68 0.42 ;
    RECT 432.41 0.0 444.38 0.42 ;
    RECT 431.355 0.0 431.515 0.42 ;
    RECT 430.3 0.0 430.935 0.42 ;
    RECT 428.0 0.0 429.88 0.42 ;
    RECT 415.61 0.0 427.58 0.42 ;
    RECT 414.555 0.0 414.715 0.42 ;
    RECT 413.5 0.0 414.135 0.42 ;
    RECT 411.2 0.0 413.08 0.42 ;
    RECT 398.81 0.0 410.78 0.42 ;
    RECT 397.755 0.0 397.915 0.42 ;
    RECT 396.7 0.0 397.335 0.42 ;
    RECT 394.4 0.0 396.28 0.42 ;
    RECT 382.01 0.0 393.98 0.42 ;
    RECT 380.955 0.0 381.115 0.42 ;
    RECT 379.9 0.0 380.535 0.42 ;
    RECT 377.6 0.0 379.48 0.42 ;
    RECT 365.21 0.0 377.18 0.42 ;
    RECT 364.155 0.0 364.315 0.42 ;
    RECT 363.1 0.0 363.735 0.42 ;
    RECT 360.8 0.0 362.68 0.42 ;
    RECT 348.41 0.0 360.38 0.42 ;
    RECT 347.355 0.0 347.515 0.42 ;
    RECT 346.3 0.0 346.935 0.42 ;
    RECT 344.0 0.0 345.88 0.42 ;
    RECT 328.095 0.0 343.58 0.42 ;
    RECT 326.285 0.0 326.77 0.42 ;
    RECT 323.425 0.0 325.37 0.42 ;
    RECT 321.67 0.0 322.985 0.42 ;
    RECT 318.89 0.0 319.41 0.42 ;
    RECT 316.42 0.0 317.54 0.42 ;
    RECT 315.84 0.0 315.98 0.42 ;
    RECT 314.96 0.0 315.4 0.42 ;
    RECT 312.265 0.0 313.18 0.42 ;
    RECT 309.9 0.0 311.835 0.42 ;
    RECT 308.545 0.0 309.005 0.42 ;
    RECT 306.165 0.0 306.29 0.42 ;
    RECT 302.94 0.0 305.725 0.42 ;
    RECT 301.555 0.0 302.5 0.42 ;
    RECT 298.79 0.0 299.745 0.42 ;
    RECT 290.555 0.0 298.35 0.42 ;
    RECT 289.365 0.0 290.115 0.42 ;
    RECT 288.595 0.0 288.925 0.42 ;
    RECT 285.365 0.0 286.36 0.42 ;
    RECT 282.81 0.0 284.925 0.42 ;
    RECT 281.44 0.0 282.37 0.42 ;
    RECT 277.965 0.0 279.66 0.42 ;
    RECT 276.05 0.0 277.525 0.42 ;
    RECT 274.82 0.0 275.61 0.42 ;
    RECT 271.16 0.0 273.035 0.42 ;
    RECT 261.55 0.0 270.215 0.42 ;
    RECT 259.25 0.0 261.13 0.42 ;
    RECT 258.195 0.0 258.83 0.42 ;
    RECT 257.615 0.0 257.775 0.42 ;
    RECT 244.75 0.0 256.72 0.42 ;
    RECT 242.45 0.0 244.33 0.42 ;
    RECT 241.395 0.0 242.03 0.42 ;
    RECT 240.815 0.0 240.975 0.42 ;
    RECT 227.95 0.0 239.92 0.42 ;
    RECT 225.65 0.0 227.53 0.42 ;
    RECT 224.595 0.0 225.23 0.42 ;
    RECT 224.015 0.0 224.175 0.42 ;
    RECT 211.15 0.0 223.12 0.42 ;
    RECT 208.85 0.0 210.73 0.42 ;
    RECT 207.795 0.0 208.43 0.42 ;
    RECT 207.215 0.0 207.375 0.42 ;
    RECT 194.35 0.0 206.32 0.42 ;
    RECT 192.05 0.0 193.93 0.42 ;
    RECT 190.995 0.0 191.63 0.42 ;
    RECT 190.415 0.0 190.575 0.42 ;
    RECT 177.55 0.0 189.52 0.42 ;
    RECT 175.25 0.0 177.13 0.42 ;
    RECT 174.195 0.0 174.83 0.42 ;
    RECT 173.615 0.0 173.775 0.42 ;
    RECT 160.75 0.0 172.72 0.42 ;
    RECT 158.45 0.0 160.33 0.42 ;
    RECT 157.395 0.0 158.03 0.42 ;
    RECT 156.815 0.0 156.975 0.42 ;
    RECT 143.95 0.0 155.92 0.42 ;
    RECT 141.65 0.0 143.53 0.42 ;
    RECT 140.595 0.0 141.23 0.42 ;
    RECT 140.015 0.0 140.175 0.42 ;
    RECT 127.15 0.0 139.12 0.42 ;
    RECT 124.85 0.0 126.73 0.42 ;
    RECT 123.795 0.0 124.43 0.42 ;
    RECT 123.215 0.0 123.375 0.42 ;
    RECT 110.35 0.0 122.32 0.42 ;
    RECT 108.05 0.0 109.93 0.42 ;
    RECT 106.995 0.0 107.63 0.42 ;
    RECT 106.415 0.0 106.575 0.42 ;
    RECT 93.55 0.0 105.52 0.42 ;
    RECT 91.25 0.0 93.13 0.42 ;
    RECT 90.195 0.0 90.83 0.42 ;
    RECT 89.615 0.0 89.775 0.42 ;
    RECT 76.75 0.0 88.72 0.42 ;
    RECT 74.45 0.0 76.33 0.42 ;
    RECT 73.395 0.0 74.03 0.42 ;
    RECT 72.815 0.0 72.975 0.42 ;
    RECT 59.95 0.0 71.92 0.42 ;
    RECT 57.65 0.0 59.53 0.42 ;
    RECT 56.595 0.0 57.23 0.42 ;
    RECT 56.015 0.0 56.175 0.42 ;
    RECT 43.15 0.0 55.12 0.42 ;
    RECT 40.85 0.0 42.73 0.42 ;
    RECT 39.795 0.0 40.43 0.42 ;
    RECT 39.215 0.0 39.375 0.42 ;
    RECT 26.35 0.0 38.32 0.42 ;
    RECT 24.05 0.0 25.93 0.42 ;
    RECT 22.995 0.0 23.63 0.42 ;
    RECT 22.415 0.0 22.575 0.42 ;
    RECT 9.55 0.0 21.52 0.42 ;
    RECT 7.25 0.0 9.13 0.42 ;
    RECT 6.195 0.0 6.83 0.42 ;
    RECT 5.615 0.0 5.775 0.42 ;
    RECT 1.09 0.0 4.72 0.42 ;
    RECT 0.0 0.0 0.67 0.42 ;
    RECT 0.0 0.42 605.13 301.17 ;
    LAYER VIA1 ;
    RECT 0.0 0.0 605.13 301.17 ;
    LAYER M2 DESIGNRULEWIDTH 0.1 ;
    RECT 604.46 0.0 605.13 0.42 ;
    RECT 600.41 0.0 604.04 0.42 ;
    RECT 599.355 0.0 599.515 0.42 ;
    RECT 598.3 0.0 598.935 0.42 ;
    RECT 596.0 0.0 597.88 0.42 ;
    RECT 583.61 0.0 595.58 0.42 ;
    RECT 582.555 0.0 582.715 0.42 ;
    RECT 581.5 0.0 582.135 0.42 ;
    RECT 579.2 0.0 581.08 0.42 ;
    RECT 566.81 0.0 578.78 0.42 ;
    RECT 565.755 0.0 565.915 0.42 ;
    RECT 564.7 0.0 565.335 0.42 ;
    RECT 562.4 0.0 564.28 0.42 ;
    RECT 550.01 0.0 561.98 0.42 ;
    RECT 548.955 0.0 549.115 0.42 ;
    RECT 547.9 0.0 548.535 0.42 ;
    RECT 545.6 0.0 547.48 0.42 ;
    RECT 533.21 0.0 545.18 0.42 ;
    RECT 532.155 0.0 532.315 0.42 ;
    RECT 531.1 0.0 531.735 0.42 ;
    RECT 528.8 0.0 530.68 0.42 ;
    RECT 516.41 0.0 528.38 0.42 ;
    RECT 515.355 0.0 515.515 0.42 ;
    RECT 514.3 0.0 514.935 0.42 ;
    RECT 512.0 0.0 513.88 0.42 ;
    RECT 499.61 0.0 511.58 0.42 ;
    RECT 498.555 0.0 498.715 0.42 ;
    RECT 497.5 0.0 498.135 0.42 ;
    RECT 495.2 0.0 497.08 0.42 ;
    RECT 482.81 0.0 494.78 0.42 ;
    RECT 481.755 0.0 481.915 0.42 ;
    RECT 480.7 0.0 481.335 0.42 ;
    RECT 478.4 0.0 480.28 0.42 ;
    RECT 466.01 0.0 477.98 0.42 ;
    RECT 464.955 0.0 465.115 0.42 ;
    RECT 463.9 0.0 464.535 0.42 ;
    RECT 461.6 0.0 463.48 0.42 ;
    RECT 449.21 0.0 461.18 0.42 ;
    RECT 448.155 0.0 448.315 0.42 ;
    RECT 447.1 0.0 447.735 0.42 ;
    RECT 444.8 0.0 446.68 0.42 ;
    RECT 432.41 0.0 444.38 0.42 ;
    RECT 431.355 0.0 431.515 0.42 ;
    RECT 430.3 0.0 430.935 0.42 ;
    RECT 428.0 0.0 429.88 0.42 ;
    RECT 415.61 0.0 427.58 0.42 ;
    RECT 414.555 0.0 414.715 0.42 ;
    RECT 413.5 0.0 414.135 0.42 ;
    RECT 411.2 0.0 413.08 0.42 ;
    RECT 398.81 0.0 410.78 0.42 ;
    RECT 397.755 0.0 397.915 0.42 ;
    RECT 396.7 0.0 397.335 0.42 ;
    RECT 394.4 0.0 396.28 0.42 ;
    RECT 382.01 0.0 393.98 0.42 ;
    RECT 380.955 0.0 381.115 0.42 ;
    RECT 379.9 0.0 380.535 0.42 ;
    RECT 377.6 0.0 379.48 0.42 ;
    RECT 365.21 0.0 377.18 0.42 ;
    RECT 364.155 0.0 364.315 0.42 ;
    RECT 363.1 0.0 363.735 0.42 ;
    RECT 360.8 0.0 362.68 0.42 ;
    RECT 348.41 0.0 360.38 0.42 ;
    RECT 347.355 0.0 347.515 0.42 ;
    RECT 346.3 0.0 346.935 0.42 ;
    RECT 344.0 0.0 345.88 0.42 ;
    RECT 328.095 0.0 343.58 0.42 ;
    RECT 326.285 0.0 326.77 0.42 ;
    RECT 323.425 0.0 325.37 0.42 ;
    RECT 321.67 0.0 322.985 0.42 ;
    RECT 318.89 0.0 319.41 0.42 ;
    RECT 316.42 0.0 317.54 0.42 ;
    RECT 315.84 0.0 315.98 0.42 ;
    RECT 314.96 0.0 315.4 0.42 ;
    RECT 312.265 0.0 313.18 0.42 ;
    RECT 309.9 0.0 311.835 0.42 ;
    RECT 308.545 0.0 309.005 0.42 ;
    RECT 306.165 0.0 306.29 0.42 ;
    RECT 302.94 0.0 305.725 0.42 ;
    RECT 301.555 0.0 302.5 0.42 ;
    RECT 298.79 0.0 299.745 0.42 ;
    RECT 290.555 0.0 298.35 0.42 ;
    RECT 289.365 0.0 290.115 0.42 ;
    RECT 288.595 0.0 288.925 0.42 ;
    RECT 285.365 0.0 286.36 0.42 ;
    RECT 282.81 0.0 284.925 0.42 ;
    RECT 281.44 0.0 282.37 0.42 ;
    RECT 277.965 0.0 279.66 0.42 ;
    RECT 276.05 0.0 277.525 0.42 ;
    RECT 274.82 0.0 275.61 0.42 ;
    RECT 271.16 0.0 273.035 0.42 ;
    RECT 261.55 0.0 270.215 0.42 ;
    RECT 259.25 0.0 261.13 0.42 ;
    RECT 258.195 0.0 258.83 0.42 ;
    RECT 257.615 0.0 257.775 0.42 ;
    RECT 244.75 0.0 256.72 0.42 ;
    RECT 242.45 0.0 244.33 0.42 ;
    RECT 241.395 0.0 242.03 0.42 ;
    RECT 240.815 0.0 240.975 0.42 ;
    RECT 227.95 0.0 239.92 0.42 ;
    RECT 225.65 0.0 227.53 0.42 ;
    RECT 224.595 0.0 225.23 0.42 ;
    RECT 224.015 0.0 224.175 0.42 ;
    RECT 211.15 0.0 223.12 0.42 ;
    RECT 208.85 0.0 210.73 0.42 ;
    RECT 207.795 0.0 208.43 0.42 ;
    RECT 207.215 0.0 207.375 0.42 ;
    RECT 194.35 0.0 206.32 0.42 ;
    RECT 192.05 0.0 193.93 0.42 ;
    RECT 190.995 0.0 191.63 0.42 ;
    RECT 190.415 0.0 190.575 0.42 ;
    RECT 177.55 0.0 189.52 0.42 ;
    RECT 175.25 0.0 177.13 0.42 ;
    RECT 174.195 0.0 174.83 0.42 ;
    RECT 173.615 0.0 173.775 0.42 ;
    RECT 160.75 0.0 172.72 0.42 ;
    RECT 158.45 0.0 160.33 0.42 ;
    RECT 157.395 0.0 158.03 0.42 ;
    RECT 156.815 0.0 156.975 0.42 ;
    RECT 143.95 0.0 155.92 0.42 ;
    RECT 141.65 0.0 143.53 0.42 ;
    RECT 140.595 0.0 141.23 0.42 ;
    RECT 140.015 0.0 140.175 0.42 ;
    RECT 127.15 0.0 139.12 0.42 ;
    RECT 124.85 0.0 126.73 0.42 ;
    RECT 123.795 0.0 124.43 0.42 ;
    RECT 123.215 0.0 123.375 0.42 ;
    RECT 110.35 0.0 122.32 0.42 ;
    RECT 108.05 0.0 109.93 0.42 ;
    RECT 106.995 0.0 107.63 0.42 ;
    RECT 106.415 0.0 106.575 0.42 ;
    RECT 93.55 0.0 105.52 0.42 ;
    RECT 91.25 0.0 93.13 0.42 ;
    RECT 90.195 0.0 90.83 0.42 ;
    RECT 89.615 0.0 89.775 0.42 ;
    RECT 76.75 0.0 88.72 0.42 ;
    RECT 74.45 0.0 76.33 0.42 ;
    RECT 73.395 0.0 74.03 0.42 ;
    RECT 72.815 0.0 72.975 0.42 ;
    RECT 59.95 0.0 71.92 0.42 ;
    RECT 57.65 0.0 59.53 0.42 ;
    RECT 56.595 0.0 57.23 0.42 ;
    RECT 56.015 0.0 56.175 0.42 ;
    RECT 43.15 0.0 55.12 0.42 ;
    RECT 40.85 0.0 42.73 0.42 ;
    RECT 39.795 0.0 40.43 0.42 ;
    RECT 39.215 0.0 39.375 0.42 ;
    RECT 26.35 0.0 38.32 0.42 ;
    RECT 24.05 0.0 25.93 0.42 ;
    RECT 22.995 0.0 23.63 0.42 ;
    RECT 22.415 0.0 22.575 0.42 ;
    RECT 9.55 0.0 21.52 0.42 ;
    RECT 7.25 0.0 9.13 0.42 ;
    RECT 6.195 0.0 6.83 0.42 ;
    RECT 5.615 0.0 5.775 0.42 ;
    RECT 1.09 0.0 4.72 0.42 ;
    RECT 0.0 0.0 0.67 0.42 ;
    RECT 0.0 0.42 605.13 301.17 ;
    LAYER VIA2 ;
    RECT 0.0 0.0 605.13 301.17 ;
    LAYER M3 DESIGNRULEWIDTH 0.1 ;
    RECT 604.46 0.0 605.13 0.42 ;
    RECT 601.465 0.0 604.04 0.42 ;
    RECT 600.41 0.0 601.045 0.42 ;
    RECT 599.355 0.0 599.515 0.42 ;
    RECT 598.3 0.0 598.935 0.42 ;
    RECT 596.0 0.0 597.88 0.42 ;
    RECT 584.665 0.0 595.58 0.42 ;
    RECT 583.61 0.0 584.245 0.42 ;
    RECT 582.555 0.0 582.715 0.42 ;
    RECT 581.5 0.0 582.135 0.42 ;
    RECT 579.2 0.0 581.08 0.42 ;
    RECT 567.865 0.0 578.78 0.42 ;
    RECT 566.81 0.0 567.445 0.42 ;
    RECT 565.755 0.0 565.915 0.42 ;
    RECT 564.7 0.0 565.335 0.42 ;
    RECT 562.4 0.0 564.28 0.42 ;
    RECT 551.065 0.0 561.98 0.42 ;
    RECT 550.01 0.0 550.645 0.42 ;
    RECT 548.955 0.0 549.115 0.42 ;
    RECT 547.9 0.0 548.535 0.42 ;
    RECT 545.6 0.0 547.48 0.42 ;
    RECT 534.265 0.0 545.18 0.42 ;
    RECT 533.21 0.0 533.845 0.42 ;
    RECT 532.155 0.0 532.315 0.42 ;
    RECT 531.1 0.0 531.735 0.42 ;
    RECT 528.8 0.0 530.68 0.42 ;
    RECT 517.465 0.0 528.38 0.42 ;
    RECT 516.41 0.0 517.045 0.42 ;
    RECT 515.355 0.0 515.515 0.42 ;
    RECT 514.3 0.0 514.935 0.42 ;
    RECT 512.0 0.0 513.88 0.42 ;
    RECT 500.665 0.0 511.58 0.42 ;
    RECT 499.61 0.0 500.245 0.42 ;
    RECT 498.555 0.0 498.715 0.42 ;
    RECT 497.5 0.0 498.135 0.42 ;
    RECT 495.2 0.0 497.08 0.42 ;
    RECT 483.865 0.0 494.78 0.42 ;
    RECT 482.81 0.0 483.445 0.42 ;
    RECT 481.755 0.0 481.915 0.42 ;
    RECT 480.7 0.0 481.335 0.42 ;
    RECT 478.4 0.0 480.28 0.42 ;
    RECT 467.065 0.0 477.98 0.42 ;
    RECT 466.01 0.0 466.645 0.42 ;
    RECT 464.955 0.0 465.115 0.42 ;
    RECT 463.9 0.0 464.535 0.42 ;
    RECT 461.6 0.0 463.48 0.42 ;
    RECT 450.265 0.0 461.18 0.42 ;
    RECT 449.21 0.0 449.845 0.42 ;
    RECT 448.155 0.0 448.315 0.42 ;
    RECT 447.1 0.0 447.735 0.42 ;
    RECT 444.8 0.0 446.68 0.42 ;
    RECT 433.465 0.0 444.38 0.42 ;
    RECT 432.41 0.0 433.045 0.42 ;
    RECT 431.355 0.0 431.515 0.42 ;
    RECT 430.3 0.0 430.935 0.42 ;
    RECT 428.0 0.0 429.88 0.42 ;
    RECT 416.665 0.0 427.58 0.42 ;
    RECT 415.61 0.0 416.245 0.42 ;
    RECT 414.555 0.0 414.715 0.42 ;
    RECT 413.5 0.0 414.135 0.42 ;
    RECT 411.2 0.0 413.08 0.42 ;
    RECT 399.865 0.0 410.78 0.42 ;
    RECT 398.81 0.0 399.445 0.42 ;
    RECT 397.755 0.0 397.915 0.42 ;
    RECT 396.7 0.0 397.335 0.42 ;
    RECT 394.4 0.0 396.28 0.42 ;
    RECT 383.065 0.0 393.98 0.42 ;
    RECT 382.01 0.0 382.645 0.42 ;
    RECT 380.955 0.0 381.115 0.42 ;
    RECT 379.9 0.0 380.535 0.42 ;
    RECT 377.6 0.0 379.48 0.42 ;
    RECT 366.265 0.0 377.18 0.42 ;
    RECT 365.21 0.0 365.845 0.42 ;
    RECT 364.155 0.0 364.315 0.42 ;
    RECT 363.1 0.0 363.735 0.42 ;
    RECT 360.8 0.0 362.68 0.42 ;
    RECT 349.465 0.0 360.38 0.42 ;
    RECT 348.41 0.0 349.045 0.42 ;
    RECT 347.355 0.0 347.515 0.42 ;
    RECT 346.3 0.0 346.935 0.42 ;
    RECT 344.0 0.0 345.88 0.42 ;
    RECT 328.095 0.0 343.58 0.42 ;
    RECT 326.285 0.0 326.77 0.42 ;
    RECT 323.425 0.0 325.37 0.42 ;
    RECT 321.67 0.0 322.985 0.42 ;
    RECT 318.89 0.0 319.41 0.42 ;
    RECT 316.42 0.0 317.54 0.42 ;
    RECT 314.96 0.0 315.98 0.42 ;
    RECT 312.265 0.0 313.18 0.42 ;
    RECT 309.9 0.0 311.835 0.42 ;
    RECT 308.545 0.0 309.46 0.42 ;
    RECT 306.165 0.0 306.29 0.42 ;
    RECT 302.94 0.0 305.725 0.42 ;
    RECT 301.555 0.0 302.5 0.42 ;
    RECT 298.79 0.0 299.745 0.42 ;
    RECT 290.555 0.0 298.35 0.42 ;
    RECT 289.365 0.0 290.115 0.42 ;
    RECT 288.595 0.0 288.925 0.42 ;
    RECT 287.25 0.0 288.155 0.42 ;
    RECT 285.365 0.0 285.915 0.42 ;
    RECT 282.81 0.0 284.925 0.42 ;
    RECT 281.44 0.0 282.37 0.42 ;
    RECT 277.965 0.0 279.66 0.42 ;
    RECT 276.05 0.0 277.525 0.42 ;
    RECT 274.82 0.0 275.61 0.42 ;
    RECT 271.16 0.0 273.035 0.42 ;
    RECT 261.55 0.0 270.215 0.42 ;
    RECT 259.25 0.0 261.13 0.42 ;
    RECT 258.195 0.0 258.83 0.42 ;
    RECT 257.615 0.0 257.775 0.42 ;
    RECT 256.085 0.0 256.72 0.42 ;
    RECT 244.75 0.0 255.665 0.42 ;
    RECT 242.45 0.0 244.33 0.42 ;
    RECT 241.395 0.0 242.03 0.42 ;
    RECT 240.815 0.0 240.975 0.42 ;
    RECT 239.285 0.0 239.92 0.42 ;
    RECT 227.95 0.0 238.865 0.42 ;
    RECT 225.65 0.0 227.53 0.42 ;
    RECT 224.595 0.0 225.23 0.42 ;
    RECT 224.015 0.0 224.175 0.42 ;
    RECT 222.485 0.0 223.12 0.42 ;
    RECT 211.15 0.0 222.065 0.42 ;
    RECT 208.85 0.0 210.73 0.42 ;
    RECT 207.795 0.0 208.43 0.42 ;
    RECT 207.215 0.0 207.375 0.42 ;
    RECT 205.685 0.0 206.32 0.42 ;
    RECT 194.35 0.0 205.265 0.42 ;
    RECT 192.05 0.0 193.93 0.42 ;
    RECT 190.995 0.0 191.63 0.42 ;
    RECT 190.415 0.0 190.575 0.42 ;
    RECT 188.885 0.0 189.52 0.42 ;
    RECT 177.55 0.0 188.465 0.42 ;
    RECT 175.25 0.0 177.13 0.42 ;
    RECT 174.195 0.0 174.83 0.42 ;
    RECT 173.615 0.0 173.775 0.42 ;
    RECT 172.085 0.0 172.72 0.42 ;
    RECT 160.75 0.0 171.665 0.42 ;
    RECT 158.45 0.0 160.33 0.42 ;
    RECT 157.395 0.0 158.03 0.42 ;
    RECT 156.815 0.0 156.975 0.42 ;
    RECT 155.285 0.0 155.92 0.42 ;
    RECT 143.95 0.0 154.865 0.42 ;
    RECT 141.65 0.0 143.53 0.42 ;
    RECT 140.595 0.0 141.23 0.42 ;
    RECT 140.015 0.0 140.175 0.42 ;
    RECT 138.485 0.0 139.12 0.42 ;
    RECT 127.15 0.0 138.065 0.42 ;
    RECT 124.85 0.0 126.73 0.42 ;
    RECT 123.795 0.0 124.43 0.42 ;
    RECT 123.215 0.0 123.375 0.42 ;
    RECT 121.685 0.0 122.32 0.42 ;
    RECT 110.35 0.0 121.265 0.42 ;
    RECT 108.05 0.0 109.93 0.42 ;
    RECT 106.995 0.0 107.63 0.42 ;
    RECT 106.415 0.0 106.575 0.42 ;
    RECT 104.885 0.0 105.52 0.42 ;
    RECT 93.55 0.0 104.465 0.42 ;
    RECT 91.25 0.0 93.13 0.42 ;
    RECT 90.195 0.0 90.83 0.42 ;
    RECT 89.615 0.0 89.775 0.42 ;
    RECT 88.085 0.0 88.72 0.42 ;
    RECT 76.75 0.0 87.665 0.42 ;
    RECT 74.45 0.0 76.33 0.42 ;
    RECT 73.395 0.0 74.03 0.42 ;
    RECT 72.815 0.0 72.975 0.42 ;
    RECT 71.285 0.0 71.92 0.42 ;
    RECT 59.95 0.0 70.865 0.42 ;
    RECT 57.65 0.0 59.53 0.42 ;
    RECT 56.595 0.0 57.23 0.42 ;
    RECT 56.015 0.0 56.175 0.42 ;
    RECT 54.485 0.0 55.12 0.42 ;
    RECT 43.15 0.0 54.065 0.42 ;
    RECT 40.85 0.0 42.73 0.42 ;
    RECT 39.795 0.0 40.43 0.42 ;
    RECT 39.215 0.0 39.375 0.42 ;
    RECT 37.685 0.0 38.32 0.42 ;
    RECT 26.35 0.0 37.265 0.42 ;
    RECT 24.05 0.0 25.93 0.42 ;
    RECT 22.995 0.0 23.63 0.42 ;
    RECT 22.415 0.0 22.575 0.42 ;
    RECT 20.885 0.0 21.52 0.42 ;
    RECT 9.55 0.0 20.465 0.42 ;
    RECT 7.25 0.0 9.13 0.42 ;
    RECT 6.195 0.0 6.83 0.42 ;
    RECT 5.615 0.0 5.775 0.42 ;
    RECT 4.085 0.0 4.72 0.42 ;
    RECT 1.09 0.0 3.665 0.42 ;
    RECT 0.0 0.0 0.67 0.42 ;
    RECT 0.0 0.42 605.13 301.17 ;
    LAYER VIA3 ;
    RECT 0.0 0.0 605.13 301.17 ;
    LAYER M4 DESIGNRULEWIDTH 0.1 ;
    RECT 603.575 0.0 603.88 0.42 ;
    RECT 602.8 0.0 602.995 0.42 ;
    RECT 602.05 0.0 602.22 0.42 ;
    RECT 599.355 0.0 599.98 0.42 ;
    RECT 597.08 0.0 597.255 0.42 ;
    RECT 596.33 0.0 596.5 0.42 ;
    RECT 595.175 0.0 595.75 0.42 ;
    RECT 594.4 0.0 594.595 0.42 ;
    RECT 593.65 0.0 593.82 0.42 ;
    RECT 592.595 0.0 593.07 0.42 ;
    RECT 590.485 0.0 592.015 0.42 ;
    RECT 589.435 0.0 589.905 0.42 ;
    RECT 588.68 0.0 588.855 0.42 ;
    RECT 587.93 0.0 588.1 0.42 ;
    RECT 586.775 0.0 587.35 0.42 ;
    RECT 586.0 0.0 586.195 0.42 ;
    RECT 585.25 0.0 585.42 0.42 ;
    RECT 582.555 0.0 583.18 0.42 ;
    RECT 580.28 0.0 580.455 0.42 ;
    RECT 579.53 0.0 579.7 0.42 ;
    RECT 578.375 0.0 578.95 0.42 ;
    RECT 577.6 0.0 577.795 0.42 ;
    RECT 576.85 0.0 577.02 0.42 ;
    RECT 575.795 0.0 576.27 0.42 ;
    RECT 573.685 0.0 575.215 0.42 ;
    RECT 572.635 0.0 573.105 0.42 ;
    RECT 571.88 0.0 572.055 0.42 ;
    RECT 571.13 0.0 571.3 0.42 ;
    RECT 569.975 0.0 570.55 0.42 ;
    RECT 569.2 0.0 569.395 0.42 ;
    RECT 568.45 0.0 568.62 0.42 ;
    RECT 565.755 0.0 566.38 0.42 ;
    RECT 563.48 0.0 563.655 0.42 ;
    RECT 562.73 0.0 562.9 0.42 ;
    RECT 561.575 0.0 562.15 0.42 ;
    RECT 560.8 0.0 560.995 0.42 ;
    RECT 560.05 0.0 560.22 0.42 ;
    RECT 558.995 0.0 559.47 0.42 ;
    RECT 556.885 0.0 558.415 0.42 ;
    RECT 555.835 0.0 556.305 0.42 ;
    RECT 555.08 0.0 555.255 0.42 ;
    RECT 554.33 0.0 554.5 0.42 ;
    RECT 553.175 0.0 553.75 0.42 ;
    RECT 552.4 0.0 552.595 0.42 ;
    RECT 551.65 0.0 551.82 0.42 ;
    RECT 548.955 0.0 549.58 0.42 ;
    RECT 546.68 0.0 546.855 0.42 ;
    RECT 545.93 0.0 546.1 0.42 ;
    RECT 544.775 0.0 545.35 0.42 ;
    RECT 544.0 0.0 544.195 0.42 ;
    RECT 543.25 0.0 543.42 0.42 ;
    RECT 542.195 0.0 542.67 0.42 ;
    RECT 540.085 0.0 541.615 0.42 ;
    RECT 539.035 0.0 539.505 0.42 ;
    RECT 538.28 0.0 538.455 0.42 ;
    RECT 537.53 0.0 537.7 0.42 ;
    RECT 536.375 0.0 536.95 0.42 ;
    RECT 535.6 0.0 535.795 0.42 ;
    RECT 534.85 0.0 535.02 0.42 ;
    RECT 532.155 0.0 532.78 0.42 ;
    RECT 529.88 0.0 530.055 0.42 ;
    RECT 529.13 0.0 529.3 0.42 ;
    RECT 527.975 0.0 528.55 0.42 ;
    RECT 527.2 0.0 527.395 0.42 ;
    RECT 526.45 0.0 526.62 0.42 ;
    RECT 525.395 0.0 525.87 0.42 ;
    RECT 523.285 0.0 524.815 0.42 ;
    RECT 522.235 0.0 522.705 0.42 ;
    RECT 521.48 0.0 521.655 0.42 ;
    RECT 520.73 0.0 520.9 0.42 ;
    RECT 519.575 0.0 520.15 0.42 ;
    RECT 518.8 0.0 518.995 0.42 ;
    RECT 518.05 0.0 518.22 0.42 ;
    RECT 515.355 0.0 515.98 0.42 ;
    RECT 513.08 0.0 513.255 0.42 ;
    RECT 512.33 0.0 512.5 0.42 ;
    RECT 511.175 0.0 511.75 0.42 ;
    RECT 510.4 0.0 510.595 0.42 ;
    RECT 509.65 0.0 509.82 0.42 ;
    RECT 508.595 0.0 509.07 0.42 ;
    RECT 506.485 0.0 508.015 0.42 ;
    RECT 505.435 0.0 505.905 0.42 ;
    RECT 504.68 0.0 504.855 0.42 ;
    RECT 503.93 0.0 504.1 0.42 ;
    RECT 502.775 0.0 503.35 0.42 ;
    RECT 502.0 0.0 502.195 0.42 ;
    RECT 501.25 0.0 501.42 0.42 ;
    RECT 498.555 0.0 499.18 0.42 ;
    RECT 496.28 0.0 496.455 0.42 ;
    RECT 495.53 0.0 495.7 0.42 ;
    RECT 494.375 0.0 494.95 0.42 ;
    RECT 493.6 0.0 493.795 0.42 ;
    RECT 492.85 0.0 493.02 0.42 ;
    RECT 491.795 0.0 492.27 0.42 ;
    RECT 489.685 0.0 491.215 0.42 ;
    RECT 488.635 0.0 489.105 0.42 ;
    RECT 487.88 0.0 488.055 0.42 ;
    RECT 487.13 0.0 487.3 0.42 ;
    RECT 485.975 0.0 486.55 0.42 ;
    RECT 485.2 0.0 485.395 0.42 ;
    RECT 484.45 0.0 484.62 0.42 ;
    RECT 481.755 0.0 482.38 0.42 ;
    RECT 479.48 0.0 479.655 0.42 ;
    RECT 478.73 0.0 478.9 0.42 ;
    RECT 477.575 0.0 478.15 0.42 ;
    RECT 476.8 0.0 476.995 0.42 ;
    RECT 476.05 0.0 476.22 0.42 ;
    RECT 474.995 0.0 475.47 0.42 ;
    RECT 472.885 0.0 474.415 0.42 ;
    RECT 471.835 0.0 472.305 0.42 ;
    RECT 471.08 0.0 471.255 0.42 ;
    RECT 470.33 0.0 470.5 0.42 ;
    RECT 469.175 0.0 469.75 0.42 ;
    RECT 468.4 0.0 468.595 0.42 ;
    RECT 467.65 0.0 467.82 0.42 ;
    RECT 464.955 0.0 465.58 0.42 ;
    RECT 462.68 0.0 462.855 0.42 ;
    RECT 461.93 0.0 462.1 0.42 ;
    RECT 460.775 0.0 461.35 0.42 ;
    RECT 460.0 0.0 460.195 0.42 ;
    RECT 459.25 0.0 459.42 0.42 ;
    RECT 458.195 0.0 458.67 0.42 ;
    RECT 456.085 0.0 457.615 0.42 ;
    RECT 455.035 0.0 455.505 0.42 ;
    RECT 454.28 0.0 454.455 0.42 ;
    RECT 453.53 0.0 453.7 0.42 ;
    RECT 452.375 0.0 452.95 0.42 ;
    RECT 451.6 0.0 451.795 0.42 ;
    RECT 450.85 0.0 451.02 0.42 ;
    RECT 448.155 0.0 448.78 0.42 ;
    RECT 445.88 0.0 446.055 0.42 ;
    RECT 445.13 0.0 445.3 0.42 ;
    RECT 443.975 0.0 444.55 0.42 ;
    RECT 443.2 0.0 443.395 0.42 ;
    RECT 442.45 0.0 442.62 0.42 ;
    RECT 441.395 0.0 441.87 0.42 ;
    RECT 439.285 0.0 440.815 0.42 ;
    RECT 438.235 0.0 438.705 0.42 ;
    RECT 437.48 0.0 437.655 0.42 ;
    RECT 436.73 0.0 436.9 0.42 ;
    RECT 435.575 0.0 436.15 0.42 ;
    RECT 434.8 0.0 434.995 0.42 ;
    RECT 434.05 0.0 434.22 0.42 ;
    RECT 431.355 0.0 431.98 0.42 ;
    RECT 429.08 0.0 429.255 0.42 ;
    RECT 428.33 0.0 428.5 0.42 ;
    RECT 427.175 0.0 427.75 0.42 ;
    RECT 426.4 0.0 426.595 0.42 ;
    RECT 425.65 0.0 425.82 0.42 ;
    RECT 424.595 0.0 425.07 0.42 ;
    RECT 422.485 0.0 424.015 0.42 ;
    RECT 421.435 0.0 421.905 0.42 ;
    RECT 420.68 0.0 420.855 0.42 ;
    RECT 419.93 0.0 420.1 0.42 ;
    RECT 418.775 0.0 419.35 0.42 ;
    RECT 418.0 0.0 418.195 0.42 ;
    RECT 417.25 0.0 417.42 0.42 ;
    RECT 414.555 0.0 415.18 0.42 ;
    RECT 412.28 0.0 412.455 0.42 ;
    RECT 411.53 0.0 411.7 0.42 ;
    RECT 410.375 0.0 410.95 0.42 ;
    RECT 409.6 0.0 409.795 0.42 ;
    RECT 408.85 0.0 409.02 0.42 ;
    RECT 407.795 0.0 408.27 0.42 ;
    RECT 405.685 0.0 407.215 0.42 ;
    RECT 404.635 0.0 405.105 0.42 ;
    RECT 403.88 0.0 404.055 0.42 ;
    RECT 403.13 0.0 403.3 0.42 ;
    RECT 401.975 0.0 402.55 0.42 ;
    RECT 401.2 0.0 401.395 0.42 ;
    RECT 400.45 0.0 400.62 0.42 ;
    RECT 397.755 0.0 398.38 0.42 ;
    RECT 395.48 0.0 395.655 0.42 ;
    RECT 394.73 0.0 394.9 0.42 ;
    RECT 393.575 0.0 394.15 0.42 ;
    RECT 392.8 0.0 392.995 0.42 ;
    RECT 392.05 0.0 392.22 0.42 ;
    RECT 390.995 0.0 391.47 0.42 ;
    RECT 388.885 0.0 390.415 0.42 ;
    RECT 387.835 0.0 388.305 0.42 ;
    RECT 387.08 0.0 387.255 0.42 ;
    RECT 386.33 0.0 386.5 0.42 ;
    RECT 385.175 0.0 385.75 0.42 ;
    RECT 384.4 0.0 384.595 0.42 ;
    RECT 383.65 0.0 383.82 0.42 ;
    RECT 380.955 0.0 381.58 0.42 ;
    RECT 378.68 0.0 378.855 0.42 ;
    RECT 377.93 0.0 378.1 0.42 ;
    RECT 376.775 0.0 377.35 0.42 ;
    RECT 376.0 0.0 376.195 0.42 ;
    RECT 375.25 0.0 375.42 0.42 ;
    RECT 374.195 0.0 374.67 0.42 ;
    RECT 372.085 0.0 373.615 0.42 ;
    RECT 371.035 0.0 371.505 0.42 ;
    RECT 370.28 0.0 370.455 0.42 ;
    RECT 369.53 0.0 369.7 0.42 ;
    RECT 368.375 0.0 368.95 0.42 ;
    RECT 367.6 0.0 367.795 0.42 ;
    RECT 366.85 0.0 367.02 0.42 ;
    RECT 364.155 0.0 364.78 0.42 ;
    RECT 361.88 0.0 362.055 0.42 ;
    RECT 361.13 0.0 361.3 0.42 ;
    RECT 359.975 0.0 360.55 0.42 ;
    RECT 359.2 0.0 359.395 0.42 ;
    RECT 358.45 0.0 358.62 0.42 ;
    RECT 357.395 0.0 357.87 0.42 ;
    RECT 355.285 0.0 356.815 0.42 ;
    RECT 354.235 0.0 354.705 0.42 ;
    RECT 353.48 0.0 353.655 0.42 ;
    RECT 352.73 0.0 352.9 0.42 ;
    RECT 351.575 0.0 352.15 0.42 ;
    RECT 350.8 0.0 350.995 0.42 ;
    RECT 350.05 0.0 350.22 0.42 ;
    RECT 347.355 0.0 347.98 0.42 ;
    RECT 345.08 0.0 345.255 0.42 ;
    RECT 344.33 0.0 344.5 0.42 ;
    RECT 343.175 0.0 343.75 0.42 ;
    RECT 342.4 0.0 342.595 0.42 ;
    RECT 341.65 0.0 341.82 0.42 ;
    RECT 340.595 0.0 341.07 0.42 ;
    RECT 338.485 0.0 340.015 0.42 ;
    RECT 337.435 0.0 337.905 0.42 ;
    RECT 336.68 0.0 336.855 0.42 ;
    RECT 335.93 0.0 336.1 0.42 ;
    RECT 333.79 0.0 335.35 0.42 ;
    RECT 332.465 0.0 333.05 0.42 ;
    RECT 331.145 0.0 331.725 0.42 ;
    RECT 329.82 0.0 330.405 0.42 ;
    RECT 327.65 0.0 327.75 0.42 ;
    RECT 326.285 0.0 326.425 0.42 ;
    RECT 324.525 0.0 325.1 0.42 ;
    RECT 323.48 0.0 323.785 0.42 ;
    RECT 322.45 0.0 322.74 0.42 ;
    RECT 321.13 0.0 321.23 0.42 ;
    RECT 318.89 0.0 319.055 0.42 ;
    RECT 317.74 0.0 318.0 0.42 ;
    RECT 315.825 0.0 315.98 0.42 ;
    RECT 314.96 0.0 315.085 0.42 ;
    RECT 313.62 0.0 313.76 0.42 ;
    RECT 312.265 0.0 312.44 0.42 ;
    RECT 309.9 0.0 311.115 0.42 ;
    RECT 309.21 0.0 309.46 0.42 ;
    RECT 307.705 0.0 308.47 0.42 ;
    RECT 306.73 0.0 306.965 0.42 ;
    RECT 306.165 0.0 306.29 0.42 ;
    RECT 303.975 0.0 305.725 0.42 ;
    RECT 302.94 0.0 303.405 0.42 ;
    RECT 301.555 0.0 302.5 0.42 ;
    RECT 300.36 0.0 300.675 0.42 ;
    RECT 299.255 0.0 299.62 0.42 ;
    RECT 296.575 0.0 297.13 0.42 ;
    RECT 295.27 0.0 295.835 0.42 ;
    RECT 293.965 0.0 294.53 0.42 ;
    RECT 291.91 0.0 293.225 0.42 ;
    RECT 288.765 0.0 288.925 0.42 ;
    RECT 286.8 0.0 288.025 0.42 ;
    RECT 285.365 0.0 285.915 0.42 ;
    RECT 284.81 0.0 284.925 0.42 ;
    RECT 282.67 0.0 284.24 0.42 ;
    RECT 281.28 0.0 281.93 0.42 ;
    RECT 280.545 0.0 280.71 0.42 ;
    RECT 278.695 0.0 279.28 0.42 ;
    RECT 277.375 0.0 277.525 0.42 ;
    RECT 274.73 0.0 275.31 0.42 ;
    RECT 272.085 0.0 272.665 0.42 ;
    RECT 271.16 0.0 271.335 0.42 ;
    RECT 269.78 0.0 270.215 0.42 ;
    RECT 269.03 0.0 269.2 0.42 ;
    RECT 268.275 0.0 268.45 0.42 ;
    RECT 267.225 0.0 267.695 0.42 ;
    RECT 265.115 0.0 266.645 0.42 ;
    RECT 264.06 0.0 264.535 0.42 ;
    RECT 263.31 0.0 263.48 0.42 ;
    RECT 262.535 0.0 262.73 0.42 ;
    RECT 261.38 0.0 261.955 0.42 ;
    RECT 260.63 0.0 260.8 0.42 ;
    RECT 259.875 0.0 260.05 0.42 ;
    RECT 257.15 0.0 257.775 0.42 ;
    RECT 254.91 0.0 255.08 0.42 ;
    RECT 254.135 0.0 254.33 0.42 ;
    RECT 252.98 0.0 253.555 0.42 ;
    RECT 252.23 0.0 252.4 0.42 ;
    RECT 251.475 0.0 251.65 0.42 ;
    RECT 250.425 0.0 250.895 0.42 ;
    RECT 248.315 0.0 249.845 0.42 ;
    RECT 247.26 0.0 247.735 0.42 ;
    RECT 246.51 0.0 246.68 0.42 ;
    RECT 245.735 0.0 245.93 0.42 ;
    RECT 244.58 0.0 245.155 0.42 ;
    RECT 243.83 0.0 244.0 0.42 ;
    RECT 243.075 0.0 243.25 0.42 ;
    RECT 240.35 0.0 240.975 0.42 ;
    RECT 238.11 0.0 238.28 0.42 ;
    RECT 237.335 0.0 237.53 0.42 ;
    RECT 236.18 0.0 236.755 0.42 ;
    RECT 235.43 0.0 235.6 0.42 ;
    RECT 234.675 0.0 234.85 0.42 ;
    RECT 233.625 0.0 234.095 0.42 ;
    RECT 231.515 0.0 233.045 0.42 ;
    RECT 230.46 0.0 230.935 0.42 ;
    RECT 229.71 0.0 229.88 0.42 ;
    RECT 228.935 0.0 229.13 0.42 ;
    RECT 227.78 0.0 228.355 0.42 ;
    RECT 227.03 0.0 227.2 0.42 ;
    RECT 226.275 0.0 226.45 0.42 ;
    RECT 223.55 0.0 224.175 0.42 ;
    RECT 221.31 0.0 221.48 0.42 ;
    RECT 220.535 0.0 220.73 0.42 ;
    RECT 219.38 0.0 219.955 0.42 ;
    RECT 218.63 0.0 218.8 0.42 ;
    RECT 217.875 0.0 218.05 0.42 ;
    RECT 216.825 0.0 217.295 0.42 ;
    RECT 214.715 0.0 216.245 0.42 ;
    RECT 213.66 0.0 214.135 0.42 ;
    RECT 212.91 0.0 213.08 0.42 ;
    RECT 212.135 0.0 212.33 0.42 ;
    RECT 210.98 0.0 211.555 0.42 ;
    RECT 210.23 0.0 210.4 0.42 ;
    RECT 209.475 0.0 209.65 0.42 ;
    RECT 206.75 0.0 207.375 0.42 ;
    RECT 204.51 0.0 204.68 0.42 ;
    RECT 203.735 0.0 203.93 0.42 ;
    RECT 202.58 0.0 203.155 0.42 ;
    RECT 201.83 0.0 202.0 0.42 ;
    RECT 201.075 0.0 201.25 0.42 ;
    RECT 200.025 0.0 200.495 0.42 ;
    RECT 197.915 0.0 199.445 0.42 ;
    RECT 196.86 0.0 197.335 0.42 ;
    RECT 196.11 0.0 196.28 0.42 ;
    RECT 195.335 0.0 195.53 0.42 ;
    RECT 194.18 0.0 194.755 0.42 ;
    RECT 193.43 0.0 193.6 0.42 ;
    RECT 192.675 0.0 192.85 0.42 ;
    RECT 189.95 0.0 190.575 0.42 ;
    RECT 187.71 0.0 187.88 0.42 ;
    RECT 186.935 0.0 187.13 0.42 ;
    RECT 185.78 0.0 186.355 0.42 ;
    RECT 185.03 0.0 185.2 0.42 ;
    RECT 184.275 0.0 184.45 0.42 ;
    RECT 183.225 0.0 183.695 0.42 ;
    RECT 181.115 0.0 182.645 0.42 ;
    RECT 180.06 0.0 180.535 0.42 ;
    RECT 179.31 0.0 179.48 0.42 ;
    RECT 178.535 0.0 178.73 0.42 ;
    RECT 177.38 0.0 177.955 0.42 ;
    RECT 176.63 0.0 176.8 0.42 ;
    RECT 175.875 0.0 176.05 0.42 ;
    RECT 173.15 0.0 173.775 0.42 ;
    RECT 170.91 0.0 171.08 0.42 ;
    RECT 170.135 0.0 170.33 0.42 ;
    RECT 168.98 0.0 169.555 0.42 ;
    RECT 168.23 0.0 168.4 0.42 ;
    RECT 167.475 0.0 167.65 0.42 ;
    RECT 166.425 0.0 166.895 0.42 ;
    RECT 164.315 0.0 165.845 0.42 ;
    RECT 163.26 0.0 163.735 0.42 ;
    RECT 162.51 0.0 162.68 0.42 ;
    RECT 161.735 0.0 161.93 0.42 ;
    RECT 160.58 0.0 161.155 0.42 ;
    RECT 159.83 0.0 160.0 0.42 ;
    RECT 159.075 0.0 159.25 0.42 ;
    RECT 156.35 0.0 156.975 0.42 ;
    RECT 154.11 0.0 154.28 0.42 ;
    RECT 153.335 0.0 153.53 0.42 ;
    RECT 152.18 0.0 152.755 0.42 ;
    RECT 151.43 0.0 151.6 0.42 ;
    RECT 150.675 0.0 150.85 0.42 ;
    RECT 149.625 0.0 150.095 0.42 ;
    RECT 147.515 0.0 149.045 0.42 ;
    RECT 146.46 0.0 146.935 0.42 ;
    RECT 145.71 0.0 145.88 0.42 ;
    RECT 144.935 0.0 145.13 0.42 ;
    RECT 143.78 0.0 144.355 0.42 ;
    RECT 143.03 0.0 143.2 0.42 ;
    RECT 142.275 0.0 142.45 0.42 ;
    RECT 139.55 0.0 140.175 0.42 ;
    RECT 137.31 0.0 137.48 0.42 ;
    RECT 136.535 0.0 136.73 0.42 ;
    RECT 135.38 0.0 135.955 0.42 ;
    RECT 134.63 0.0 134.8 0.42 ;
    RECT 133.875 0.0 134.05 0.42 ;
    RECT 132.825 0.0 133.295 0.42 ;
    RECT 130.715 0.0 132.245 0.42 ;
    RECT 129.66 0.0 130.135 0.42 ;
    RECT 128.91 0.0 129.08 0.42 ;
    RECT 128.135 0.0 128.33 0.42 ;
    RECT 126.98 0.0 127.555 0.42 ;
    RECT 126.23 0.0 126.4 0.42 ;
    RECT 125.475 0.0 125.65 0.42 ;
    RECT 122.75 0.0 123.375 0.42 ;
    RECT 120.51 0.0 120.68 0.42 ;
    RECT 119.735 0.0 119.93 0.42 ;
    RECT 118.58 0.0 119.155 0.42 ;
    RECT 117.83 0.0 118.0 0.42 ;
    RECT 117.075 0.0 117.25 0.42 ;
    RECT 116.025 0.0 116.495 0.42 ;
    RECT 113.915 0.0 115.445 0.42 ;
    RECT 112.86 0.0 113.335 0.42 ;
    RECT 112.11 0.0 112.28 0.42 ;
    RECT 111.335 0.0 111.53 0.42 ;
    RECT 110.18 0.0 110.755 0.42 ;
    RECT 109.43 0.0 109.6 0.42 ;
    RECT 108.675 0.0 108.85 0.42 ;
    RECT 105.95 0.0 106.575 0.42 ;
    RECT 103.71 0.0 103.88 0.42 ;
    RECT 102.935 0.0 103.13 0.42 ;
    RECT 101.78 0.0 102.355 0.42 ;
    RECT 101.03 0.0 101.2 0.42 ;
    RECT 100.275 0.0 100.45 0.42 ;
    RECT 99.225 0.0 99.695 0.42 ;
    RECT 97.115 0.0 98.645 0.42 ;
    RECT 96.06 0.0 96.535 0.42 ;
    RECT 95.31 0.0 95.48 0.42 ;
    RECT 94.535 0.0 94.73 0.42 ;
    RECT 93.38 0.0 93.955 0.42 ;
    RECT 92.63 0.0 92.8 0.42 ;
    RECT 91.875 0.0 92.05 0.42 ;
    RECT 89.15 0.0 89.775 0.42 ;
    RECT 86.91 0.0 87.08 0.42 ;
    RECT 86.135 0.0 86.33 0.42 ;
    RECT 84.98 0.0 85.555 0.42 ;
    RECT 84.23 0.0 84.4 0.42 ;
    RECT 83.475 0.0 83.65 0.42 ;
    RECT 82.425 0.0 82.895 0.42 ;
    RECT 80.315 0.0 81.845 0.42 ;
    RECT 79.26 0.0 79.735 0.42 ;
    RECT 78.51 0.0 78.68 0.42 ;
    RECT 77.735 0.0 77.93 0.42 ;
    RECT 76.58 0.0 77.155 0.42 ;
    RECT 75.83 0.0 76.0 0.42 ;
    RECT 75.075 0.0 75.25 0.42 ;
    RECT 72.35 0.0 72.975 0.42 ;
    RECT 70.11 0.0 70.28 0.42 ;
    RECT 69.335 0.0 69.53 0.42 ;
    RECT 68.18 0.0 68.755 0.42 ;
    RECT 67.43 0.0 67.6 0.42 ;
    RECT 66.675 0.0 66.85 0.42 ;
    RECT 65.625 0.0 66.095 0.42 ;
    RECT 63.515 0.0 65.045 0.42 ;
    RECT 62.46 0.0 62.935 0.42 ;
    RECT 61.71 0.0 61.88 0.42 ;
    RECT 60.935 0.0 61.13 0.42 ;
    RECT 59.78 0.0 60.355 0.42 ;
    RECT 59.03 0.0 59.2 0.42 ;
    RECT 58.275 0.0 58.45 0.42 ;
    RECT 55.55 0.0 56.175 0.42 ;
    RECT 53.31 0.0 53.48 0.42 ;
    RECT 52.535 0.0 52.73 0.42 ;
    RECT 51.38 0.0 51.955 0.42 ;
    RECT 50.63 0.0 50.8 0.42 ;
    RECT 49.875 0.0 50.05 0.42 ;
    RECT 48.825 0.0 49.295 0.42 ;
    RECT 46.715 0.0 48.245 0.42 ;
    RECT 45.66 0.0 46.135 0.42 ;
    RECT 44.91 0.0 45.08 0.42 ;
    RECT 44.135 0.0 44.33 0.42 ;
    RECT 42.98 0.0 43.555 0.42 ;
    RECT 42.23 0.0 42.4 0.42 ;
    RECT 41.475 0.0 41.65 0.42 ;
    RECT 38.75 0.0 39.375 0.42 ;
    RECT 36.51 0.0 36.68 0.42 ;
    RECT 35.735 0.0 35.93 0.42 ;
    RECT 34.58 0.0 35.155 0.42 ;
    RECT 33.83 0.0 34.0 0.42 ;
    RECT 33.075 0.0 33.25 0.42 ;
    RECT 32.025 0.0 32.495 0.42 ;
    RECT 29.915 0.0 31.445 0.42 ;
    RECT 28.86 0.0 29.335 0.42 ;
    RECT 28.11 0.0 28.28 0.42 ;
    RECT 27.335 0.0 27.53 0.42 ;
    RECT 26.18 0.0 26.755 0.42 ;
    RECT 25.43 0.0 25.6 0.42 ;
    RECT 24.675 0.0 24.85 0.42 ;
    RECT 21.95 0.0 22.575 0.42 ;
    RECT 19.71 0.0 19.88 0.42 ;
    RECT 18.935 0.0 19.13 0.42 ;
    RECT 17.78 0.0 18.355 0.42 ;
    RECT 17.03 0.0 17.2 0.42 ;
    RECT 16.275 0.0 16.45 0.42 ;
    RECT 15.225 0.0 15.695 0.42 ;
    RECT 13.115 0.0 14.645 0.42 ;
    RECT 12.06 0.0 12.535 0.42 ;
    RECT 11.31 0.0 11.48 0.42 ;
    RECT 10.535 0.0 10.73 0.42 ;
    RECT 9.38 0.0 9.955 0.42 ;
    RECT 8.63 0.0 8.8 0.42 ;
    RECT 7.875 0.0 8.05 0.42 ;
    RECT 5.15 0.0 5.775 0.42 ;
    RECT 2.91 0.0 3.08 0.42 ;
    RECT 2.135 0.0 2.33 0.42 ;
    RECT 1.25 0.0 1.555 0.42 ;
    RECT 603.575 0.42 603.88 301.17 ;
    RECT 602.8 0.42 602.995 301.17 ;
    RECT 602.05 0.42 602.22 301.17 ;
    RECT 600.995 0.42 601.47 301.17 ;
    RECT 598.885 0.42 600.415 301.17 ;
    RECT 597.835 0.42 598.305 301.17 ;
    RECT 597.08 0.42 597.255 301.17 ;
    RECT 596.33 0.42 596.5 301.17 ;
    RECT 595.175 0.42 595.75 301.17 ;
    RECT 594.4 0.42 594.595 301.17 ;
    RECT 593.65 0.42 593.82 301.17 ;
    RECT 592.595 0.42 593.07 301.17 ;
    RECT 590.485 0.42 592.015 301.17 ;
    RECT 589.435 0.42 589.905 301.17 ;
    RECT 588.68 0.42 588.855 301.17 ;
    RECT 587.93 0.42 588.1 301.17 ;
    RECT 586.775 0.42 587.35 301.17 ;
    RECT 586.0 0.42 586.195 301.17 ;
    RECT 585.25 0.42 585.42 301.17 ;
    RECT 584.195 0.42 584.67 301.17 ;
    RECT 582.085 0.42 583.615 301.17 ;
    RECT 581.035 0.42 581.505 301.17 ;
    RECT 580.28 0.42 580.455 301.17 ;
    RECT 579.53 0.42 579.7 301.17 ;
    RECT 578.375 0.42 578.95 301.17 ;
    RECT 577.6 0.42 577.795 301.17 ;
    RECT 576.85 0.42 577.02 301.17 ;
    RECT 575.795 0.42 576.27 301.17 ;
    RECT 573.685 0.42 575.215 301.17 ;
    RECT 572.635 0.42 573.105 301.17 ;
    RECT 571.88 0.42 572.055 301.17 ;
    RECT 571.13 0.42 571.3 301.17 ;
    RECT 569.975 0.42 570.55 301.17 ;
    RECT 569.2 0.42 569.395 301.17 ;
    RECT 568.45 0.42 568.62 301.17 ;
    RECT 567.395 0.42 567.87 301.17 ;
    RECT 565.285 0.42 566.815 301.17 ;
    RECT 564.235 0.42 564.705 301.17 ;
    RECT 563.48 0.42 563.655 301.17 ;
    RECT 562.73 0.42 562.9 301.17 ;
    RECT 561.575 0.42 562.15 301.17 ;
    RECT 560.8 0.42 560.995 301.17 ;
    RECT 560.05 0.42 560.22 301.17 ;
    RECT 558.995 0.42 559.47 301.17 ;
    RECT 556.885 0.42 558.415 301.17 ;
    RECT 555.835 0.42 556.305 301.17 ;
    RECT 555.08 0.42 555.255 301.17 ;
    RECT 554.33 0.42 554.5 301.17 ;
    RECT 553.175 0.42 553.75 301.17 ;
    RECT 552.4 0.42 552.595 301.17 ;
    RECT 551.65 0.42 551.82 301.17 ;
    RECT 550.595 0.42 551.07 301.17 ;
    RECT 548.485 0.42 550.015 301.17 ;
    RECT 547.435 0.42 547.905 301.17 ;
    RECT 546.68 0.42 546.855 301.17 ;
    RECT 545.93 0.42 546.1 301.17 ;
    RECT 544.775 0.42 545.35 301.17 ;
    RECT 544.0 0.42 544.195 301.17 ;
    RECT 543.25 0.42 543.42 301.17 ;
    RECT 542.195 0.42 542.67 301.17 ;
    RECT 540.085 0.42 541.615 301.17 ;
    RECT 539.035 0.42 539.505 301.17 ;
    RECT 538.28 0.42 538.455 301.17 ;
    RECT 537.53 0.42 537.7 301.17 ;
    RECT 536.375 0.42 536.95 301.17 ;
    RECT 535.6 0.42 535.795 301.17 ;
    RECT 534.85 0.42 535.02 301.17 ;
    RECT 533.795 0.42 534.27 301.17 ;
    RECT 531.685 0.42 533.215 301.17 ;
    RECT 530.635 0.42 531.105 301.17 ;
    RECT 529.88 0.42 530.055 301.17 ;
    RECT 529.13 0.42 529.3 301.17 ;
    RECT 527.975 0.42 528.55 301.17 ;
    RECT 527.2 0.42 527.395 301.17 ;
    RECT 526.45 0.42 526.62 301.17 ;
    RECT 525.395 0.42 525.87 301.17 ;
    RECT 523.285 0.42 524.815 301.17 ;
    RECT 522.235 0.42 522.705 301.17 ;
    RECT 521.48 0.42 521.655 301.17 ;
    RECT 520.73 0.42 520.9 301.17 ;
    RECT 519.575 0.42 520.15 301.17 ;
    RECT 518.8 0.42 518.995 301.17 ;
    RECT 518.05 0.42 518.22 301.17 ;
    RECT 516.995 0.42 517.47 301.17 ;
    RECT 514.885 0.42 516.415 301.17 ;
    RECT 513.835 0.42 514.305 301.17 ;
    RECT 513.08 0.42 513.255 301.17 ;
    RECT 512.33 0.42 512.5 301.17 ;
    RECT 511.175 0.42 511.75 301.17 ;
    RECT 510.4 0.42 510.595 301.17 ;
    RECT 509.65 0.42 509.82 301.17 ;
    RECT 508.595 0.42 509.07 301.17 ;
    RECT 506.485 0.42 508.015 301.17 ;
    RECT 505.435 0.42 505.905 301.17 ;
    RECT 504.68 0.42 504.855 301.17 ;
    RECT 503.93 0.42 504.1 301.17 ;
    RECT 502.775 0.42 503.35 301.17 ;
    RECT 502.0 0.42 502.195 301.17 ;
    RECT 501.25 0.42 501.42 301.17 ;
    RECT 500.195 0.42 500.67 301.17 ;
    RECT 498.085 0.42 499.615 301.17 ;
    RECT 497.035 0.42 497.505 301.17 ;
    RECT 496.28 0.42 496.455 301.17 ;
    RECT 495.53 0.42 495.7 301.17 ;
    RECT 494.375 0.42 494.95 301.17 ;
    RECT 493.6 0.42 493.795 301.17 ;
    RECT 492.85 0.42 493.02 301.17 ;
    RECT 491.795 0.42 492.27 301.17 ;
    RECT 489.685 0.42 491.215 301.17 ;
    RECT 488.635 0.42 489.105 301.17 ;
    RECT 487.88 0.42 488.055 301.17 ;
    RECT 487.13 0.42 487.3 301.17 ;
    RECT 485.975 0.42 486.55 301.17 ;
    RECT 485.2 0.42 485.395 301.17 ;
    RECT 484.45 0.42 484.62 301.17 ;
    RECT 483.395 0.42 483.87 301.17 ;
    RECT 481.285 0.42 482.815 301.17 ;
    RECT 480.235 0.42 480.705 301.17 ;
    RECT 479.48 0.42 479.655 301.17 ;
    RECT 478.73 0.42 478.9 301.17 ;
    RECT 477.575 0.42 478.15 301.17 ;
    RECT 476.8 0.42 476.995 301.17 ;
    RECT 476.05 0.42 476.22 301.17 ;
    RECT 474.995 0.42 475.47 301.17 ;
    RECT 472.885 0.42 474.415 301.17 ;
    RECT 471.835 0.42 472.305 301.17 ;
    RECT 471.08 0.42 471.255 301.17 ;
    RECT 470.33 0.42 470.5 301.17 ;
    RECT 469.175 0.42 469.75 301.17 ;
    RECT 468.4 0.42 468.595 301.17 ;
    RECT 467.65 0.42 467.82 301.17 ;
    RECT 466.595 0.42 467.07 301.17 ;
    RECT 464.485 0.42 466.015 301.17 ;
    RECT 463.435 0.42 463.905 301.17 ;
    RECT 462.68 0.42 462.855 301.17 ;
    RECT 461.93 0.42 462.1 301.17 ;
    RECT 460.775 0.42 461.35 301.17 ;
    RECT 460.0 0.42 460.195 301.17 ;
    RECT 459.25 0.42 459.42 301.17 ;
    RECT 458.195 0.42 458.67 301.17 ;
    RECT 456.085 0.42 457.615 301.17 ;
    RECT 455.035 0.42 455.505 301.17 ;
    RECT 454.28 0.42 454.455 301.17 ;
    RECT 453.53 0.42 453.7 301.17 ;
    RECT 452.375 0.42 452.95 301.17 ;
    RECT 451.6 0.42 451.795 301.17 ;
    RECT 450.85 0.42 451.02 301.17 ;
    RECT 449.795 0.42 450.27 301.17 ;
    RECT 447.685 0.42 449.215 301.17 ;
    RECT 446.635 0.42 447.105 301.17 ;
    RECT 445.88 0.42 446.055 301.17 ;
    RECT 445.13 0.42 445.3 301.17 ;
    RECT 443.975 0.42 444.55 301.17 ;
    RECT 443.2 0.42 443.395 301.17 ;
    RECT 442.45 0.42 442.62 301.17 ;
    RECT 441.395 0.42 441.87 301.17 ;
    RECT 439.285 0.42 440.815 301.17 ;
    RECT 438.235 0.42 438.705 301.17 ;
    RECT 437.48 0.42 437.655 301.17 ;
    RECT 436.73 0.42 436.9 301.17 ;
    RECT 435.575 0.42 436.15 301.17 ;
    RECT 434.8 0.42 434.995 301.17 ;
    RECT 434.05 0.42 434.22 301.17 ;
    RECT 432.995 0.42 433.47 301.17 ;
    RECT 430.885 0.42 432.415 301.17 ;
    RECT 429.835 0.42 430.305 301.17 ;
    RECT 429.08 0.42 429.255 301.17 ;
    RECT 428.33 0.42 428.5 301.17 ;
    RECT 427.175 0.42 427.75 301.17 ;
    RECT 426.4 0.42 426.595 301.17 ;
    RECT 425.65 0.42 425.82 301.17 ;
    RECT 424.595 0.42 425.07 301.17 ;
    RECT 422.485 0.42 424.015 301.17 ;
    RECT 421.435 0.42 421.905 301.17 ;
    RECT 420.68 0.42 420.855 301.17 ;
    RECT 419.93 0.42 420.1 301.17 ;
    RECT 418.775 0.42 419.35 301.17 ;
    RECT 418.0 0.42 418.195 301.17 ;
    RECT 417.25 0.42 417.42 301.17 ;
    RECT 416.195 0.42 416.67 301.17 ;
    RECT 414.085 0.42 415.615 301.17 ;
    RECT 413.035 0.42 413.505 301.17 ;
    RECT 412.28 0.42 412.455 301.17 ;
    RECT 411.53 0.42 411.7 301.17 ;
    RECT 410.375 0.42 410.95 301.17 ;
    RECT 409.6 0.42 409.795 301.17 ;
    RECT 408.85 0.42 409.02 301.17 ;
    RECT 407.795 0.42 408.27 301.17 ;
    RECT 405.685 0.42 407.215 301.17 ;
    RECT 404.635 0.42 405.105 301.17 ;
    RECT 403.88 0.42 404.055 301.17 ;
    RECT 403.13 0.42 403.3 301.17 ;
    RECT 401.975 0.42 402.55 301.17 ;
    RECT 401.2 0.42 401.395 301.17 ;
    RECT 400.45 0.42 400.62 301.17 ;
    RECT 399.395 0.42 399.87 301.17 ;
    RECT 397.285 0.42 398.815 301.17 ;
    RECT 396.235 0.42 396.705 301.17 ;
    RECT 395.48 0.42 395.655 301.17 ;
    RECT 394.73 0.42 394.9 301.17 ;
    RECT 393.575 0.42 394.15 301.17 ;
    RECT 392.8 0.42 392.995 301.17 ;
    RECT 392.05 0.42 392.22 301.17 ;
    RECT 390.995 0.42 391.47 301.17 ;
    RECT 388.885 0.42 390.415 301.17 ;
    RECT 387.835 0.42 388.305 301.17 ;
    RECT 387.08 0.42 387.255 301.17 ;
    RECT 386.33 0.42 386.5 301.17 ;
    RECT 385.175 0.42 385.75 301.17 ;
    RECT 384.4 0.42 384.595 301.17 ;
    RECT 383.65 0.42 383.82 301.17 ;
    RECT 382.595 0.42 383.07 301.17 ;
    RECT 380.485 0.42 382.015 301.17 ;
    RECT 379.435 0.42 379.905 301.17 ;
    RECT 378.68 0.42 378.855 301.17 ;
    RECT 377.93 0.42 378.1 301.17 ;
    RECT 376.775 0.42 377.35 301.17 ;
    RECT 376.0 0.42 376.195 301.17 ;
    RECT 375.25 0.42 375.42 301.17 ;
    RECT 374.195 0.42 374.67 301.17 ;
    RECT 372.085 0.42 373.615 301.17 ;
    RECT 371.035 0.42 371.505 301.17 ;
    RECT 370.28 0.42 370.455 301.17 ;
    RECT 369.53 0.42 369.7 301.17 ;
    RECT 368.375 0.42 368.95 301.17 ;
    RECT 367.6 0.42 367.795 301.17 ;
    RECT 366.85 0.42 367.02 301.17 ;
    RECT 365.795 0.42 366.27 301.17 ;
    RECT 363.685 0.42 365.215 301.17 ;
    RECT 362.635 0.42 363.105 301.17 ;
    RECT 361.88 0.42 362.055 301.17 ;
    RECT 361.13 0.42 361.3 301.17 ;
    RECT 359.975 0.42 360.55 301.17 ;
    RECT 359.2 0.42 359.395 301.17 ;
    RECT 358.45 0.42 358.62 301.17 ;
    RECT 357.395 0.42 357.87 301.17 ;
    RECT 355.285 0.42 356.815 301.17 ;
    RECT 354.235 0.42 354.705 301.17 ;
    RECT 353.48 0.42 353.655 301.17 ;
    RECT 352.73 0.42 352.9 301.17 ;
    RECT 351.575 0.42 352.15 301.17 ;
    RECT 350.8 0.42 350.995 301.17 ;
    RECT 350.05 0.42 350.22 301.17 ;
    RECT 348.995 0.42 349.47 301.17 ;
    RECT 346.885 0.42 348.415 301.17 ;
    RECT 345.835 0.42 346.305 301.17 ;
    RECT 345.08 0.42 345.255 301.17 ;
    RECT 344.33 0.42 344.5 301.17 ;
    RECT 343.175 0.42 343.75 301.17 ;
    RECT 342.4 0.42 342.595 301.17 ;
    RECT 341.65 0.42 341.82 301.17 ;
    RECT 340.595 0.42 341.07 301.17 ;
    RECT 338.485 0.42 340.015 301.17 ;
    RECT 337.435 0.42 337.905 301.17 ;
    RECT 336.68 0.42 336.855 301.17 ;
    RECT 335.93 0.42 336.1 301.17 ;
    RECT 333.79 0.42 335.35 301.17 ;
    RECT 332.465 0.42 333.05 301.17 ;
    RECT 331.145 0.42 331.725 301.17 ;
    RECT 329.82 0.42 330.405 301.17 ;
    RECT 327.165 0.42 327.75 301.17 ;
    RECT 325.84 0.42 326.425 301.17 ;
    RECT 324.525 0.42 325.1 301.17 ;
    RECT 323.48 0.42 323.785 301.17 ;
    RECT 322.45 0.42 322.74 301.17 ;
    RECT 321.13 0.42 321.71 301.17 ;
    RECT 319.795 0.42 320.39 301.17 ;
    RECT 317.74 0.42 319.055 301.17 ;
    RECT 315.825 0.42 316.41 301.17 ;
    RECT 314.5 0.42 315.085 301.17 ;
    RECT 313.18 0.42 313.76 301.17 ;
    RECT 311.855 0.42 312.44 301.17 ;
    RECT 309.21 0.42 311.115 301.17 ;
    RECT 307.705 0.42 308.47 301.17 ;
    RECT 303.975 0.42 306.965 301.17 ;
    RECT 300.36 0.42 303.405 301.17 ;
    RECT 299.255 0.42 299.62 301.17 ;
    RECT 296.575 0.42 297.13 301.17 ;
    RECT 295.27 0.42 295.835 301.17 ;
    RECT 293.965 0.42 294.53 301.17 ;
    RECT 291.91 0.42 293.225 301.17 ;
    RECT 290.06 0.42 290.625 301.17 ;
    RECT 288.765 0.42 289.32 301.17 ;
    RECT 284.81 0.42 288.025 301.17 ;
    RECT 282.67 0.42 284.24 301.17 ;
    RECT 281.28 0.42 281.93 301.17 ;
    RECT 280.02 0.42 280.71 301.17 ;
    RECT 278.695 0.42 279.28 301.17 ;
    RECT 277.375 0.42 277.955 301.17 ;
    RECT 274.73 0.42 275.31 301.17 ;
    RECT 273.415 0.42 273.99 301.17 ;
    RECT 272.085 0.42 272.665 301.17 ;
    RECT 269.78 0.42 271.335 301.17 ;
    RECT 269.03 0.42 269.2 301.17 ;
    RECT 268.275 0.42 268.45 301.17 ;
    RECT 267.225 0.42 267.695 301.17 ;
    RECT 265.115 0.42 266.645 301.17 ;
    RECT 264.06 0.42 264.535 301.17 ;
    RECT 263.31 0.42 263.48 301.17 ;
    RECT 262.535 0.42 262.73 301.17 ;
    RECT 261.38 0.42 261.955 301.17 ;
    RECT 260.63 0.42 260.8 301.17 ;
    RECT 259.875 0.42 260.05 301.17 ;
    RECT 258.825 0.42 259.295 301.17 ;
    RECT 256.715 0.42 258.245 301.17 ;
    RECT 255.66 0.42 256.135 301.17 ;
    RECT 254.91 0.42 255.08 301.17 ;
    RECT 254.135 0.42 254.33 301.17 ;
    RECT 252.98 0.42 253.555 301.17 ;
    RECT 252.23 0.42 252.4 301.17 ;
    RECT 251.475 0.42 251.65 301.17 ;
    RECT 250.425 0.42 250.895 301.17 ;
    RECT 248.315 0.42 249.845 301.17 ;
    RECT 247.26 0.42 247.735 301.17 ;
    RECT 246.51 0.42 246.68 301.17 ;
    RECT 245.735 0.42 245.93 301.17 ;
    RECT 244.58 0.42 245.155 301.17 ;
    RECT 243.83 0.42 244.0 301.17 ;
    RECT 243.075 0.42 243.25 301.17 ;
    RECT 242.025 0.42 242.495 301.17 ;
    RECT 239.915 0.42 241.445 301.17 ;
    RECT 238.86 0.42 239.335 301.17 ;
    RECT 238.11 0.42 238.28 301.17 ;
    RECT 237.335 0.42 237.53 301.17 ;
    RECT 236.18 0.42 236.755 301.17 ;
    RECT 235.43 0.42 235.6 301.17 ;
    RECT 234.675 0.42 234.85 301.17 ;
    RECT 233.625 0.42 234.095 301.17 ;
    RECT 231.515 0.42 233.045 301.17 ;
    RECT 230.46 0.42 230.935 301.17 ;
    RECT 229.71 0.42 229.88 301.17 ;
    RECT 228.935 0.42 229.13 301.17 ;
    RECT 227.78 0.42 228.355 301.17 ;
    RECT 227.03 0.42 227.2 301.17 ;
    RECT 226.275 0.42 226.45 301.17 ;
    RECT 225.225 0.42 225.695 301.17 ;
    RECT 223.115 0.42 224.645 301.17 ;
    RECT 222.06 0.42 222.535 301.17 ;
    RECT 221.31 0.42 221.48 301.17 ;
    RECT 220.535 0.42 220.73 301.17 ;
    RECT 219.38 0.42 219.955 301.17 ;
    RECT 218.63 0.42 218.8 301.17 ;
    RECT 217.875 0.42 218.05 301.17 ;
    RECT 216.825 0.42 217.295 301.17 ;
    RECT 214.715 0.42 216.245 301.17 ;
    RECT 213.66 0.42 214.135 301.17 ;
    RECT 212.91 0.42 213.08 301.17 ;
    RECT 212.135 0.42 212.33 301.17 ;
    RECT 210.98 0.42 211.555 301.17 ;
    RECT 210.23 0.42 210.4 301.17 ;
    RECT 209.475 0.42 209.65 301.17 ;
    RECT 208.425 0.42 208.895 301.17 ;
    RECT 206.315 0.42 207.845 301.17 ;
    RECT 205.26 0.42 205.735 301.17 ;
    RECT 204.51 0.42 204.68 301.17 ;
    RECT 203.735 0.42 203.93 301.17 ;
    RECT 202.58 0.42 203.155 301.17 ;
    RECT 201.83 0.42 202.0 301.17 ;
    RECT 201.075 0.42 201.25 301.17 ;
    RECT 200.025 0.42 200.495 301.17 ;
    RECT 197.915 0.42 199.445 301.17 ;
    RECT 196.86 0.42 197.335 301.17 ;
    RECT 196.11 0.42 196.28 301.17 ;
    RECT 195.335 0.42 195.53 301.17 ;
    RECT 194.18 0.42 194.755 301.17 ;
    RECT 193.43 0.42 193.6 301.17 ;
    RECT 192.675 0.42 192.85 301.17 ;
    RECT 191.625 0.42 192.095 301.17 ;
    RECT 189.515 0.42 191.045 301.17 ;
    RECT 188.46 0.42 188.935 301.17 ;
    RECT 187.71 0.42 187.88 301.17 ;
    RECT 186.935 0.42 187.13 301.17 ;
    RECT 185.78 0.42 186.355 301.17 ;
    RECT 185.03 0.42 185.2 301.17 ;
    RECT 184.275 0.42 184.45 301.17 ;
    RECT 183.225 0.42 183.695 301.17 ;
    RECT 181.115 0.42 182.645 301.17 ;
    RECT 180.06 0.42 180.535 301.17 ;
    RECT 179.31 0.42 179.48 301.17 ;
    RECT 178.535 0.42 178.73 301.17 ;
    RECT 177.38 0.42 177.955 301.17 ;
    RECT 176.63 0.42 176.8 301.17 ;
    RECT 175.875 0.42 176.05 301.17 ;
    RECT 174.825 0.42 175.295 301.17 ;
    RECT 172.715 0.42 174.245 301.17 ;
    RECT 171.66 0.42 172.135 301.17 ;
    RECT 170.91 0.42 171.08 301.17 ;
    RECT 170.135 0.42 170.33 301.17 ;
    RECT 168.98 0.42 169.555 301.17 ;
    RECT 168.23 0.42 168.4 301.17 ;
    RECT 167.475 0.42 167.65 301.17 ;
    RECT 166.425 0.42 166.895 301.17 ;
    RECT 164.315 0.42 165.845 301.17 ;
    RECT 163.26 0.42 163.735 301.17 ;
    RECT 162.51 0.42 162.68 301.17 ;
    RECT 161.735 0.42 161.93 301.17 ;
    RECT 160.58 0.42 161.155 301.17 ;
    RECT 159.83 0.42 160.0 301.17 ;
    RECT 159.075 0.42 159.25 301.17 ;
    RECT 158.025 0.42 158.495 301.17 ;
    RECT 155.915 0.42 157.445 301.17 ;
    RECT 154.86 0.42 155.335 301.17 ;
    RECT 154.11 0.42 154.28 301.17 ;
    RECT 153.335 0.42 153.53 301.17 ;
    RECT 152.18 0.42 152.755 301.17 ;
    RECT 151.43 0.42 151.6 301.17 ;
    RECT 150.675 0.42 150.85 301.17 ;
    RECT 149.625 0.42 150.095 301.17 ;
    RECT 147.515 0.42 149.045 301.17 ;
    RECT 146.46 0.42 146.935 301.17 ;
    RECT 145.71 0.42 145.88 301.17 ;
    RECT 144.935 0.42 145.13 301.17 ;
    RECT 143.78 0.42 144.355 301.17 ;
    RECT 143.03 0.42 143.2 301.17 ;
    RECT 142.275 0.42 142.45 301.17 ;
    RECT 141.225 0.42 141.695 301.17 ;
    RECT 139.115 0.42 140.645 301.17 ;
    RECT 138.06 0.42 138.535 301.17 ;
    RECT 137.31 0.42 137.48 301.17 ;
    RECT 136.535 0.42 136.73 301.17 ;
    RECT 135.38 0.42 135.955 301.17 ;
    RECT 134.63 0.42 134.8 301.17 ;
    RECT 133.875 0.42 134.05 301.17 ;
    RECT 132.825 0.42 133.295 301.17 ;
    RECT 130.715 0.42 132.245 301.17 ;
    RECT 129.66 0.42 130.135 301.17 ;
    RECT 128.91 0.42 129.08 301.17 ;
    RECT 128.135 0.42 128.33 301.17 ;
    RECT 126.98 0.42 127.555 301.17 ;
    RECT 126.23 0.42 126.4 301.17 ;
    RECT 125.475 0.42 125.65 301.17 ;
    RECT 124.425 0.42 124.895 301.17 ;
    RECT 122.315 0.42 123.845 301.17 ;
    RECT 121.26 0.42 121.735 301.17 ;
    RECT 120.51 0.42 120.68 301.17 ;
    RECT 119.735 0.42 119.93 301.17 ;
    RECT 118.58 0.42 119.155 301.17 ;
    RECT 117.83 0.42 118.0 301.17 ;
    RECT 117.075 0.42 117.25 301.17 ;
    RECT 116.025 0.42 116.495 301.17 ;
    RECT 113.915 0.42 115.445 301.17 ;
    RECT 112.86 0.42 113.335 301.17 ;
    RECT 112.11 0.42 112.28 301.17 ;
    RECT 111.335 0.42 111.53 301.17 ;
    RECT 110.18 0.42 110.755 301.17 ;
    RECT 109.43 0.42 109.6 301.17 ;
    RECT 108.675 0.42 108.85 301.17 ;
    RECT 107.625 0.42 108.095 301.17 ;
    RECT 105.515 0.42 107.045 301.17 ;
    RECT 104.46 0.42 104.935 301.17 ;
    RECT 103.71 0.42 103.88 301.17 ;
    RECT 102.935 0.42 103.13 301.17 ;
    RECT 101.78 0.42 102.355 301.17 ;
    RECT 101.03 0.42 101.2 301.17 ;
    RECT 100.275 0.42 100.45 301.17 ;
    RECT 99.225 0.42 99.695 301.17 ;
    RECT 97.115 0.42 98.645 301.17 ;
    RECT 96.06 0.42 96.535 301.17 ;
    RECT 95.31 0.42 95.48 301.17 ;
    RECT 94.535 0.42 94.73 301.17 ;
    RECT 93.38 0.42 93.955 301.17 ;
    RECT 92.63 0.42 92.8 301.17 ;
    RECT 91.875 0.42 92.05 301.17 ;
    RECT 90.825 0.42 91.295 301.17 ;
    RECT 88.715 0.42 90.245 301.17 ;
    RECT 87.66 0.42 88.135 301.17 ;
    RECT 86.91 0.42 87.08 301.17 ;
    RECT 86.135 0.42 86.33 301.17 ;
    RECT 84.98 0.42 85.555 301.17 ;
    RECT 84.23 0.42 84.4 301.17 ;
    RECT 83.475 0.42 83.65 301.17 ;
    RECT 82.425 0.42 82.895 301.17 ;
    RECT 80.315 0.42 81.845 301.17 ;
    RECT 79.26 0.42 79.735 301.17 ;
    RECT 78.51 0.42 78.68 301.17 ;
    RECT 77.735 0.42 77.93 301.17 ;
    RECT 76.58 0.42 77.155 301.17 ;
    RECT 75.83 0.42 76.0 301.17 ;
    RECT 75.075 0.42 75.25 301.17 ;
    RECT 74.025 0.42 74.495 301.17 ;
    RECT 71.915 0.42 73.445 301.17 ;
    RECT 70.86 0.42 71.335 301.17 ;
    RECT 70.11 0.42 70.28 301.17 ;
    RECT 69.335 0.42 69.53 301.17 ;
    RECT 68.18 0.42 68.755 301.17 ;
    RECT 67.43 0.42 67.6 301.17 ;
    RECT 66.675 0.42 66.85 301.17 ;
    RECT 65.625 0.42 66.095 301.17 ;
    RECT 63.515 0.42 65.045 301.17 ;
    RECT 62.46 0.42 62.935 301.17 ;
    RECT 61.71 0.42 61.88 301.17 ;
    RECT 60.935 0.42 61.13 301.17 ;
    RECT 59.78 0.42 60.355 301.17 ;
    RECT 59.03 0.42 59.2 301.17 ;
    RECT 58.275 0.42 58.45 301.17 ;
    RECT 57.225 0.42 57.695 301.17 ;
    RECT 55.115 0.42 56.645 301.17 ;
    RECT 54.06 0.42 54.535 301.17 ;
    RECT 53.31 0.42 53.48 301.17 ;
    RECT 52.535 0.42 52.73 301.17 ;
    RECT 51.38 0.42 51.955 301.17 ;
    RECT 50.63 0.42 50.8 301.17 ;
    RECT 49.875 0.42 50.05 301.17 ;
    RECT 48.825 0.42 49.295 301.17 ;
    RECT 46.715 0.42 48.245 301.17 ;
    RECT 45.66 0.42 46.135 301.17 ;
    RECT 44.91 0.42 45.08 301.17 ;
    RECT 44.135 0.42 44.33 301.17 ;
    RECT 42.98 0.42 43.555 301.17 ;
    RECT 42.23 0.42 42.4 301.17 ;
    RECT 41.475 0.42 41.65 301.17 ;
    RECT 40.425 0.42 40.895 301.17 ;
    RECT 38.315 0.42 39.845 301.17 ;
    RECT 37.26 0.42 37.735 301.17 ;
    RECT 36.51 0.42 36.68 301.17 ;
    RECT 35.735 0.42 35.93 301.17 ;
    RECT 34.58 0.42 35.155 301.17 ;
    RECT 33.83 0.42 34.0 301.17 ;
    RECT 33.075 0.42 33.25 301.17 ;
    RECT 32.025 0.42 32.495 301.17 ;
    RECT 29.915 0.42 31.445 301.17 ;
    RECT 28.86 0.42 29.335 301.17 ;
    RECT 28.11 0.42 28.28 301.17 ;
    RECT 27.335 0.42 27.53 301.17 ;
    RECT 26.18 0.42 26.755 301.17 ;
    RECT 25.43 0.42 25.6 301.17 ;
    RECT 24.675 0.42 24.85 301.17 ;
    RECT 23.625 0.42 24.095 301.17 ;
    RECT 21.515 0.42 23.045 301.17 ;
    RECT 20.46 0.42 20.935 301.17 ;
    RECT 19.71 0.42 19.88 301.17 ;
    RECT 18.935 0.42 19.13 301.17 ;
    RECT 17.78 0.42 18.355 301.17 ;
    RECT 17.03 0.42 17.2 301.17 ;
    RECT 16.275 0.42 16.45 301.17 ;
    RECT 15.225 0.42 15.695 301.17 ;
    RECT 13.115 0.42 14.645 301.17 ;
    RECT 12.06 0.42 12.535 301.17 ;
    RECT 11.31 0.42 11.48 301.17 ;
    RECT 10.535 0.42 10.73 301.17 ;
    RECT 9.38 0.42 9.955 301.17 ;
    RECT 8.63 0.42 8.8 301.17 ;
    RECT 7.875 0.42 8.05 301.17 ;
    RECT 6.825 0.42 7.295 301.17 ;
    RECT 4.715 0.42 6.245 301.17 ;
    RECT 3.66 0.42 4.135 301.17 ;
    RECT 2.91 0.42 3.08 301.17 ;
    RECT 2.135 0.42 2.33 301.17 ;
    RECT 1.25 0.42 1.555 301.17 ;
    END
  END sp_hse_8192_m16

END LIBRARY

